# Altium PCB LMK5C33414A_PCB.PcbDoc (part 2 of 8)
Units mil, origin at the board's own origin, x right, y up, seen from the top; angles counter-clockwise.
Board outline 7000 x 9161 mil, 8 copper layers (L1-Top Layer (GTL), L2-GND Plane (GP1), L3-Mid-Layer 2 (G1), L4-Mid-Layer 3 (G2), L5-Mid-Layer 4 (G3), L6-Mid-Layer 5 (G4), L7-Mid-Layer 6 (G5), L8-Bottom Layer (GBL)), stack 61.2 mil thick; 521 components, 286 nets, 1393 pads, 2202 vias.

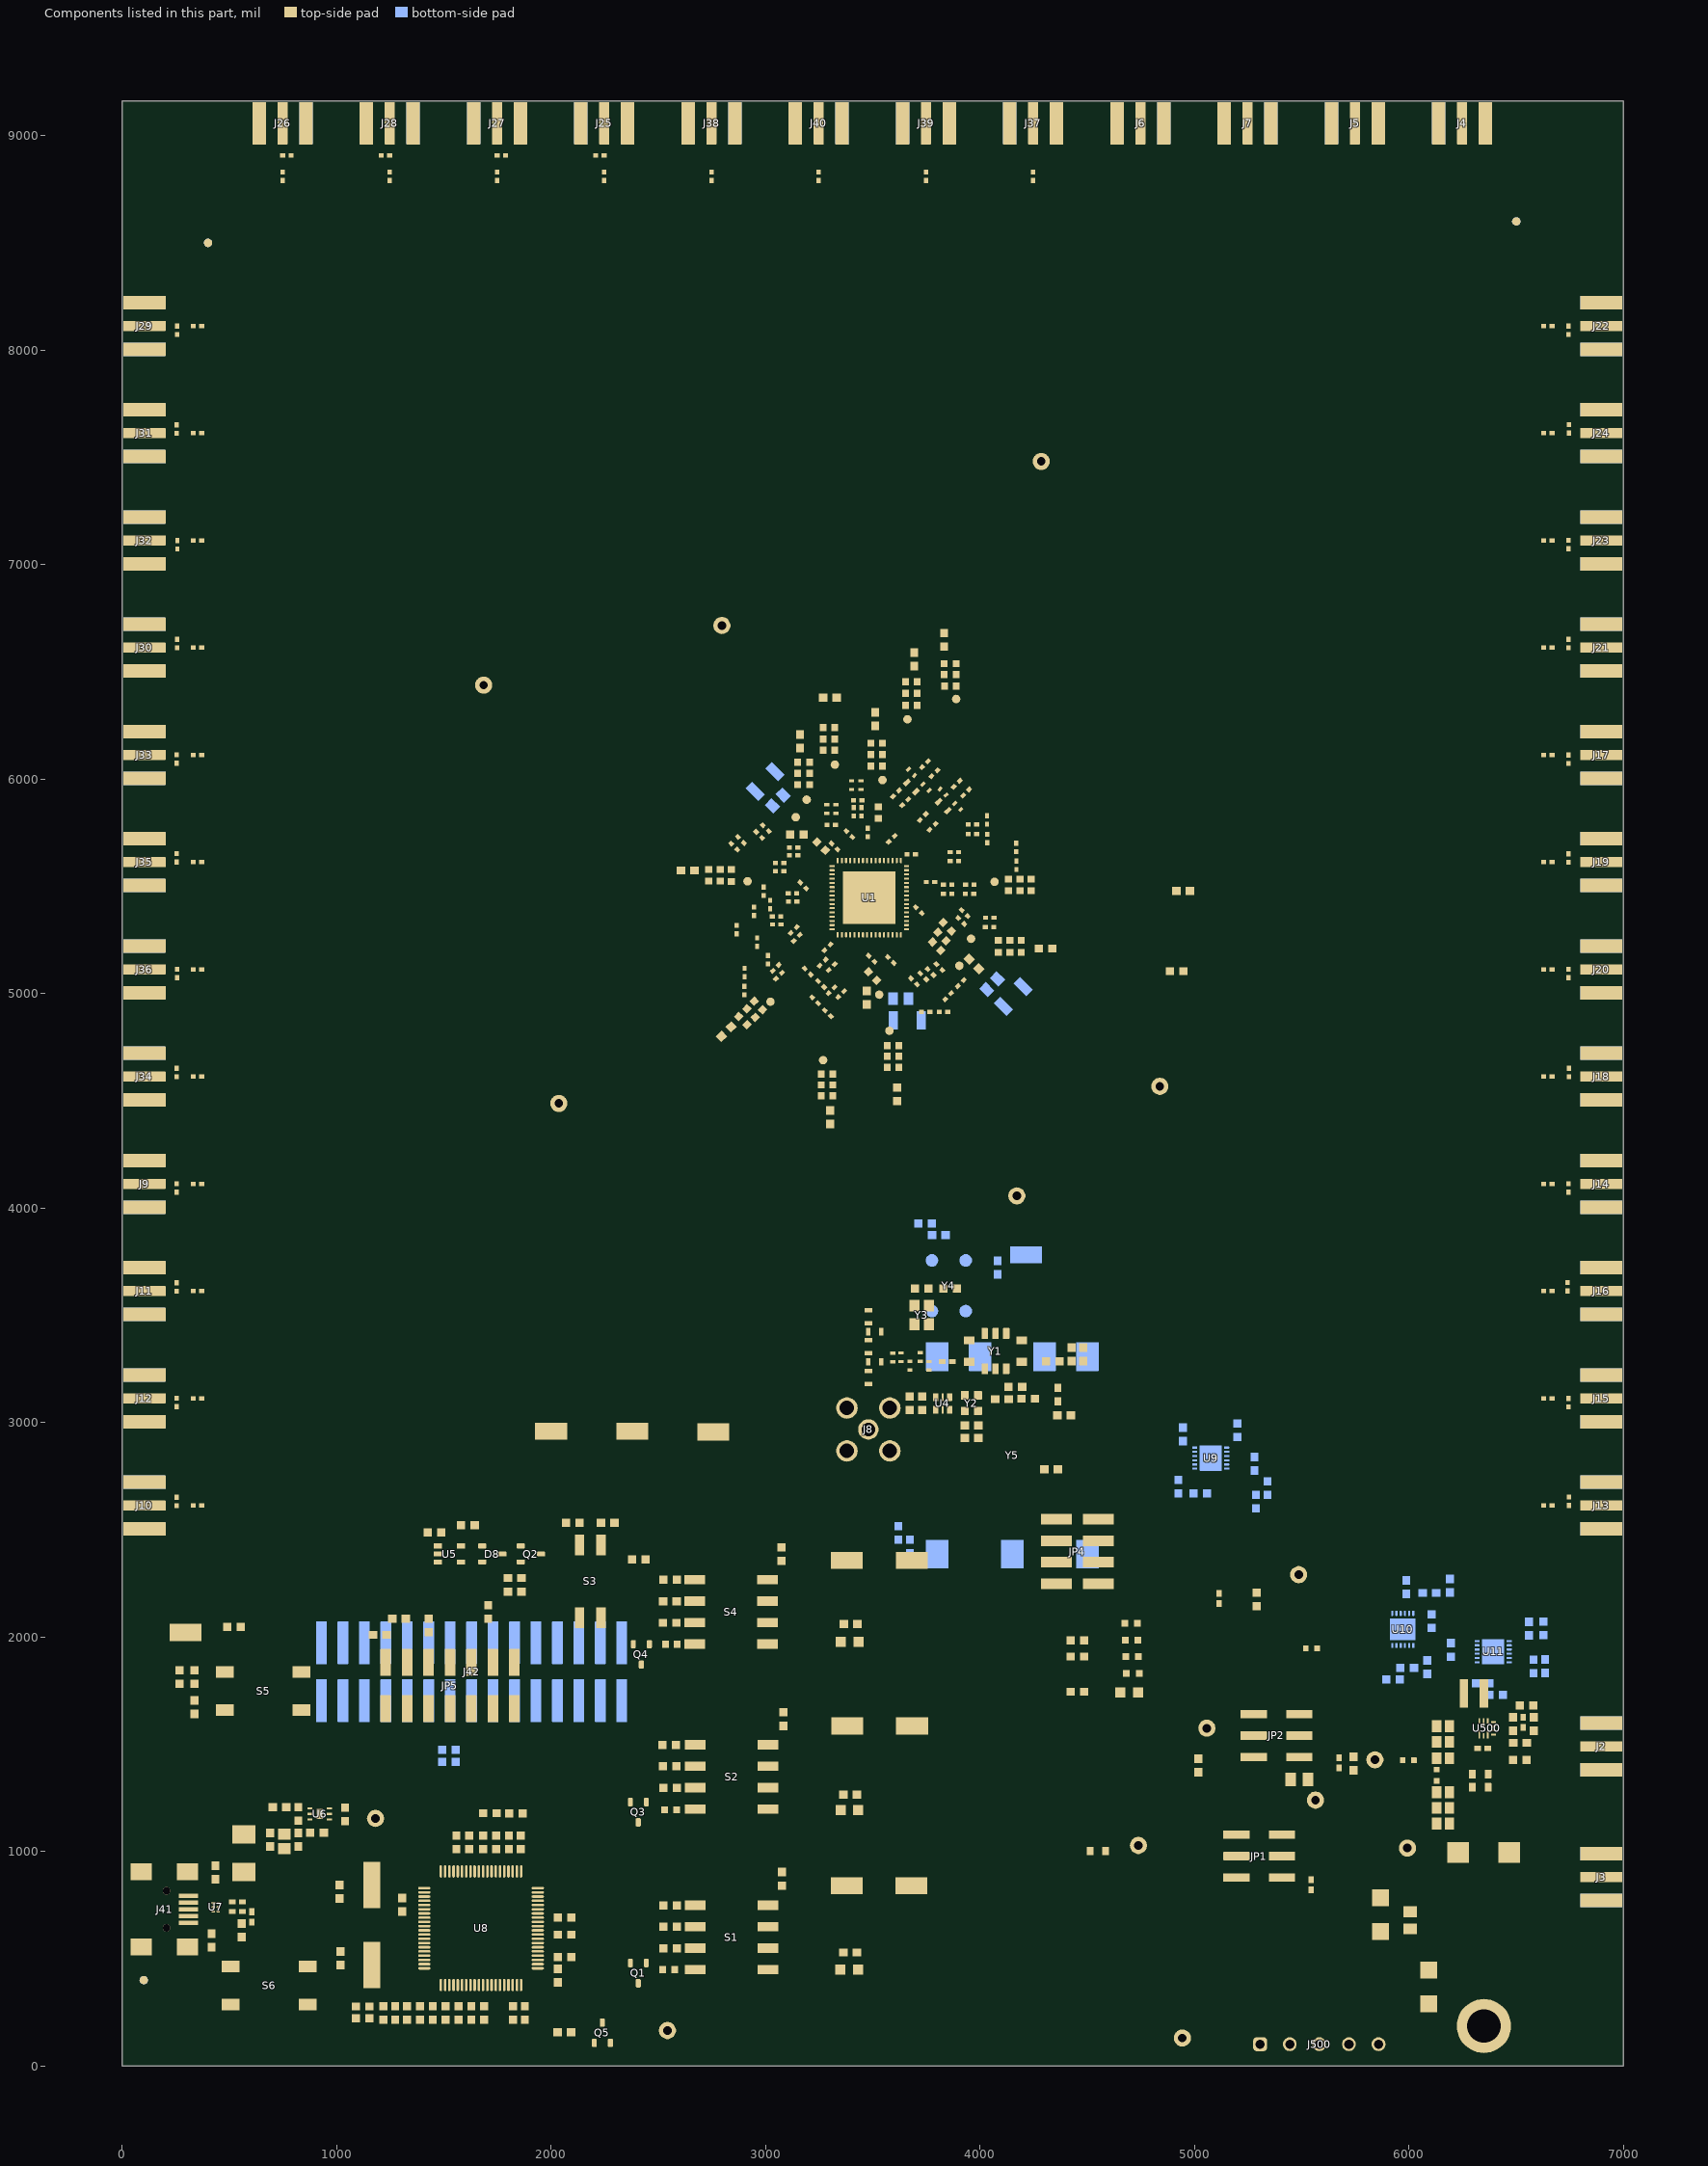
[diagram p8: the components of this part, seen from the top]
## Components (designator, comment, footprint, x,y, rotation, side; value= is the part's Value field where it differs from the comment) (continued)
Q4 "BSS138" SOT-23 2420.31,1918.8 r270 top value=50V
Q5 "BSS138" SOT-23 2238.4,154.32 r90 top value=50V
R1 "CRCW060323K2FKEA" 0603 5991.2,1856.4 r180 bottom value=23.2k
R2 "CRCW060313K3FKEA" 0603 6085.2,1859.4 r90 bottom value=13.3k
R3 "CRCW060323K2FKEA" 0603 6343.2,1784.4 r180 bottom value=23.2k
R5 "CRCW060313K3FKEA" 0603 6406.2,1730.4 r180 bottom value=13.3k
R6 "RK73Z1ETTP" 0402L 3266,5144 r225 top value=0
R7 "RK73Z1ETTP" 0402L 3352,4997 r225 top value=0
R8 "CRCW060323K2FKEA" 0603 4924,2701 r90 bottom value=23.2k
R9 "CRCW060313K3FKEA" 0603 5027,2669 r180 bottom value=13.3k
R10 "RK73Z1ETTP" 0402L 3308,5123 r225 top value=0
R11 "CRCW06030000Z0EA" 0603 3832.36,6649.5 r90 top value=0
R12 "CRCW06030000Z0EA" 0603 2816.76,4822.22 r225 top value=0
R13 "Resistor" 0603 4453.36,1983.18 r0 top value=470
R14 "Resistor" 0603 4453.36,1908.44 r0 top value=470
R15 "Resistor" 0603 4331.09,2780.89 r0 top value=470
R16 "CRCW06030000Z0EA" 0603 3693.18,6558.4 r90 top value=0
R17 "CRCW06030000Z0EA" 0603 3301.03,4423.17 r270 top value=0
R18 "CRCW06030000Z0EA" 0603 3511.08,6279.33 r90 top value=0
R19 "CRCW06030000Z0EA" 0603 4947.24,5478.79 r0 top value=0
R20 "CRCW06030000Z0EA" 0603 3612.65,4530.27 r270 top value=0
R21 "CRCW06030000Z0EA" 0603 2636.5,5573.42 r180 top value=0
R22 "CRCW06030000Z0EA" 0603 4304.83,5210.12 r0 top value=0
R24 "CRCW06030000Z0EA" 0603 3300,6380 r180 top value=0
R25 "CRCW06030000Z0EA" 0603 3160.02,6175.71 r90 top value=0
R26 "CRCW04020000Z0EDHP" 0402L 3934.69,5937.26 r225 top value=0
R27 "CRCW04020000Z0EDHP" 0402L 3778.3,5777.55 r225 top value=0
R28 "RC0402JR-0751RL" 0402S 3895.63,5872.08 r135 top value=51
R29 "CRCW0603100RFKEA" 0603S 3828.19,5873.76 r315 top value=100
R30 "CRCW04020000Z0EDHP" 0402L 3891.24,5977.73 r225 top value=0
R31 "CRCW04020000Z0EDHP" 0402L 3732.94,5822.69 r225 top value=0
R32 "RC0402JR-0751RL" 0402S 3827.19,5939.76 r315 top value=51
R33 "CRCW04020000Z0EDHP" 0402L 3743.11,6068.89 r225 top value=0
R34 "CRCW04020000Z0EDHP" 0402L 3607.91,5932.81 r225 top value=0
R35 "RC0402JR-0751RL" 0402S 3679.67,6030.76 r315 top value=51
R36 "CRCW0603100RFKEA" 0603S 3679.61,5962.39 r135 top value=100
R37 "CRCW04020000Z0EDHP" 0402L 3787.11,6026.89 r225 top value=0
R38 "CRCW04020000Z0EDHP" 0402L 3650.61,5891.39 r225 top value=0
R39 "RC0402JR-0751RL" 0402S 3747.61,5961.39 r135 top value=51
R40 "Capacitor" 0603S 3479,3493 r90 top value=0.1uF
R41 "Resistor" 0603S 3479,3353.4 r90 top value=0
R42 "Resistor" 0603S 3509,3423 r180 top value=49.9
R43 "CRCW040233R0JNED" 0402 3846.56,3283.85 r0 top value=33
R44 "ERJ-3GEY0R00V" 0603 4224.36,3110.68 r180 top value=0
R45 "Resistor" 0603 4101.93,3108.93 r180 top value=10k
R46 "CRCW04020000Z0EDHP" 0402S 3760.85,3263.89 r270 top value=0
R47 "CRCW040233R0JNED" 0402S 3720.85,3304.78 r90 top value=33
R48 "CRCW040233R0JNED" 0402S 3631.08,3304.13 r90 top value=33
R49 "CRCW040233R0JNED" 0402S 3592.08,3302.71 r90 top value=33
R50 "CRCW040233R0JNED" 0402S 3672.76,3264.22 r270 top value=33
R51 "Resistor" 0603 2555.01,748.55 r0 top value=10k
R52 "Resistor" 0603 2555.01,648.55 r0 top value=0
R53 "CRCW06033K90JNEA" 0603 2555.01,548.55 r0 top value=3.9k
R54 "Resistor" 0603 4453.36,1744.56 r180 top value=470
R55 "Resistor" 0603L 2548,449 r180 top value=0
R56 "Resistor" 0603 3393.51,529.08 r180 top value=470
R57 "Resistor" 0603 1835.01,1177.36 r0 top value=1.5k
R58 "Resistor" 0603 1714.47,1178.52 r180 top value=1.5k
R59 "Resistor" 0603 1201,2010 r180 top value=1.5k
R60 "Resistor" 0603 1291,2085 r180 top value=1.5k
R61 "Resistor" 0603 1455.41,2486.9 r0 top value=0
R62 "Resistor" 0603 1830.04,2210.2 r180 top value=100k
R63 "Resistor" 0603 2549.78,1495.82 r0 top value=10k
R64 "Resistor" 0603 2552.58,1397.12 r0 top value=0
R65 "CRCW06033K90JNEA" 0603 2554.26,1295.82 r0 top value=3.9k
R66 "Resistor" 0603L 2557,1194 r180 top value=0
R67 "Resistor" 0603 3393.51,1265.08 r180 top value=470
R68 "Resistor" 0603 2100.26,2531.71 r0 top value=10k
R69 "Resistor" 0603 2263.26,2531.71 r180 top value=3.9k
R70 "Resistor" 0603 2554.44,2266.55 r0 top value=10k
R71 "Resistor" 0603 2553.2,2166.55 r180 top value=0
R72 "CRCW06033K90JNEA" 0603 2552.7,2066.05 r0 top value=3.9k
R73 "Resistor" 0603L 2560.14,1966.55 r180 top value=0
R74 "Resistor" 0603 3396.02,2059.81 r180 top value=470
R75 "Resistor" 0603 267.14,1812.72 r270 top value=10k
R76 "Resistor" 0603 337.14,1672.72 r90 top value=1.0k
R77 "ESR03EZPJ101" 0603 337.14,1812.72 r90 top value=100
R78 "RC0402JR-0751RL" 0402L 254,4093 r270 top value=51
R79 "RC0402JR-0751RL" 0402L 253,2632 r90 top value=51
R80 "RK73Z1ETTP" 0402L 3307,5015 r225 top value=0
R81 "RK73Z1ETTP" 0402L 3691.74,5056.26 r315 top value=0
R82 "RC0402JR-0751RL" 0402L 254,3632 r90 top value=51
R83 "RK73Z1ETTP" 0402L 3810,5123 r315 top value=0
R84 "RK73Z1ETTP" 0402L 3735,5080 r315 top value=0
R85 "RC0402JR-0751RL" 0402L 254,3093 r270 top value=51
R86 "RC0402JR-0751RL" 0402L 6745,2633 r90 top value=51
R87 "RK73Z1ETTP" 0402L 3769,5100 r315 top value=0
R88 "RC0402JR-0751RL" 0402L 6744,4093 r270 top value=51
R89 "RK73Z1ETTP" 0402L 3848,5508 r0 top value=0
R90 "RC0402JR-0751RL" 0402L 6744,3092 r270 top value=51
R91 "RK73Z1ETTP" 0402L 3911.97,5338.03 r315 top value=0
R92 "RC0402JR-0751RL" 0402L 6739.7,3632.9 r90 top value=51
R93 "RK73Z1ETTP" 0402L 3848,5465 r0 top value=0
R94 "RC0402JR-0751RL" 0402L 6744,6092 r270 top value=51
R95 "RK73Z1ETTP" 0402L 3928,5375 r315 top value=0
R96 "RC0402JR-0751RL" 0402L 6745,4632 r90 top value=51
R97 "RK73Z1ETTP" 0402L 3880,5617 r0 top value=0
R98 "RK73Z1ETTP" 0402L 3964,5787.73 r0 top value=0
R99 "RC0402JR-0751RL" 0402L 6743,5632 r90 top value=51
R100 "RK73Z1ETTP" 0402L 3880,5659 r0 top value=0
R101 "RC0402JR-0751RL" 0402L 6744,5093 r270 top value=51
R102 "RK73Z1ETTP" 0402L 3964,5743.73 r0 top value=0
R103 "RC0402JR-0751RL" 0402L 6743,6632 r90 top value=51
R104 "RK73Z1ETTP" 0402L 3131,5680 r180 top value=0
R105 "RC0402JR-0751RL" 0402L 6743,8092 r270 top value=51
R106 "RK73Z1ETTP" 0402L 3065,5570 r180 top value=0
R107 "RK73Z1ETTP" 0402L 3130,5644 r180 top value=0
R108 "RK73Z1ETTP" 0402L 3065,5609 r180 top value=0
R109 "RC0402JR-0751RL" 0402L 6744,7093 r270 top value=51
R110 "RK73Z1ETTP" 0402L 3125,5467 r180 top value=0
R111 "RC0402JR-0751RL" 0402L 6745,7633 r90 top value=51
R112 "RK73Z1ETTP" 0402L 3052,5322 r180 top value=0
R113 "RC0402JR-0751RL" 0402L 2227,8907 r180 top value=51
R114 "RK73Z1ETTP" 0402L 3126,5428 r180 top value=0
R115 "RC0402JR-0751RL" 0402L 768,8907 r0 top value=51
R116 "RK73Z1ETTP" 0402L 3051,5359 r180 top value=0
R117 "RC0402JR-0751RL" 0402L 1768,8907 r0 top value=51
R118 "RK73Z1ETTP" 0402L 3131,5296 r225 top value=0
R119 "RC0402JR-0751RL" 0402L 1227,8907 r180 top value=51
R120 "RK73Z1ETTP" 0402L 3062,5082.63 r225 top value=0
R121 "RC0402JR-0751RL" 0402L 255,8092 r270 top value=51
R122 "RC0402JR-0751RL" 0402L 255,6632 r90 top value=51
R123 "RK73Z1ETTP" 0402L 3145,5259 r225 top value=0
R124 "RK73Z1ETTP" 0402L 3047,5119.63 r225 top value=0
R125 "RC0402JR-0751RL" 0402L 254,7632 r90 top value=51
R126 "RK73Z1ETTP" 0402L 3447,5847 r90 top value=0
R127 "RC0402JR-0751RL" 0402L 257,7092 r270 top value=51
R128 "RK73Z1ETTP" 0402L 351,3612.5 r180 top value=0
R129 "RC0402JR-0751RL" 0402L 254,6093 r270 top value=51
R130 "RK73Z1ETTP" 0402L 3411,5847 r90 top value=0
R131 "RC0402JR-0751RL" 0402L 254,4632 r90 top value=51
R132 "RK73Z1ETTP" 0402L 351,4112.5 r180 top value=0
R133 "RC0402JR-0751RL" 0402L 254,5633 r90 top value=51
R134 "RC0402JR-0751RL" 0402L 2901.71,5097.43 r90 top value=51
R135 "RC0402JR-0751RL" 0402L 255,5093 r270 top value=51
R136 "RC0402JR-0751RL" 0402S 3444.59,5971.63 r90 top value=51
R137 "CRCW04020000Z0EDHP" 0402L 4247.5,8810 r270 top value=0
R138 "RC0402JR-0751RL" 0402S 3284.39,5860.05 r90 top value=51
R139 "CRCW04020000Z0EDHP" 0402L 2747.5,8810 r270 top value=0
R140 "CRCW04020000Z0EDHP" 0402L 3747.5,8810 r270 top value=0
R141 "RC0402JR-0751RL" 0402S 3400.59,5971.63 r90 top value=51
R142 "CRCW04020000Z0EDHP" 0402L 3247.5,8810 r270 top value=0
R143 "RC0402JR-0751RL" 0402S 3328.39,5860.05 r90 top value=51
R144 "Resistor" 0402 536,765 r180 top value=33
R145 "Resistor" 0603 820.5,1174.59 r90 top value=33k
R146 "Resistor" 0402 536,720 r180 top value=33
R147 "Resistor" 0402 604,695 r90 top value=1.5k
R148 "Resistor" 0603 416,585 r90 top value=33k
R149 "Resistor" 0603 557,632 r90 top value=1.2Meg
R150 "Resistor" 0603 2031.21,420.35 r270 top value=0
R151 "Resistor" 0603 2062.71,611.85 r0 top value=0
R152 "Resistor" 0603 2062.71,506.85 r0 top value=0
R153 "Resistor" 0603 2062.71,691.85 r0 top value=0
R154 "Resistor" 0603 1857.71,1041.85 r90 top value=0
R155 "Resistor" 0603 1802.71,1041.85 r270 top value=0
R156 "Resistor" 0603 1742.71,1041.85 r270 top value=0
R157 "Resistor" 0603 1617.71,1041.85 r90 top value=0
R158 "CRCW06030000Z0EA" 0603 1557.71,1041.85 r90 top value=0
R159 "CRCW06031K00JNEA" 0603 1567.71,246.85 r270 top value=1.0k
R160 "CRCW06031K00JNEA" 0603 1627.71,246.85 r270 top value=1.0k
R161 "Resistor" 0603 1272.71,246.85 r270 top value=510
R162 "Resistor" 0603 1387.71,246.85 r270 top value=510
R163 "Resistor" 0603 1447.71,246.85 r270 top value=0
R164 "Resistor" 0603 1507.71,246.85 r270 top value=0
R165 "Resistor" 0603 1121.21,276.85 r0 top value=33k
R166 "Resistor" 0603 2061,157 r180 top value=510
R167 "RC0402JR-0751RL" 0402L 3196.3,5102.4 r135 top value=51
R168 "RC0402JR-0751RL" 0402L 3290.1,4907.7 r315 top value=51
R169 "RC0402JR-0751RL" 0402L 3258.6,5044.1 r315 top value=51
R170 "RC0402JR-0751RL" 0402L 3230.7,4968.5 r135 top value=51
R171 "RC0402JR-0751RL" 0402L 3746.02,4914.81 r180 top value=51
R172 "RC0402JR-0751RL" 0402L 3909.91,5048.39 r45 top value=51
R173 "RC0402JR-0751RL" 0402L 3829.55,4914.64 r0 top value=51
R174 "RC0402JR-0751RL" 0402L 3850.94,4987.2 r225 top value=51
R175 "RC0402JR-0751RL" 0402L 4044.49,5309.45 r0 top value=51
R176 "RC0402JR-0751RL" 0402L 3952,5508 r0 top value=51
R177 "RC0402JR-0751RL" 0402L 4044.82,5353.81 r0 top value=51
R178 "RC0402JR-0751RL" 0402L 4032,5809 r90 top value=51
R179 "RC0402JR-0751RL" 0402L 4169,5598 r270 top value=51
R180 "RC0402JR-0751RL" 0402L 4034,5723 r270 top value=51
R181 "RC0402JR-0751RL" 0402L 3000.7,5770.85 r135 top value=51
R182 "RC0402JR-0751RL" 0402L 2853.44,5684.89 r135 top value=51
R183 "RC0402JR-0751RL" 0402L 2969.59,5739.74 r135 top value=51
R184 "RC0402JR-0751RL" 0402L 2884.55,5716 r135 top value=51
R185 "RC0402JR-0751RL" 0402L 2991.21,5477 r90 top value=51
R186 "RC0402JR-0751RL" 0402L 2864,5298 r270 top value=51
R187 "RC0402JR-0751RL" 0402L 3021,5415 r270 top value=51
R188 "RC0402JR-0751RL" 0402L 2946,5383 r90 top value=51
R189 "RC0402JR-0751RL" 0402L 2960,5239 r90 top value=51
R190 "RC0402JR-0751RL" 0402L 2901.07,5013.86 r270 top value=51
R191 "RC0402JR-0751RL" 0402L 3010.72,5158 r270 top value=51
R192 "CRCW0402100RFKED" 0402L 3429.5,5901.3 r0 top value=100
R193 "CRCW0402100RFKED" 0402L 3306.3,5786.7 r180 top value=100
R201 "Resistor" 0603 6095.2,2205.4 r180 bottom value=47k
R202 "Resistor" 0603 6559.2,2039.4 r270 bottom value=47k
R203 "Resistor" 0603 5340,2694 r270 bottom value=47k
R204 "RC0402JR-0751RL" 0402L 3951,5465 r0 top value=51
R205 "RC0402JR-0751RL" 0402L 4168,5681 r90 top value=51
R206 "RC0603JR-070RL" 0603 4339,3285 r180 top value=0
R207 "RC0603JR-070RL" 0603 3960,2927 r180 top value=0
R208 "RC0603JR-070RL" 0603 3860.06,3624.84 r180 top value=0
R209 "RC0603JR-070RL" 0603 3743,3928 r0 bottom value=0
R210 "RC0603JR-070RL" 0603 3619.07,2485 r270 bottom value=0
R211 "RC0603JR-070RL" 0603 3671,3089 r90 top value=0
R212 "Resistor" 0603 1523,1473 r180 bottom value=0
R500 "ERJ-3GEY0R00V" 0603 6516.1,1427.1 r180 top value=0
R501 "RG1608P-562-B-T5" 0603 6485.1,1593.4 r270 top value=5.60k
R502 "CRCW060318K2FKEA" 0603 6548,1680.8 r180 top value=18.2k
R504 "RT0603BRD071K8L" 0603 6581.9,1593.4 r90 top value=1.80k
S1 "SW_4SPST" SW_219-4LPST 2840.7,598.55 r0 top
S2 "SW_4SPST" SW_219-4LPST 2841.3,1347.55 r0 top
S3 "SW_219-2LPST" SW_219-2LPST 2181.76,2259.71 r90 top
S4 "SW_4SPST" SW_219-4LPST 2838.89,2116.55 r0 top
S5 "PDN" SW_FSM4JSMA 656.89,1748.14 r90 top
S6 "BSL" SW_FSM4JSMA 685,375 r90 top
SH1 "SNT-100-BK-G" SNT-100-BK-G 5316.8,878.7 r180 top value=1x2
SH2 "SNT-100-BK-G" SNT-100-BK-G 5381.7,1441.6 r180 top value=1x2
SH4 "SNT-100-BK-G" SNT-100-BK-G 4455.8,2247.5 r180 top value=1x2
SH5 "SNT-100-BK-G" SNT-100-BK-G 1226,1775 r90 top value=1x2
SH6 "SNT-100-BK-G" SNT-100-BK-G 1329,1775 r90 top value=1x2
TP1 "VDD_DCDC" Keystone5000 5992.6,1015.5 r0 top
TP2 "VDD" Keystone5000 4738.19,1027.87 r0 top
TP4 "VDDO_DCDC" Keystone5000 5841.1,1427.2 r180 top
TP5 "VDDO" Keystone5000 5057.36,1574.59 r0 top
TP7 "VIN2" Keystone5000 5563.8,1239.2 r90 top
TP8 "VDD_IN0" TP_SM_1MM 3888.33,6373.35 r135 top
TP9 "VDDO_01" TP_SM_1MM 3022.58,4961.73 r315 top
TP10 "VDD_IN1" TP_SM_1MM 3661.18,6278.63 r270 top
TP11 "VDDO_23" TP_SM_1MM 3268.02,4689.1 r0 top
TP12 "VDD_DIG" TP_SM_1MM 3544.7,5995.31 r180 top
TP13 "VDDO_4TO7" TP_SM_1MM 4067.45,5520.77 r90 top
TP14 "VDD_APLL1_XO" TP_SM_1MM 3577,4825.94 r180 top
TP15 "VDDO_8TO13" TP_SM_1MM 2915.38,5523.18 r135 top
TP16 "VDD_APLL2" TP_SM_1MM 3957.71,5255.11 r90 top
TP17 "VDD_IN23" TP_SM_1MM 3322.5,6067.14 r270 top
TP18 "VDD_APLL3" TP_SM_1MM 3191.41,5903.83 r0 top
TP19 "GND" Keystone5001 4171.45,4056.53 r0 top
TP20 "GND" Keystone5001 4837.9,4567.14 r180 top
TP21 "GND" Keystone5001 2035.56,4487.64 r180 top
TP22 "GND" Keystone5001 2796,6716 r180 top
TP23 "GND" Keystone5001 1685,6438 r0 top
TP24 "GND" Keystone5001 4285,7481 r90 top
TP25 "GND" Keystone5001 4943,130 r180 top
TP26 "GND" Keystone5001 2542,165 r90 top
TP27 "LF1" TP_SM_1MM 3529.53,4994.42 r180 top
TP28 "LF2" TP_SM_1MM 3903.24,5129.23 r90 top
TP29 "LF3" TP_SM_1MM 3140.18,5822.1 r90 top
TP30 "Vc" Keystone_5019 4213.84,3781.64 r180 bottom
TP31 "GPIO0" Keystone_5019 3378,840 r0 top
TP32 "GND" Keystone_5019 3679,840 r0 top
TP33 "GPIO1" Keystone_5019 3380,1585 r0 top
TP34 "SCL/SCK" Keystone_5019 2000,2959 r180 top
TP35 "GND" Keystone_5019 3683,1585 r0 top
TP36 "SDA/SDIO" Keystone_5019 2378,2959 r180 top
TP37 "ADD/SCS" Keystone_5019 2756,2956 r0 top
TP38 "GPIO2" Keystone_5019 3378,2357 r0 top
TP39 "GND" Keystone_5019 3682,2357 r0 top
TP40 "PDN" Keystone_5019 294.81,2020.61 r180 top
TP41 "MCU_3V3" Keystone5000 1180.98,1153.97 r0 top
TP501 "VDD_XO_DCDC" Keystone5000 5485.4,2290.5 r90 top
U1 "LMK5C33414ARGCR" RGC0064E-MFG 3483.15,5446.85 r90 top locked
U4 "CDC64XX-2520" DLF0006A 3825.05,3088.7 r90 top
U5 "TI-XOR-1-2IN-5" DBV0005A_N 1525.41,2386.9 r0 top
U6 "LP5900SD-3.3/NOPB" NGF0006A 920.5,1174.59 r180 top
U7 "TPD4E004DRYR" DRY0006A 436,740 r0 top
U8 "MSP430F5529IPN" PN0080A_N 1672.71,641.85 r90 top
U9 "LP38798SD-ADJ/NOPB" DNT0012B 5075.06,2833.49 r180 bottom
U10 "LP38798SD-ADJ/NOPB" DNT0012B 5970.95,2035.4 r270 bottom
U11 "LP38798SD-ADJ/NOPB" DNT0012B 6392.2,1931.4 r180 bottom
U500 "TPS62913RPUT" RPU0010A 6357.5,1574 r270 top
Y1 "7N48071001" FP-7N48071001_SMT10_7MM0_5MM0-MFG 4071.72,3332.66 r180 top
Y2 "LMK6CE04800ADLE" TXC_8W 3959.39,3090.31 r180 top
Y3 "7X-50.000MBB-T" OSC_TXC-7X 3727.32,3501.04 r270 top
Y4 "ROM9070PA" FP-ROM9070PA_SMD4-MFG 3854.21,3637.36 r270 bottom
Y5 "ROX2522S4" "FP-ROX2522S4_SMD_ OCXO7_25MM4_22MM0-MFG" 4150.17,2846.25 r180 bottom locked
Y6 "Xtal" XTAL_CSM-7X 1162.71,656.85 r270 top
ZZ1 "This Assembly Note is for PCB labels only" AssemblyNoteLabel 200,10300 r0 top
ZZ2 "These assemblies are ESD sensitive, ESD precautions shall be observed." AssemblyNote 200,10200 r0 top
ZZ3 "These assemblies must be clean and free from flux and all contaminants. Use of no clean flux is not acceptable." AssemblyNote 200,10100 r0 top
ZZ4 "These assemblies must comply with workmanship standards IPC-A-610 Class 2, unless otherwise specified." AssemblyNote 200,10000 r0 top
ZZ5 "Default Shunt (SH) settings for JP* headers: Connect Shunts (SH) on JP1(1-2=DC/DC to VDD), JP2(1-2=DC/DC to VDDO), JP4(1-2=DC/DC to XO), JP5(1-2=SDA, 3-4=SCL)." AssemblyNote 200,9900 r0 top
ZZ6 "Place serial number sticker on top side of PCB." AssemblyNote 204.71,9793.79 r0 top
ZZ7 "This Assembly SMA connectors must be installed per manufacturers procedure." AssemblyNote 200,9700 r0 top

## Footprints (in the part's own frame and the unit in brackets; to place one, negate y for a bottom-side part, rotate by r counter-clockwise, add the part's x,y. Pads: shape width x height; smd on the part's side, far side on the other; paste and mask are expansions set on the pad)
3M_SJ61A6 [mil] "BUMPER CYLIN 0.312\" DIA"
  body extent -156,-156 156,156, height 195
0402 [mm] "0402 from SM-752 data"
  rect 0.8x0.6 smd: 1(-0.6,0) 2(0.6,0)
  silkscreen extent -1.22,-0.52 1.22,0.52, body extent -0.55,-0.3 0.55,0.3, height 0.6
0402L [mm] "0402 from SM-752 data"
  rect 0.6x0.5 smd: 1(-0.5,0) 2(0.5,0)
  body extent -0.55,-0.3 0.55,0.3, height 0.6
0402S [mil] "Based on C0402S footprint from PADS legacy"
  rect 15x24 smd: 1(-20,0) 2(20,0)
  body extent -22,-12 22,12, height 24
0603 [mm] "0603 from SM-752 data"
  rect 1x0.95 smd: 1(-0.8,0) 2(0.8,0)
  silkscreen extent -1.52,-0.69 1.52,0.69, body extent -0.87,-0.47 0.87,0.47, height 1
0603L [mm] "0603 from SM-752 data"
  rect 0.8x0.85 smd: 1(-0.7,0) 2(0.7,0)
  silkscreen extent -0.07,-0.32 0.07,0.32, body extent -0.87,-0.47 0.87,0.47, height 1
0603S [mil]
  rect 20x35 smd: 1(-30,0) 2(30,0)
  body extent -34,-19 34,19, height 39
0805 [mm] "0805 from SM-752 data"
  rect 1.3x1.5 smd: 1(-0.85,0) 2(0.85,0)
  silkscreen extent -1.72,-0.97 1.72,0.97, body extent -1.1,-0.72 1.1,0.72, height 1.45
0805_150 [mm] "0805 / 1.5 mm height"
  rect 1.15x1.45 smd: 1(-0.9,0) 2(0.9,0)
  silkscreen extent -0.1,-0.8 0.1,0.8, body extent -1.1,-0.72 1.1,0.72, height 1.5
0805_HV [mil] "0805 with 30mil clearance between pads"
  rect 50x63 smd: 1(-40,0) 2(40,0)
  silkscreen extent -74,-40 74,40, body extent -43,-29 43,29, height 57
0805L [mm] "0805 from SM-752 data"
  rect 1.1x1.4 smd: 1(-0.75,0) 2(0.75,0)
  body extent -1.1,-0.72 1.1,0.72, height 1.45
1210_280 [mm] "SMD, 2-Leads, Body 3.6x2.8mm, Height 2.8mm"
  rect 1.1x2.2 smd: 1(-1.65,0) 2(1.65,0)
  silkscreen extent -0.84,-1.4 0.84,1.4, body extent -1.8,-1.4 1.8,1.4, height 2.8
7343-43 [mm] "Medium density IPC based on Kemet T495 series"
  rect 2.55x2.45 smd: 1(-3.025,0) 2(3.025,0)
  silkscreen extent -4.56,-2.3 3.8,2.3, body extent -3.8,-2.3 3.8,2.3, height 4.3
AssemblyNote [mil] "Assembly Note"
AssemblyNoteLabel [mil] "Assembly Note for PCB Labels"
CONN_USB-Mini-B-1734035-2 [mm] "Tyco Connectivity recommended land pattern"
  rect 0.5x2.3 smd: 1(-1.6,2.6) 2(-0.8,2.6) 3(0,2.6) 4(0.8,2.6) 5(1.6,2.6)
  rect 2x2.5 smd: 6(4.45,2.5) 7(4.45,-3) 8(-4.45,-3) 9(-4.45,2.5)
  round 0.9 hole 0.9 unplated: 10(2.2,0) 11(-2.2,0)
  silkscreen extent -5,-5 4.9,4.19, body extent -4.95,-5.9 4.95,3.3, height 4.1
DBV0005A_N [mm] "SOT23, 5-Leads, Body 2.9x1.6mm, Pitch 0.95mm, Lead Span 2.8mm, IPC Medium Density"
  rrect17% 1x0.6 smd: 1(-1.375,0.95) 2(-1.375,0) 3(-1.375,-0.95) 4(1.375,-0.95) 5(1.375,0.95)
  silkscreen extent -1.63,-1.55 0.38,1.55, body extent -1.42,-1.46 1.42,1.46, height 1.09
DLF0006A [mm] "VSON-6"
  rrect15% 0.9x0.65 smd paste-0.65: 1(-0.75,0.825) 3(-0.75,-0.825) 4(0.75,-0.825) 6(0.75,0.825)
  rrect40% 0.9x0.25 smd: 2(-0.75,0) 5(0.75,0)
  silkscreen extent -1.5,-1.45 1.5,1.45, body extent -1,-1.25 1,1.25, height 0.9
DNT0012B [mm] "SON, 12-Leads, Body 4x4mm, Pitch 0.5mm"
  rrect40% 0.6x0.25 smd: 1(-1.9,1.25) 2(-1.9,0.75) 3(-1.9,0.25) 4(-1.9,-0.25) 5(-1.9,-0.75) 6(-1.9,-1.25) 7(1.9,-1.25) 8(1.9,-0.75) 9(1.9,-0.25) 10(1.9,0.25) 11(1.9,0.75) 12(1.9,1.25)
  rrect4% 2.6x3 smd paste-1.3: 13(0,0)
  silkscreen extent -2.2,-2.2 2.2,2.2, body extent -2,-2 2,2, height 0.81
DRY0006A [mm] "USON-6"
  rrect67% 0.45x0.3 smd paste-0.05 mask-0.05: 1(-0.275,0.5)
  rrect67% 0.4x0.3 smd paste-0.05 mask-0.05: 2(-0.3,0) 3(-0.3,-0.5) 4(0.3,-0.5) 5(0.3,0) 6(0.3,0.5)
  body extent -0.5,-0.72 0.5,0.73, height 0.58
FCC_disclaimer [mil]
Fiducial10-20 [mm]
  round 1 smd mask+0.5: 1(0,0)
  L1-Top Layer (GTL) keep-out circle w1.178: c0,0 r0.5
FP-7N48071001_SMT10_7MM0_5MM0-MFG [mm]
  rrect13% 0.76x1.28 smd paste+0 mask+0: 1(-1.27,-2.09) 2(0,-2.09) 3(1.27,-2.09) 6(1.27,2.09) 7(0,2.09) 8(-1.27,2.09)
  rrect11% 1.28x0.94 smd paste+0 mask+0: 4(3.1,-1.27) 5(3.1,1.27) 9(-3.1,1.27) 10(-3.1,-1.27)
  silkscreen extent -3.57,-3.4 3.57,2.58, body extent -3.84,-2.83 3.84,2.83, height 0.25
FP-54202-G0807LF_HDR14-MFG [mm]
  rrect8% 1.27x3.18 smd paste+0 mask+0: A01(-7.62,-2.73) A02(-5.08,-2.73) A03(-2.54,-2.73) A04(0,-2.73) A05(2.54,-2.73) A06(5.08,-2.73) A07(7.62,-2.73) B01(-7.62,2.73) B02(-5.08,2.73) B03(-2.54,2.73) B04(0,2.73) B05(2.54,2.73) B06(5.08,2.73) B07(7.62,2.73)
  silkscreen extent -10.23,-3.75 10.23,2.48, body extent -10.33,-4.42 10.33,4.42, height 0.25
FP-BLE18PS080SN1_0603-MFG [mm]
  rrect15% 0.65x0.7 smd paste+0 mask+0: 1(-0.675,0) 2(0.675,0)
  body extent -1.1,-0.58 1.1,0.58, height 0.25
FP-C2012X7S1E106K125AC_0805-MFG [mm]
  rrect13% 0.8x1.05 smd paste+0 mask+0: 1(-0.925,0) 2(0.925,0)
  silkscreen extent -0.15,-0.72 0.15,0.72, body extent -1.43,-0.82 1.43,0.82, height 0.25
FP-CON-SMA-EDGE-S_CONN_JACK-MFG [mm]
  rrect8% 1.2x5 smd paste+0 mask+0: 1(0,-7.26)
  rrect6% 1.6x5 smd paste+0 mask+0: 2(-2.77,-7.26) 3(2.77,-7.26)
  rrect6% 1.6x5 smd far side paste+0 mask+0: 4(-2.77,-7.26) 5(2.77,-7.26)
  body extent -3.27,-9.86 3.27,4.86, height 0.25
FP-ROM9070PA_SMD4-MFG [mm]
  round 1.5 smd paste+0 mask+0: 1(-3,-2) 2(3,-2) 3(3,2) 4(-3,2)
  silkscreen extent -4.95,-4.5 4.95,3.85, body extent -4.85,-3.75 4.85,3.75, height 4.1
"FP-ROX2522S4_SMD_ OCXO7_25MM4_22MM0-MFG" [mm]
  rrect4% 2.7x3.4 smd paste+0 mask+0: 1(-8.9,-11.7) 2(0,-11.7) 3(8.9,-11.7) 4(8.9,11.7) 5(3.81,11.7) 6(-3.81,11.7) 7(-8.9,11.7)
  silkscreen extent -11.1,-14.1 11.1,12.8, body extent -11,-12.7 11,12.7, height 15.4
FP-XGL4030-222MEC_SMT_IND_4MM0_4MM0-MFG [mm]
  rrect10% 0.98x3.4 smd paste+0 mask+0: 1(-1.185,0) 2(1.185,0)
  silkscreen extent -2.15,-2.15 2.15,2.15, body extent -2.25,-2.25 2.25,2.25, height 0.25
Johnson_142-0701-20x [mil] "Johnson Components recommended land pattern"
  round 95 hole 62: 1(0,0)
  round 100 hole 67: 2(100,100) 3(100,-100) 4(-100,-100) 5(-100,100)
  body extent -156,-156 156,156, height 375
Keystone5000 [mil] "For Keystone 500x miniature loop terminals"
  round 80 hole 40: 1(0,0)
  silkscreen extent -52,-52 52,52, body extent -49,-49 49,49, height 182
Keystone5001 [mil] "For Keystone 500x miniature loop terminals"
  round 80 hole 40: 1(0,0)
  silkscreen extent -52,-52 52,52, body extent -49,-49 49,49, height 182
Keystone_5019 [mm] "Test Point, Miniature, SMT"
  rect 3.8x2.03 smd: 1(0,0)
  silkscreen extent -2.31,-1.42 2.31,1.42, body extent -1.91,-1.02 1.9,1.02, height 2.29
Label_650x200 [mil] "Thermal Transfer Label"
  round 1 on Mech13: 0(0,0)
  silkscreen extent -325,-100 325,100, body extent -325,-100 325,100, height 1
LED_LTST-C170 [mm] "LITE-ON"
  rect 1.2x1.2 smd: 1(-1.05,0) 2(1.05,0)
  silkscreen extent -1.6,-1 2.2,1, body extent -1.05,-0.67 1.05,0.67, height 1.1
LED_LTST-C170_Red [mm] "LITE-ON"
  rect 1.2x1.2 smd: 1(-1.05,0) 2(1.05,0)
  silkscreen extent -1.6,-1 2.2,1, body extent -1.05,-0.67 1.05,0.67, height 1.1
LED_LTST-C190 [mm] "Lite-On"
  rect 0.8x0.8 smd: 1(-0.75,0) 2(0.75,0)
  silkscreen extent -1.1,-0.8 1.8,0.8, body extent -0.85,-0.45 0.85,0.45, height 0.9
LI0603D [mm] "LAIRD"
  rect 1x0.8 smd: 1(-0.8,0) 2(0.8,0)
  silkscreen extent -1.53,-0.63 1.53,0.63, body extent -0.87,-0.47 0.87,0.47, height 0.95
Molex_0393570005 [mil] "Terminal Block, 3.5mm, 5x1, TH"
  rrect50% 64.5x64.5 hole 43: 1(0,276)
  round 64.5 hole 43: 2(0,138) 3(0,0) 4(0,-138) 5(0,-276)
  body extent -136,-345 151,345, height 335
MTGP_252mil_157mil_6Via [mil] "4-40 Mounting Hole, Plated, for Pan Head"
  round 252 hole 157: 1(0,0)
NetTie_0603 [mm] "Net Tie 0603 size"
  rect 0.8x0.95 smd paste-1: 1(-0.9,0) 2(0.9,0)
  L1-Top Layer (GTL) region: -0.6,0.406 0.6,0.406 0.6,-0.406 -0.6,-0.406
  silkscreen extent -0.1,-0.38 0.1,0.38
NGF0006A [mm] "TI"
  rect 0.6x0.25 smd: 1(-1.15,0.65) 2(-1.15,0) 3(-1.15,-0.65) 4(1.15,-0.65) 5(1.15,0) 6(1.15,0.65)
  rect 0.75x1.2 smd paste-0.38: 7(0,0)
  silkscreen extent -1.4,-1.25 1.4,1.25, body extent -1.3,-1.15 1.3,1.15, height 0.81
OSC_TXC-7X [mm] "TXC recommended land pattern"
  rect 1.4x1.2 smd: 1(-1.1,-0.85) 2(1.1,-0.85) 3(1.1,0.85) 4(-1.1,0.85)
  silkscreen extent -1.31,-1.96 -1.2,-1.84, body extent -2.03,-1.65 2.03,1.65, height 1.11
PN0080A_N [mm] "QFP, 80-Leads, Body 12x12mm, Pitch 0.5mm, IPC Medium Density"
  oval 1.45x0.3 smd: 1(-6.725,4.75) 2(-6.725,4.25) 3(-6.725,3.75) 4(-6.725,3.25) 5(-6.725,2.75) 6(-6.725,2.25) 7(-6.725,1.75) 8(-6.725,1.25) 9(-6.725,0.75) 10(-6.725,0.25) 11(-6.725,-0.25) 12(-6.725,-0.75) 13(-6.725,-1.25) 14(-6.725,-1.75) 15(-6.725,-2.25) 16(-6.725,-2.75) 17(-6.725,-3.25) 18(-6.725,-3.75) 19(-6.725,-4.25) 20(-6.725,-4.75) 41(6.725,-4.75) 42(6.725,-4.25) 43(6.725,-3.75) 44(6.725,-3.25) 45(6.725,-2.75) 46(6.725,-2.25) 47(6.725,-1.75) 48(6.725,-1.25) 49(6.725,-0.75) 50(6.725,-0.25) 51(6.725,0.25) 52(6.725,0.75) 53(6.725,1.25) 54(6.725,1.75) 55(6.725,2.25) 56(6.725,2.75) 57(6.725,3.25) 58(6.725,3.75) 59(6.725,4.25) 60(6.725,4.75)
  oval 0.3x1.45 smd: 21(-4.75,-6.725) 22(-4.25,-6.725) 23(-3.75,-6.725) 24(-3.25,-6.725) 25(-2.75,-6.725) 26(-2.25,-6.725) 27(-1.75,-6.725) 28(-1.25,-6.725) 29(-0.75,-6.725) 30(-0.25,-6.725) 31(0.25,-6.725) 32(0.75,-6.725) 33(1.25,-6.725) 34(1.75,-6.725) 35(2.25,-6.725) 36(2.75,-6.725) 37(3.25,-6.725) 38(3.75,-6.725) 39(4.25,-6.725) 40(4.75,-6.725) 61(4.75,6.725) 62(4.25,6.725) 63(3.75,6.725) 64(3.25,6.725) 65(2.75,6.725) 66(2.25,6.725) 67(1.75,6.725) 68(1.25,6.725) 69(0.75,6.725) 70(0.25,6.725) 71(-0.25,6.725) 72(-0.75,6.725) 73(-1.25,6.725) 74(-1.75,6.725) 75(-2.25,6.725) 76(-2.75,6.725) 77(-3.25,6.725) 78(-3.75,6.725) 79(-4.25,6.725) 80(-4.75,6.725)
  silkscreen extent -6.85,-5.6 5.6,5.6, body extent -7,-7 7,7, height 1.56
RGC0064E-MFG [mm]
  rrect42% 0.6x0.24 smd paste+0 mask+0: 1(-4.4,3.75) 2(-4.4,3.25) 3(-4.4,2.75) 4(-4.4,2.25) 5(-4.4,1.75) 6(-4.4,1.25) 7(-4.4,0.75) 8(-4.4,0.25) 9(-4.4,-0.25) 10(-4.4,-0.75) 11(-4.4,-1.25) 12(-4.4,-1.75) 13(-4.4,-2.25) 14(-4.4,-2.75) 15(-4.4,-3.25) 16(-4.4,-3.75) 33(4.4,-3.75) 34(4.4,-3.25) 35(4.4,-2.75) 36(4.4,-2.25) 37(4.4,-1.75) 38(4.4,-1.25) 39(4.4,-0.75) 40(4.4,-0.25) 41(4.4,0.25) 42(4.4,0.75) 43(4.4,1.25) 44(4.4,1.75) 45(4.4,2.25) 46(4.4,2.75) 47(4.4,3.25) 48(4.4,3.75)
  rrect42% 0.24x0.6 smd paste+0 mask+0: 17(-3.75,-4.4) 18(-3.25,-4.4) 19(-2.75,-4.4) 20(-2.25,-4.4) 21(-1.75,-4.4) 22(-1.25,-4.4) 23(-0.75,-4.4) 24(-0.25,-4.4) 25(0.25,-4.4) 26(0.75,-4.4) 27(1.25,-4.4) 28(1.75,-4.4) 29(2.25,-4.4) 30(2.75,-4.4) 31(3.25,-4.4) 32(3.75,-4.4) 49(3.75,4.4) 50(3.25,4.4) 51(2.75,4.4) 52(2.25,4.4) 53(1.75,4.4) 54(1.25,4.4) 55(0.75,4.4) 56(0.25,4.4) 57(-0.25,4.4) 58(-0.75,4.4) 59(-1.25,4.4) 60(-1.75,4.4) 61(-2.25,4.4) 62(-2.75,4.4) 63(-3.25,4.4) 64(-3.75,4.4)
  rrect2% 6.25x6.25 smd paste-1000 mask+0: 65(0,0)
  silkscreen extent -5.4,-4.57 4.57,4.57, body extent -4.8,-4.8 4.8,4.8, height 0.25
RPU0010A [mm] "VQFN-10"
  rrect50% 0.65x0.2 smd: 1(-0.875,0.25) 3(-0.875,-0.75) 5(0.875,-0.25)
  rrect50% 1x0.2 smd: 2(-0.7,-0.25) 4(0.7,-0.75) 6(0.7,0.25)
  rrect50% 0.25x0.55 smd: 7(0.75,0.925) 8(0.25,0.925) 9(-0.25,0.925) 10(-0.75,0.925)
  silkscreen extent -1.2,0.6 -1.1,0.8, body extent -1.05,-1.05 1.05,1.05, height 1
Samtec_HTST-115-01-x-DV [mm] "Header, 2.54mm, 15x2, SMT"
  rrect8% 5.08x1.27 smd: 1(-3.43,17.78) 2(3.43,17.78) 3(-3.43,15.24) 4(3.43,15.24) 5(-3.43,12.7) 6(3.43,12.7) 7(-3.43,10.16) 8(3.43,10.16) 9(-3.43,7.62) 10(3.43,7.62) 11(-3.43,5.08) 12(3.43,5.08) 13(-3.43,2.54) 14(3.43,2.54) 15(-3.43,0) 16(3.43,0) 17(-3.43,-2.54) 18(3.43,-2.54) 19(-3.43,-5.08) 20(3.43,-5.08) 21(-3.43,-7.62) 22(3.43,-7.62) 23(-3.43,-10.16) 24(3.43,-10.16) 25(-3.43,-12.7) 26(3.43,-12.7) 27(-3.43,-15.24) 28(3.43,-15.24) 29(-3.43,-17.78) 30(3.43,-17.78)
  silkscreen extent -4.8,-22.86 4.83,22.86, body extent -5.59,-22.86 5.59,22.86, height 10.17
Samtec_TSM-104-01-x-DV [mm] "Header, 2.54mm, 4x2, SMT"
  rect 3.68x1.27 smd: 1(-2.475,3.81) 2(2.475,3.81) 3(-2.475,1.27) 4(2.475,1.27) 5(-2.475,-1.27) 6(2.475,-1.27) 7(-2.475,-3.81) 8(2.475,-3.81)
  silkscreen extent -1.65,-5.08 1.65,5.22, body extent -3.85,-5.08 3.85,5.08, height 9.65
SMA [mm] "Molded Diode, 2-Leads, Body 4.3x2.6mm, IPC Medium Density, based on OnSemi component dimensions and land pattern"
  rect 2x2 smd: 1(-2,0) 2(2,0)
  silkscreen extent -3.66,-1.57 2.79,1.57, body extent -2.6,-1.3 2.6,1.3, height 2.42
SMB [mil] "Molded Diode, 2-Leads, Body 5.4x3.6mm, IPC Medium Density, based on OnSemi component dimensions"
  rect 85x107.99 smd: 1(-87.01,0) 2(87.01,0)
  silkscreen extent -155,-82 125,82, body extent -106,-71 106,71, height 91
SNT-100-BK-G [mil] "Samtec STEP model"
  round 1 on Mech3: 0(0,0)
  body extent -100,-50 100,50, height 344
SOT-23 [mm] "SOT23, 3-Leads, Body 2.9x1.3mm, Pitch 0.95mm, Lead Span 2.5mm, IPC Medium Density"
  rrect50% 1x0.6 smd: 1(-1.2,0.95) 2(-1.2,-0.95) 3(1.2,0)
  silkscreen extent -1.62,-1.5 0.7,1.5, body extent -1.16,-1.45 1.21,1.45, height 1
SW_219-2LPST [mm] "SW, Tape Seal, 2 POS, SMD"
  rect 2.44x1.12 smd: 1(-4.305,1.27) 2(-4.305,-1.27) 3(4.305,-1.27) 4(4.305,1.27)
  silkscreen extent -3.32,-3.28 3.38,3.28, body extent -4.95,-3.28 4.96,3.27, height 4.25
SW_219-4LPST [mil] "SMD, 8-Leads, Body 11.93x6.95mm, Pitch 2.54mm"
  rect 96x44 smd: 1(-169.5,150) 2(-169.5,50) 3(-169.5,-50) 4(-169.5,-150) 5(169.5,-150) 6(169.5,-50) 7(169.5,50) 8(169.5,150)
  silkscreen extent -171,-229 132,229, body extent -195,-229 195,229, height 169
SW_FSM4JSMA [mm] "Alcoswitch"
  rrect7% 1.4x2.1 smd: 1(2.25,4.55) 2(2.25,-4.55) 3(-2.25,4.55) 4(-2.25,-4.55)
  body extent -3,-5 3,5, height 5.09
TP_SM_1MM [mm] "1mm Test Point, SMT"
  round 1 smd paste-0.5: 1(0,0)
TXC_8W [mm] "SMD, 4-Leads, Body 2x2.5 mm"
  rrect13% 0.95x1 smd: 1(-0.775,0.925) 2(-0.775,-0.925) 3(0.775,-0.925) 4(0.775,0.925)
  silkscreen extent -1.5,0.5 -1.5,1.4, body extent -1,-1.25 1,1.25, height 0.9
Wurth_61000621121 [mm] "Header, 2.54mm, 3x2, SMT"
  rrect10% 3.1x1 smd: 1(-2.7,2.54) 2(2.7,2.54) 3(-2.7,0) 4(2.7,0) 5(-2.7,-2.54) 6(2.7,-2.54)
  body extent -3.75,-3.81 3.75,3.81, height 9.6
XTAL_CSM-7X [mm] "ECS"
  rect 5.5x2 smd: 1(-4.75,0) 2(4.75,0)
  silkscreen extent -6.2,-2.5 6.2,2.5, body extent -5.95,-2.4 5.95,2.4, height 4.3

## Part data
C1 C2 C8 C9 C22 C23 C29 C32 C35 C38 C44 C47 C50 C53 C56 C59 C62 C63 C64 C65 C66 C79 C97 C129 C130: library part CMP-0007003-5, "CAP, CERM, 10 uF, 10 V, +/- 20%, X5R, 0603", Cap_Case=0603, Manufacturer=TDK, PartNumber=C1608X5R1A106M080AC, Supplier Part Number 1=445-6853-1-ND, TempCo=X5R, Tolerance_%=20%, Value1="0.0078 ohm", Value2=10V, ValueDisplayed=10uF
C6 C21: library part CMP-0006869-5, "CAP, CERM, 1 uF, 10 V, +/- 10%, X5R, 0603", Cap_Case=0603, Manufacturer=Kemet, PartNumber=C0603C105K8PACTU, Supplier Part Number 1=399-3118-1-ND, TempCo=X5R, Tolerance_%=10%, Value1=Unknown, Value2=10V, ValueDisplayed=1uF
C7 C13 C24: library part CMP-0007003-5, "CAP, CERM, 10 uF, 10 V, +/- 20%, X5R, 0603", Cap_Case=0603, Manufacturer=TDK, PartNumber=C1608X5R1A106M080AC, Supplier Part Number 1=445-6853-1-ND, TempCo=X5R, Tolerance_%=20%, Value1="0.0078 ohm", Value2=10V, ValueDisplayed=10nF
C10 C27: library part CMP-0078699-1, "CAP, CERM, 47 µF, 10 V,+/- 20%, X5R, 0805", Cap_Case=0805, Manufacturer=MuRata, Supplier Part Number 1=490-9961-1-ND, TempCo=X5R, Tolerance_%=20%, Value2=10V, ValueDisplayed=47µF
C28 C31 C34 C37 C40 C43 C46 C49 C52 C55 C58 C78 C80 C81 C82 C83 C84 C85 C87 R40: library part CMP-0006856-6, "CAP, CERM, 0.1 uF, 25 V, +/- 5%, X7R, 0603", Cap_Case=0603, Manufacturer=Kemet, PartNumber=C0603C104J3RACTU, Supplier Part Number 1=399-1282-1-ND, TempCo=X7R, Tolerance_%=5%, Value1=Unknown, Value2=25V, ValueDisplayed=0.1uF
C30 C33 C36 C39 C42 C45 C48 C51 C54 C57 C60: library part CMP-0006259-2, "CAP, CERM, 0.1 uF, 10 V, +/- 10%, X5R, 0402", Cap_Case=0402, Manufacturer=TDK, PartNumber=C1005X5R1A104K050BA, Supplier Part Number 1=445-1265-1-ND, TempCo=X5R, Tolerance_%=10%, Value1=Unknown, Value2=10V, ValueDisplayed=0.1uF
C41: library part CMP-0006869-5, "CAP, CERM, 1 uF, 10 V, +/- 10%, X5R, 0603", Cap_Case=0603, Manufacturer=Kemet, Supplier Part Number 1=399-3118-1-ND, TempCo=X5R, Tolerance_%=10%, Value1=Unknown, Value2=10V, ValueDisplayed=1uF
C61: library part CMP-0007044-5, "CAP, CERM, 0.1 uF, 50 V, +/- 10%, X7R, 0603", Cap_Case=0603, Manufacturer=TDK, Supplier Part Number 1=445-1314-1-ND, TempCo=X7R, Tolerance_%=10%, Value1="0.0296 ohm", Value2=50V, ValueDisplayed=0.1uF
C67 C70 C71 C72 C96: library part CMP-0006856-6, "CAP, CERM, 0.1 uF, 25 V, +/- 5%, X7R, 0603", Cap_Case=0603, Manufacturer=Kemet, Supplier Part Number 1=399-1282-1-ND, TempCo=X7R, Tolerance_%=5%, Value1=Unknown, Value2=25V, ValueDisplayed=0.1uF
C68: library part CMP-0078743-1, "CAP, CERM, 0.047 µF, 25 V,+/- 5%, C0G/NP0, AEC-Q200 Grade 1, 0805", Cap_Case=0805_150, Manufacturer=Kemet, Supplier Part Number 1=399-8092-1-ND, TempCo=C0G/NP0, Tolerance_%=5%, Value2=25V, ValueDisplayed=0.047µF
C69 C74 C77: library part CMP-0081101-1, "CAP, CERM, 0.1 µF, 50 V,+/- 5%, C0G/NP0, 1210", Cap_Case=1210, Manufacturer=TDK, Supplier Part Number 1=445-2702-1-ND, TempCo=C0G/NP0, Tolerance_%=5%, Value2=50V, ValueDisplayed=0.1µF
C73 C76: library part CMP-0078743-1, "CAP, CERM, 0.047 µF, 25 V,+/- 5%, C0G/NP0, AEC-Q200 Grade 1, 0805", Cap_Case=0805_150, Manufacturer=Kemet, PartNumber=C0805C473J3GACTU, Supplier Part Number 1=399-8092-1-ND, TempCo=C0G/NP0, Tolerance_%=5%, Value2=25V, ValueDisplayed=0.047µF
C75: library part CMP-0007373-4, "CAP, CERM, 0.47 uF, 10 V, +/- 10%, X7R, 0603", Cap_Case=0603, Manufacturer=MuRata, Supplier Part Number 1=GRM188R71A474KA61D-ND, TempCo=X7R, Tolerance_%=10%, Value1=Unknown, Value2=10V, ValueDisplayed=0.47uF
C86 C88 C91 C95: library part CMP-0006763-4, "CAP, CERM, 100 pF, 50 V, +/- 5%, C0G/NP0, 0603", Cap_Case=0603, Manufacturer=AVX, PartNumber=06035A101JAT2A, Supplier Part Number 1=478-1175-1-ND, TempCo=C0G/NP0, Tolerance_%=5%, Value1="0.119 ohm", Value2=50V, ValueDisplayed=100pF
C89 C132 C133 C137 C138 C142 C143 C144: library part CMP-0006857-4, "CAP, CERM, 0.1 uF, 16 V, +/- 5%, X7R, 0603", Cap_Case=0603, Manufacturer=Kemet, PartNumber=C0603C104J4RACTU, Supplier Part Number 1=399-1097-1-ND, TempCo=X7R, Tolerance_%=5%, Value1=Unknown, Value2=16V, ValueDisplayed=0.1uF
C90 C154 C155 C156: library part CMP-0006850-4, "CAP, CERM, 0.01 uF, 50 V, +/- 5%, X7R, 0603", Cap_Case=0603, Manufacturer=Kemet, PartNumber=C0603C103J5RACTU, Supplier Part Number 1=399-1092-1-ND, TempCo=X7R, Tolerance_%=5%, Value1=Unknown, Value2=50V, ValueDisplayed=0.01uF
C92 C93: library part CMP-0006722-4, "CAP, CERM, 33 pF, 100 V, +/- 5%, C0G/NP0, 0603", Cap_Case=0603, Manufacturer=AVX, PartNumber=06031A330JAT2A, Supplier Part Number 1=478-1143-1-ND, TempCo=C0G/NP0, Tolerance_%=5%, Value1="0.209 ohm", Value2=100V, ValueDisplayed=33pF
C94: library part CMP-0006722-4, "CAP, CERM, 33 pF, 100 V, +/- 5%, C0G/NP0, 0603", Cap_Case=0603, Manufacturer=AVX, Supplier Part Number 1=478-1143-1-ND, TempCo=C0G/NP0, Tolerance_%=5%, Value1="0.209 ohm", Value2=100V, ValueDisplayed=33pF
C98 C100 C101 C102 C103 C104 C105 C106 C107 C108 C109 C110 C111 C112 C113 C114 C115 C116 C117 C118 C119 C120 C121 C122 C123 C124: library part CMP-0006659-2, "CAP, CERM, 0.1 uF, 25 V, +/- 10%, X7R, 0402", Cap_Case=0402, Manufacturer=MuRata, Supplier Part Number 1=490-10698-1-ND, TempCo=X7R, Tolerance_%=10%, Value1=Unknown, Value2=25V, ValueDisplayed=0.1uF
C131: library part CMP-0008403-2, "CAP, CERM, 22 uF, 10 V, +/- 20%, X5R, 0805", Cap_Case=0805, Manufacturer="Taiyo Yuden", PartNumber=LMK212BJ226MG-T, Supplier Part Number 1=587-1958-1-ND, TempCo=X5R, Tolerance_%=20%, Value1=Unknown, Value2=10V, ValueDisplayed=22uF
C134 C140: library part CMP-0006776-4, "CAP, CERM, 220 pF, 50 V, +/- 1%, C0G/NP0, 0603", Cap_Case=0603, Manufacturer=AVX, PartNumber=06035A221FAT2A, Supplier Part Number 1=478-3719-1-ND, TempCo=C0G/NP0, Tolerance_%=1%, Value1="0.083 ohm", Value2=50V, ValueDisplayed=220pF
C135 C136: library part CMP-0007261-4, "CAP, CERM, 30 pF, 100 V, +/- 5%, C0G/NP0, 0603", Cap_Case=0603, Manufacturer=MuRata, PartNumber=GRM1885C2A300JA01D, Supplier Part Number 1=490-1338-1-ND, TempCo=C0G/NP0, Tolerance_%=5%, Value1=Unknown, Value2=100V, ValueDisplayed=30pF
C139: library part CMP-0006898-4, "CAP, CERM, 2200 pF, 50 V, +/- 10%, X7R, 0603", Cap_Case=0603, Manufacturer=Kemet, PartNumber=C0603C222K5RACTU, Supplier Part Number 1=399-1085-1-ND, TempCo=X7R, Tolerance_%=10%, Value1=Unknown, Value2=50V, ValueDisplayed=2200pF
C141: library part CMP-0007373-4, "CAP, CERM, 0.47 uF, 10 V, +/- 10%, X7R, 0603", Cap_Case=0603, Manufacturer=MuRata, PartNumber=GRM188R71A474KA61D, Supplier Part Number 1=GRM188R71A474KA61D-ND, TempCo=X7R, Tolerance_%=10%, Value1=Unknown, Value2=10V, ValueDisplayed=0.47uF
C500: library part CMP-0011835-2, "CAP, TA, 47 uF, 35 V, +/- 10%, 0.3 ohm, SMD", Cap_Case=X, Manufacturer=Kemet, Supplier Part Number 1=399-3905-1-ND, Tolerance_%=10%, Value1="0.3 ohm", Value2=35V, ValueDisplayed=47uF
C501 C502 C503 C508 C509 C510: library part CMP-0007890-1, "CAP, CERM, 22 uF, 10 V, +/- 20%, X7S, 0805", Cap_Case=0805, Manufacturer=TDK, Supplier Part Number 1=445-14560-1-ND, TempCo=X7S, Tolerance_%=20%, Value1="0.00205 ohm", Value2=10V, ValueDisplayed=22uF
C504 C507 C514 C516: library part CMP-0006663-2, "CAP, CERM, 2200 pF, 25 V, +/- 10%, X7R, 0402", Cap_Case=0402, Manufacturer=MuRata, Supplier Part Number 1=490-5419-1-ND, TempCo=X7R, Tolerance_%=10%, Value1=Unknown, Value2=25V, ValueDisplayed=2200pF
C505 C506: library part CMP-0089528-1, "10µF ±10% 25V Ceramic Capacitor X7S 0805 (2012 Metric)", Digikey Part Number=445-181600-1-ND, Manufacturer=TDK, Mouser Part Number=810-C2012X7S1EK125AC, Operating Temperature Range="-55°C to +125°C", TempCo=22%, Temperature Characteristic=X7S, Tolerance_%=10%, ValueDisplayed=10uF
C511: library part CMP-0087076-3, "CAP CER 270PF 50V NP0 0402", Manufacturer="Taiyo Yuden", TempCo=30ppm/°C, Tolerance_%=5%
C512: library part CMP-0750175-1, "CAP, CERM, 0.47 µF, 25 V,+/- 10%, X7R, 0603", Cap_Case=0603, Manufacturer=TDK, TempCo=X7R, Tolerance_%=10%, Value2=25V, ValueDisplayed=0.47µF
C513 C515: library part CMP-0007497-5, "CAP, CERM, 10 uF, 10 V, +/- 20%, X7R, 0603", Cap_Case=0603, Manufacturer=MuRata, Supplier Part Number 1=81-GRM188Z71A106MA3D, TempCo=X7R, Tolerance_%=20%, Value1=Unknown, Value2=10V, ValueDisplayed=10uF
D1 D2: library part CMP-0028399-2, "Diode, Schottky, 20 V, 2 A, SMA", Manufacturer="Diodes Inc.", PartNumber=B220A-13-F, Value1=2A, Value2=0.5V
D3 D4 D5: library part CMP-0002827-3, "LED, Green, SMD", Color=green, Manufacturer=Lite-On, PartNumber=LTST-C190GKT, Power_TotalModule=100mW, Value1=0.1W, Value2=2.1V
D6: library part CMP-0002829-2, "LED, Red, SMD", Color=red, Manufacturer=Lite-On, PartNumber=LTST-C170KRKT, Supplier Part Number 1=160-1415-1-ND, Value1=W, Value2=2V
D7 D9 D10: library part CMP-0002862-2, "LED, Yellow , SMD", Color=yellow, Manufacturer=Lite-On, PartNumber=LTST-C170KSKT, Value1=W, Value2=2V
D8: library part CMP-0028451-2, "Diode, Schottky, 30 V, 0.2 A, SOT-23", Manufacturer="Diodes Inc.", PartNumber=BAT54-7-F, Value1=0.2A, Value2=0.65V
D11: library part CMP-0005670-2, "Diode, Zener, 7.5 V, 550 mW, SMB", Manufacturer="ON Semiconductor", PartNumber=1SMB5922BT3G, Power_W=550mW, Value1=0.55W
D12: library part CMP-0002827-2, "LED, Green, SMD", Color=green, Manufacturer=Lite-On, PartNumber=LTST-C190GKT, Power_TotalModule=100mW, Supplier Part Number 1=160-1183-1-ND, Value1=0.1W, Value2=2.1V
FB1 FB2 FB3 FB4 FB5 FB6 FB7 FB8 FB9 FB10 FB11: library part CMP-0003353-2, "Ferrite Bead, 220 ohm @ 100 MHz, 2.5 A, 0603", Manufacturer=MuRata, Supplier Part Number 1=490-5225-1-ND, Value1="0.04 ohm", Value2=2.5A, ValueDisplayed="220 ohm"
FB12: library part CMP-0003403-1, "Ferrite Bead, 300 ohm @ 100 MHz, 0.4 A, 1.6x0.8x0.95mm", Manufacturer="Laird-Signal Integrity Products", PartNumber=LI0603D301R-10, Supplier Part Number 1=240-2365-1-ND, Value1="0.35 ohm", Value2=0.4A, ValueDisplayed="300 ohm"
FB13: library part CMP-0003426-2, "Ferrite Bead, 60 ohm @ 100 MHz, 3.5 A, 0603", Manufacturer=TDK, PartNumber=MPZ1608S600ATAH0, Supplier Part Number 1=445-1563-1-ND, Value1="0.02 ohm", Value2=3.5A, ValueDisplayed="60 ohm"
FID1 FID2 FID3 FID4 FID5 FID6: library part CMP-0077181-1, "Fiducial mark.  There is nothing to buy or mount.", Manufacturer=N/A
H1 H3 H4 H5 H6: library part CMP-0079645-1, "BUMPER CYLIN 0.312\" DIA", Manufacturer=3M, Supplier Part Number 1=SJ61A6-ND
J2 J3 J4 J5 J6 J7 J9 J10 J11 J12 J13 J14 J15 J16 J17 J18 J19 J20 J21 J22 J23 J24 J25 J26 J27 J28 J29 J30 J31 J32 J33 J34 J35 J36 J37 J38 J39 J40: library part CMP-0088000-4, "CONN SMA JACK STR EDGE MNT", Manufacturer="RF Solutions Ltd.", PartNumber=CON-SMA-EDGE-S
J8: library part CMP-0055819-1, "Connector, SMA, TH", Manufacturer="Cinch Connectivity", Supplier Part Number 1=J500-ND
J41: library part CMP-0054920-1, "Connector, Receptacle, Mini-USB Type B, R/A, Top Mount SMT", Manufacturer="TE Connectivity", PartNumber=1734035-2, Supplier Part Number 1=A31727CT-ND
J42: library part CMP-0077170-1, "Header, 2.54mm, 15x2, Gold, SMD", Color=Natural, Manufacturer=Samtec, Supplier Part Number 1=84T4837
J500: library part CMP-0080926-1, "Terminal Block, 3.5mm, 5x1, Tin, TH", Color=Black, Current_A=17.5A, Manufacturer=Molex, Voltage_V=300V
JP1 JP2: library part CMP-0079534-2, "Header, 2.54mm, 3x2, Gold, SMT", Color=Black, Current_A=3A, Manufacturer="Wurth Elektronik", Supplier Part Number 1=732-5461-5-ND, Voltage_V=250V
JP4: library part CMP-0075593-2, "Header, 2.54mm, 4x2, Gold, SMT", Color=Black, Current_A=4.9A, Manufacturer=Samtec, Supplier Part Number 1=TSM-104-01-L-DV-ND, Voltage_V=475V
JP5: library part CMP-0088459-1, "Connector Header Surface Mount 14 position 0.100\" (2.54mm)", Current_A=3A, Digikey Part Number=609-6365-ND, Manufacturer="Amphenol ICC", Mouser Part Number=649-54202-G0807LF, Operating Temperature Range="-65°C to +125°C", Voltage_V=1.5kV
L500 L502 L503: library part CMP-0087072-1, "Bead inductor BLE series, 8A", Manufacturer=Murata
L501: library part CMP-0089541-1, "Inductor Power Shielded Wirewound 2.2uH 20% 1MHz Composite 8.7A 15mOhm DCR Automotive T/R", Manufacturer=Coilcraft, Operating Temperature Range="to +165°C", Self Resonant Frequency=40MHz, Test Frequency=1MHz, Tolerance_%=20%
LBL1: library part CMP-0003625-1, "Thermal Transfer Printable Labels, 0.650\" W x 0.200\" H - 10,000 per roll", Manufacturer=Brady, Supplier Part Number 1=97C5133
Logo2: library part CMP-0074847-1, "FCC_disclaimer"
MH1: library part CMP-0078422-2, "PCB Mounting Hole", Manufacturer=Any, PartNumber=N/A
NT1: library part CMP-0078142-3, "Single point connection between nets.", Manufacturer=N/A
Q1 Q3 Q4 Q5: library part CMP-0000755-1, "MOSFET, N-CH, 50 V, 0.22 A, SOT-23", Alternate Manufacturer=None, Manufacturer="Fairchild Semiconductor", Supplier Part Number 1=BSS138CT-ND, Value2="1.7 nC"
Q2: library part CMP-0000281-1, "MOSFET, N-CH, 25 V, 0.22 A, SOT-23", Alternate Manufacturer=None, Manufacturer="Fairchild Semiconductor", Supplier Part Number 1=FDV301NCT-ND, Value2="0.49 nC"
R1 R3 R8: library part CMP-0022228-4, "RES, 23.2 k, 1%, 0.1 W, AEC-Q200 Grade 0, 0603", Manufacturer=Vishay-Dale, Power_W=100mW, Supplier Part Number 1=541-23.2KHCT-ND, TempCo="100 ppm/C", Tolerance_%=1%, Value2=0.1W, Value_Code=23k2, ValueDisplayed=23.2k
R2 R5 R9: library part CMP-0022043-4, "RES, 13.3 k, 1%, 0.1 W, AEC-Q200 Grade 0, 0603", Manufacturer=Vishay-Dale, Power_W=100mW, Supplier Part Number 1=541-13.3KHCT-ND, TempCo="100 ppm/C", Tolerance_%=1%, Value2=0.1W, Value_Code=13k3, ValueDisplayed=13.3k
R6 R7 R10 R80 R81 R83 R84 R87 R89 R91 R93 R95 R97 R98 R100 R102 R104 R106 R107 R108 R110 R112 R114 R116 R118 R120 R123 R124 R126 R128 R130 R132: library part CMP-0027007-2, "RES, 0, 5%, 0.063 W, AEC-Q200 Grade 0, 0402", Manufacturer="KOA Speer", Power_W=63mW, Supplier Part Number 1=660-RK73Z1ETTP, TempCo=ppm/C, Tolerance_%=5%, Value2=0.063W, Value_Code=0000, ValueDisplayed=0
R11 R12 R16 R17 R18 R19 R20 R21 R22 R24 R25 R158: library part CMP-0025697-4, "RES, 0, 5%, 0.1 W, AEC-Q200 Grade 0, 0603", Manufacturer=Vishay-Dale, Power_W=100mW, Supplier Part Number 1=541-0.0GCT-ND, TempCo="200 ppm/C", Tolerance_%=5%, Value2=0.1W, Value_Code=0000, ValueDisplayed=0
R13 R14 R15 R54 R56 R67 R74: library part CMP-0025813-4, "RES, 470, 5%, 0.1 W, AEC-Q200 Grade 0, 0603", Manufacturer=Vishay-Dale, PartNumber=CRCW0603470RJNEA, Power_W=100mW, Supplier Part Number 1=541-470GCT-ND, TempCo="200 ppm/C", Tolerance_%=5%, Value2=0.1W, Value_Code=470R, ValueDisplayed=470
R26 R27 R30 R31 R33 R34 R37 R38 R46 R137 R139 R140 R142: library part CMP-0081856-1, "RES, 0, 0%, 0.2 W, AEC-Q200 Grade 0, 0402", Manufacturer=Vishay-Dale, Power_W=200mW, Supplier Part Number 1=541-0.0YBTR-ND, Tolerance_%=0%, Value2=0.2W, Value_Code=0
R28 R32 R35 R39 R78 R79 R82 R85 R86 R88 R90 R92 R94 R96 R99 R101 R103 R105 R109 R111 R113 R115 R117 R119 R121 R122 R125 R127 R129 R131 R133 R134 R135 R136 R138 R141 R143 R167 R168 R169 R170 R171 R172 R173 R174 R175 R176 R177 R178 R179 R180 R181 R182 R183 R184 R185 R186 R187 R188 R189 R190 R191 R204 R205: library part CMP-0027006-2, "RES, 51, 5%, 0.0625 W, 0402", Manufacturer="Yageo America", Power_W=62.5mW, Supplier Part Number 1=311-51JRCT-ND, TempCo="100 ppm/C", Tolerance_%=5%, Value2=0.0625W, Value_Code=51R0, ValueDisplayed=51
R29 R36: library part CMP-0021991-4, "RES, 100, 1%, 0.1 W, AEC-Q200 Grade 0, 0603", Manufacturer=Vishay-Dale, Power_W=100mW, Supplier Part Number 1=541-100HCT-ND, TempCo="100 ppm/C", Tolerance_%=1%, Value2=0.1W, Value_Code=100R, ValueDisplayed=100
R41 R52 R55 R61 R64 R66 R71 R73 R150 R151 R152 R153 R154 R155 R156 R157 R163 R164 R212: library part CMP-0025697-4, "RES, 0, 5%, 0.1 W, AEC-Q200 Grade 0, 0603", Manufacturer=Vishay-Dale, PartNumber=CRCW06030000Z0EA, Power_W=100mW, Supplier Part Number 1=541-0.0GCT-ND, TempCo="200 ppm/C", Tolerance_%=5%, Value2=0.1W, Value_Code=0000, ValueDisplayed=0
R42: library part CMP-0022448-4, "RES, 49.9, 1%, 0.1 W, AEC-Q200 Grade 0, 0603", Manufacturer=Vishay-Dale, PartNumber=CRCW060349R9FKEA, Power_W=100mW, Supplier Part Number 1=541-49.9HCT-ND, TempCo="100 ppm/C", Tolerance_%=1%, Value2=0.1W, Value_Code=49R9, ValueDisplayed=49.9
R43 R47 R48 R49 R50: library part CMP-0026908-3, "RES, 33, 5%, 0.063 W, AEC-Q200 Grade 0, 0402", Manufacturer=Vishay-Dale, Power_W=63mW, Supplier Part Number 1=541-33JCT-ND, TempCo="200 ppm/C", Tolerance_%=5%, Value2=0.063W, Value_Code=33R0, ValueDisplayed=33
R44 R500: library part CMP-0025874-4, "RES, 0, 5%, 0.1 W, AEC-Q200 Grade 0, 0603", Manufacturer=Panasonic, Power_W=100mW, Supplier Part Number 1=P0.0GCT-ND, TempCo="600 ppm/C", Tolerance_%=5%, Value2=0.1W, Value_Code=0000, ValueDisplayed=0
R45 R51 R63 R68 R70 R75: library part CMP-0025701-4, "RES, 10 k, 5%, 0.1 W, AEC-Q200 Grade 0, 0603", Manufacturer=Vishay-Dale, PartNumber=CRCW060310K0JNEA, Power_W=100mW, Supplier Part Number 1=541-10KGCT-ND, TempCo="200 ppm/C", Tolerance_%=5%, Value2=0.1W, Value_Code=10k0, ValueDisplayed=10k
R53 R65 R72: library part CMP-0025799-4, "RES, 3.9 k, 5%, 0.1 W, AEC-Q200 Grade 0, 0603", Manufacturer=Vishay-Dale, Power_W=100mW, Supplier Part Number 1=541-3.9KGCT-ND, TempCo="200 ppm/C", Tolerance_%=5%, Value2=0.1W, Value_Code=3k90, ValueDisplayed=3.9k
R57 R58 R59 R60: library part CMP-0025733-4, "RES, 1.5 k, 5%, 0.1 W, AEC-Q200 Grade 0, 0603", Manufacturer=Vishay-Dale, PartNumber=CRCW06031K50JNEA, Power_W=100mW, Supplier Part Number 1=541-1.5KGCT-ND, TempCo="200 ppm/C", Tolerance_%=5%, Value2=0.1W, Value_Code=1k50, ValueDisplayed=1.5k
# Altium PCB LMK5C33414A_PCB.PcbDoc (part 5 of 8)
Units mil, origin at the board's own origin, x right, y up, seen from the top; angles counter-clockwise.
Board outline 7000 x 9161 mil, 8 copper layers (L1-Top Layer (GTL), L2-GND Plane (GP1), L3-Mid-Layer 2 (G1), L4-Mid-Layer 3 (G2), L5-Mid-Layer 4 (G3), L6-Mid-Layer 5 (G4), L7-Mid-Layer 6 (G5), L8-Bottom Layer (GBL)), stack 61.2 mil thick; 521 components, 286 nets, 1393 pads, 2202 vias.

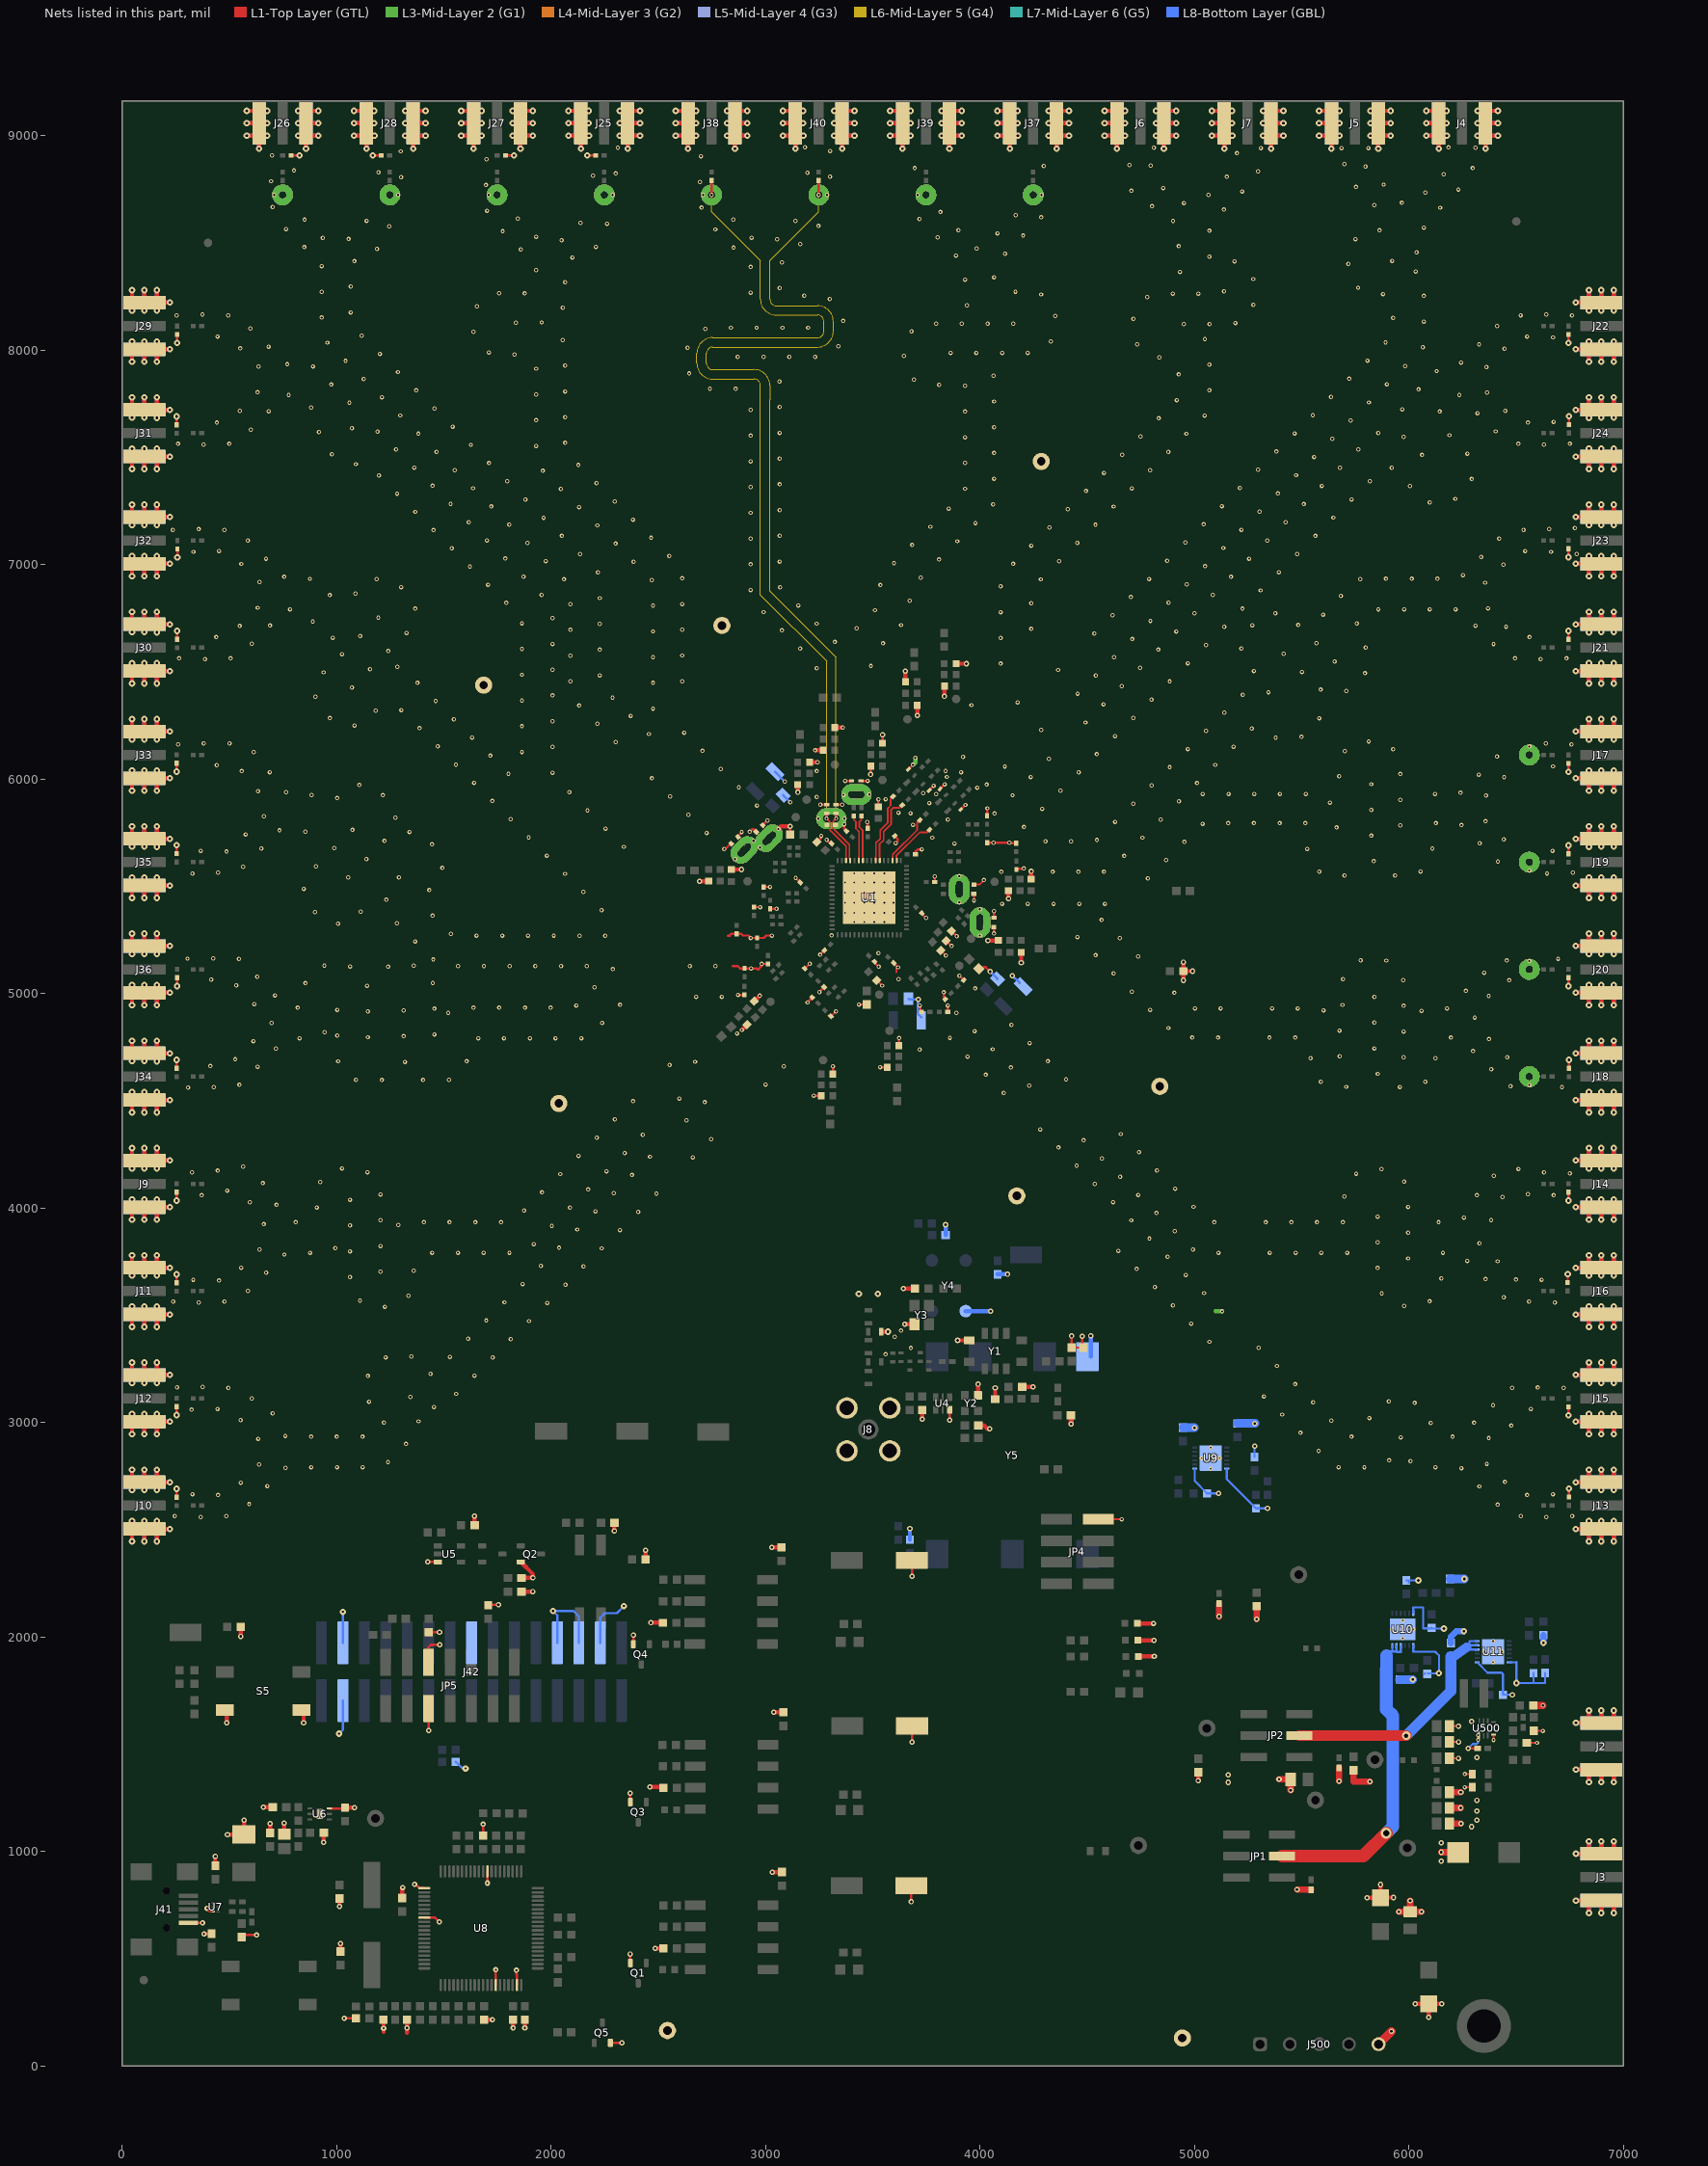
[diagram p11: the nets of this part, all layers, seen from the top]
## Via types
v1: diameter 20, hole 10, L1-Top Layer (GTL) to L8-Bottom Layer (GBL), tented top, 1246 vias
v2: diameter 30, hole 12, L1-Top Layer (GTL) to L8-Bottom Layer (GBL), 519 vias
v3: diameter 25, hole 12, L1-Top Layer (GTL) to L8-Bottom Layer (GBL), tented top, 172 vias
v4: diameter 30, hole 12, L1-Top Layer (GTL) to L8-Bottom Layer (GBL), tented top, 57 vias
v5: diameter 20, hole 10, L1-Top Layer (GTL) to L8-Bottom Layer (GBL), 48 vias
v6: diameter 19.68, hole 7.87, L1-Top Layer (GTL) to L8-Bottom Layer (GBL), 47 vias
v7: diameter 25, hole 10, L1-Top Layer (GTL) to L8-Bottom Layer (GBL), tented top, 35 vias
v8: diameter 25, hole 12, L1-Top Layer (GTL) to L8-Bottom Layer (GBL), 24 vias
v9: diameter 18, hole 10, L1-Top Layer (GTL) to L8-Bottom Layer (GBL), tented top, 12 vias
v10: diameter 30, hole 10, L1-Top Layer (GTL) to L8-Bottom Layer (GBL), 10 vias
v11: diameter 40, hole 20, L1-Top Layer (GTL) to L8-Bottom Layer (GBL), 10 vias
v12: diameter 39.37, hole 19.68, L1-Top Layer (GTL) to L8-Bottom Layer (GBL), tented top, 6 vias
v13: diameter 25, hole 10, L1-Top Layer (GTL) to L8-Bottom Layer (GBL), 5 vias
v14: diameter 23, hole 10, L1-Top Layer (GTL) to L8-Bottom Layer (GBL), tented top, 4 vias
v15: diameter 50, hole 28, L1-Top Layer (GTL) to L8-Bottom Layer (GBL), 4 vias
v16: diameter 20/0/0/0/0/0/20 (per signal layer), hole 10, L1-Top Layer (GTL) to L8-Bottom Layer (GBL), tented top, 2 vias
v17: diameter 25, hole 12, L1-Top Layer (GTL) to L8-Bottom Layer (GBL), tented both sides, 1 vias

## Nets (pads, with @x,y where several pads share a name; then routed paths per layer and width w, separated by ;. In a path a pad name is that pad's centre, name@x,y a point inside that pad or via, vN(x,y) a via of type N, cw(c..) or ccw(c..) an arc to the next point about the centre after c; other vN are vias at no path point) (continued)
GND: (continued)
  L8-Bottom Layer (GBL) w10: v10(1011,1549) 1029,1567 J42.27@1029,1702.96 ; J42.28@1029,1973.04 v10(1029,2117) ; C97.2@1554.5,1418 1555.48,1418 1583.05,1390.43 1596.57,1390.43 v10(1600.4,1386.6) ; J42.8@2029,1973.04 2029,2101 v10(2009,2121) 2104,2121 2129,2096 J42.6@2129,1973.04 ; J42.4@2229,1973.04 2229,2089.63 2250.37,2111 2306,2111 v10(2339,2144) ; v1(3747.89,5352.18) v1@3748.01,5352.06 ; U9.7@5000.26,2784.28 5000.26,2727.24 R9.1@5058.5,2669 v3@5111.99,2669 ; U9.6@5149.87,2784.28 5149.87,2735.64 C156.2@5286,2599.5 v3@5339.5,2599.5 ; C24.2@5280,2839.5 v3(5280,2889) ; C7.2@5987.2,2263.9 v4@6043.36,2263.9 ; C7.2@5999.36,2253.9 C7.2@5999.54,2253.72 ; U10.7@6020.16,1960.6 6020.16,1931.44 6122.16,1931.44 6139.54,1914.06 v4(6139.54,1830.72) R2.1@6087.7,1830.4 ; U10.6@6020.16,2110.2 6020.16,2137.36 6066.16,2137.36 6066.16,2040.44 6103.74,2040.44 C154.2@6105.2,2041.9 ; R2.1@6071.2,1827.9 R2.1@6073.7,1830.4 ; C154.2@6105.46,2038.72 v4(6162.54,2038.72) ; v8(6276.4,1480.4) 6296.8,1500.8 6313.9,1500.8 6322.1,1509 v5(6322.1,1520.3) ; U11.7@6317.4,1882.19 6366.18,1833.4 6432.2,1833.4 6437.7,1827.9 R5.1@6437.7,1730.4 v3(6481.7,1730.4) ; v5(6322.1,1542.3) v5(6322.1,1565.3) ; U11.6@6467,1882.19 6501.2,1882.4 v4(6500.54,1784.72) 6570.2,1784.4 6634.2,1784.4 C13.2@6634.2,1831.9 ; 6580.2,1784.4 C155.2@6580.2,1830.9
  L8-Bottom Layer (GBL) w11: C77.2@3043.3,6034.29 v1(3089.17,5988.43) ; C76.1@3081.55,5925.14 v1(3114.99,5891.7) ; C68.1@3665.78,4976.1 3669.74,4972.14 v3(3711.52,4972.14) 3710.24,4970.86 C69.2@3710.24,4912.19 ; C69.2@3711.52,4903.75 C69.2@3725.65,4889.62 ; v3(4047.22,5102.07) C73.1@4081.26,5068.02 ; v3@4152.02,5082.02 C74.2@4184.62,5049.42
  L8-Bottom Layer (GBL) w15: v1@3687.09,6066.17 v1(3687.09,6066.46) ; v1@3783.31,5968.52 v1(3783.31,5968.81)
  L8-Bottom Layer (GBL) w20: v2(45.56,2445.57) 45.56,2503.44 J10.4@103.43,2503.44 ; v2(45.56,2779.43) 45.56,2721.56 J10.5@103.43,2721.56 ; v2(45.56,2945.57) 45.56,3003.44 J12.4@103.43,3003.44 ; v2(45.56,3279.43) 45.56,3221.56 J12.5@103.43,3221.56 ; v2(45.56,3445.57) 45.56,3503.44 J11.4@103.43,3503.44 ; v2(45.56,3779.43) 45.56,3721.56 J11.5@103.43,3721.56 ; v2(45.56,3945.57) 45.56,4003.44 J9.4@103.43,4003.44 ; v2(45.56,4279.43) 45.56,4221.56 J9.5@103.43,4221.56 ; v2(45.56,4445.57) 45.56,4503.44 J34.4@103.43,4503.44 ; v2(45.56,4779.43) 45.56,4721.56 J34.5@103.43,4721.56 ; v2(45.56,4945.57) 45.56,5003.44 J36.4@103.43,5003.44 ; v2(45.56,5279.43) 45.56,5221.56 J36.5@103.43,5221.56 ; v2(45.56,5445.57) 45.56,5503.44 J35.4@103.43,5503.44 ; v2(45.56,5779.43) 45.56,5721.56 J35.5@103.43,5721.56 ; v2(45.56,5945.57) 45.56,6003.44 J33.4@103.43,6003.44 ; v2(45.56,6279.43) 45.56,6221.56 J33.5@103.43,6221.56 ; v2(45.56,6445.57) 45.56,6503.44 J30.4@103.43,6503.44 ; v2(45.56,6779.43) 45.56,6721.56 J30.5@103.43,6721.56 ; v2(45.56,6945.57) 45.56,7003.44 J32.4@103.43,7003.44 ; v2(45.56,7279.43) 45.56,7221.56 J32.5@103.43,7221.56 ; v2(45.56,7445.57) 45.56,7503.44 J31.4@103.43,7503.44 ; v2(45.56,7779.43) 45.56,7721.56 J31.5@103.43,7721.56 ; v2(45.56,7945.57) 45.56,8003.44 J29.4@103.43,8003.44 ; v2(45.56,8279.43) 45.56,8221.56 J29.5@103.43,8221.56 ; v2(103.43,2445.57) J10.4@103.43,2503.44 ; v2(103.43,2779.43) J10.5@103.43,2721.56 ; v2(103.43,2945.57) J12.4@103.43,3003.44 ; v2(103.43,3279.43) J12.5@103.43,3221.56 ; v2(103.43,3445.57) J11.4@103.43,3503.44 ; v2(103.43,3779.43) J11.5@103.43,3721.56 ; v2(103.43,3945.57) J9.4@103.43,4003.44 ; v2(103.43,4279.43) J9.5@103.43,4221.56 ; v2(103.43,4445.57) J34.4@103.43,4503.44 ; v2(103.43,4779.43) J34.5@103.43,4721.56 ; v2(103.43,4945.57) J36.4@103.43,5003.44 ; v2(103.43,5279.43) J36.5@103.43,5221.56 ; v2(103.43,5445.57) J35.4@103.43,5503.44 ; v2(103.43,5779.43) J35.5@103.43,5721.56 ; v2(103.43,5945.57) J33.4@103.43,6003.44 ; v2(103.43,6279.43) J33.5@103.43,6221.56 ; v2(103.43,6445.57) J30.4@103.43,6503.44 ; v2(103.43,6779.43) J30.5@103.43,6721.56 ; v2(103.43,6945.57) J32.4@103.43,7003.44 ; v2(103.43,7279.43) J32.5@103.43,7221.56 ; v2(103.43,7445.57) J31.4@103.43,7503.44 ; v2(103.43,7779.43) J31.5@103.43,7721.56 ; v2(103.43,7945.57) J29.4@103.43,8003.44 ; v2(103.43,8279.43) J29.5@103.43,8221.56 ; v2(161.3,2445.57) 161.3,2503.44 J10.4@103.43,2503.44 ; v2(161.3,2779.43) 161.3,2721.56 J10.5@103.43,2721.56 ; v2(161.3,2945.57) 161.3,3003.44 J12.4@103.43,3003.44 ; v2(161.3,3279.43) 161.3,3221.56 J12.5@103.43,3221.56 ; v2(161.3,3445.57) 161.3,3503.44 J11.4@103.43,3503.44 ; v2(161.3,3779.43) 161.3,3721.56 J11.5@103.43,3721.56 ; v2(161.3,3945.57) 161.3,4003.44 J9.4@103.43,4003.44 ; v2(161.3,4279.43) 161.3,4221.56 J9.5@103.43,4221.56 ; v2(161.3,4445.57) 161.3,4503.44 J34.4@103.43,4503.44 ; v2(161.3,4779.43) 161.3,4721.56 J34.5@103.43,4721.56 ; v2(161.3,4945.57) 161.3,5003.44 J36.4@103.43,5003.44 ; v2(161.3,5279.43) 161.3,5221.56 J36.5@103.43,5221.56 ; v2(161.3,5445.57) 161.3,5503.44 J35.4@103.43,5503.44 ; v2(161.3,5779.43) 161.3,5721.56 J35.5@103.43,5721.56 ; v2(161.3,5945.57) 161.3,6003.44 J33.4@103.43,6003.44 ; v2(161.3,6279.43) 161.3,6221.56 J33.5@103.43,6221.56 ; v2(161.3,6445.57) 161.3,6503.44 J30.4@103.43,6503.44 ; v2(161.3,6779.43) 161.3,6721.56 J30.5@103.43,6721.56 ; v2(161.3,6945.57) 161.3,7003.44 J32.4@103.43,7003.44 ; v2(161.3,7279.43) 161.3,7221.56 J32.5@103.43,7221.56 ; v2(161.3,7445.57) 161.3,7503.44 J31.4@103.43,7503.44 ; v2(161.3,7779.43) 161.3,7721.56 J31.5@103.43,7721.56 ; v2(161.3,7945.57) 161.3,8003.44 J29.4@103.43,8003.44 ; v2(161.3,8279.43) 161.3,8221.56 J29.5@103.43,8221.56 ; J10.4@161.5,2503.44 v2(221.37,2503.44) v2@222.37,2503.44 ; J10.5@161.5,2721.56 v2(221.37,2721.56) v2@222.37,2721.56 ; J12.4@161.5,3003.44 v2(221.37,3003.44) v2@222.37,3003.44 ; J12.5@161.5,3221.56 v2(221.37,3221.56) v2@222.37,3221.56 ; J11.4@161.5,3503.44 v2(221.37,3503.44) v2@222.37,3503.44 ; J11.5@161.5,3721.56 v2(221.37,3721.56) v2@222.37,3721.56 ; J9.4@161.5,4003.44 v2(221.37,4003.44) v2@222.37,4003.44 ; J9.5@161.5,4221.56 v2(221.37,4221.56) v2@222.37,4221.56 ; J34.4@161.5,4503.44 v2(221.37,4503.44) v2@222.37,4503.44 ; J34.5@161.5,4721.56 v2(221.37,4721.56) v2@222.37,4721.56 ; J36.4@161.5,5003.44 v2(221.37,5003.44) v2@222.37,5003.44 ; J36.5@161.5,5221.56 v2(221.37,5221.56) v2@222.37,5221.56 ; J35.4@161.5,5503.44 v2(221.37,5503.44) v2@222.37,5503.44 ; J35.5@161.5,5721.56 v2(221.37,5721.56) v2@222.37,5721.56 ; J33.4@161.5,6003.44 v2(221.37,6003.44) v2@222.37,6003.44 ; J33.5@161.5,6221.56 v2(221.37,6221.56) v2@222.37,6221.56 ; J30.4@161.5,6503.44 v2(221.37,6503.44) v2@222.37,6503.44 ; J30.5@161.5,6721.56 v2(221.37,6721.56) v2@222.37,6721.56 ; J32.4@161.5,7003.44 v2(221.37,7003.44) v2@222.37,7003.44 ; J32.5@161.5,7221.56 v2(221.37,7221.56) v2@222.37,7221.56 ; J31.4@161.5,7503.44 v2(221.37,7503.44) v2@222.37,7503.44 ; J31.5@161.5,7721.56 v2(221.37,7721.56) v2@222.37,7721.56 ; J29.4@161.5,8003.44 v4(221.37,8003.44) v4@222.37,8003.44 ; J29.5@161.5,8221.56 v2(221.37,8221.56) v2@222.37,8221.56 ; v2(580.57,8999.7) 638.44,8999.7 J26.4@638.44,9057.57 ; v2(580.57,9057.57) J26.4@638.44,9057.57 ; v2(580.57,9115.44) 638.44,9115.44 J26.4@638.44,9057.57 ; v2@638.44,8938.63 v2(638.44,8939.63) J26.4@638.44,8999.5 ; v2@856.56,8938.63 v2(856.56,8939.63) J26.5@856.56,8999.5 ; v2(914.43,8999.7) 856.56,8999.7 J26.5@856.56,9057.57 ; v2(914.43,9057.57) J26.5@856.56,9057.57 ; v2(914.43,9115.44) 856.56,9115.44 J26.5@856.56,9057.57 ; v2(1080.57,8999.7) 1138.44,8999.7 J28.4@1138.44,9057.57 ; v2(1080.57,9057.57) J28.4@1138.44,9057.57 ; v2(1080.57,9115.44) 1138.44,9115.44 J28.4@1138.44,9057.57 ; v2@1138.44,8938.63 v2(1138.44,8939.63) J28.4@1138.44,8999.5 ; v2@1356.56,8938.63 v2(1356.56,8939.63) J28.5@1356.56,8999.5 ; v2(1414.43,8999.7) 1356.56,8999.7 J28.5@1356.56,9057.57 ; v2(1414.43,9057.57) J28.5@1356.56,9057.57 ; v2(1414.43,9115.44) 1356.56,9115.44 J28.5@1356.56,9057.57 ; v2(1580.57,8999.7) 1638.44,8999.7 J27.4@1638.44,9057.57 ; v2(1580.57,9057.57) J27.4@1638.44,9057.57 ; v2(1580.57,9115.44) 1638.44,9115.44 J27.4@1638.44,9057.57 ; v2@1638.44,8938.63 v2(1638.44,8939.63) J27.4@1638.44,8999.5 ; v2@1856.56,8938.63 v2(1856.56,8939.63) J27.5@1856.56,8999.5 ; v2(1914.43,8999.7) 1856.56,8999.7 J27.5@1856.56,9057.57 ; v2(1914.43,9057.57) J27.5@1856.56,9057.57 ; v2(1914.43,9115.44) 1856.56,9115.44 J27.5@1856.56,9057.57 ; v2(2080.57,8999.7) 2138.44,8999.7 J25.4@2138.44,9057.57 ; v2(2080.57,9057.57) J25.4@2138.44,9057.57 ; v2(2080.57,9115.44) 2138.44,9115.44 J25.4@2138.44,9057.57 ; v2@2138.44,8938.63 v2(2138.44,8939.63) J25.4@2138.44,8999.5 ; v2@2356.56,8938.63 v2(2356.56,8939.63) J25.5@2356.56,8999.5 ; v2(2414.43,8999.7) 2356.56,8999.7 J25.5@2356.56,9057.57 ; v2(2414.43,9057.57) J25.5@2356.56,9057.57 ; v2(2414.43,9115.44) 2356.56,9115.44 J25.5@2356.56,9057.57 ; v2(2580.57,8999.7) 2638.44,8999.7 J38.4@2638.44,9057.57 ; v2(2580.57,9057.57) J38.4@2638.44,9057.57 ; v2(2580.57,9115.44) 2638.44,9115.44 J38.4@2638.44,9057.57 ; v2@2638.44,8938.63 v2(2638.44,8939.63) J38.4@2638.44,8999.5 ; v2@2856.56,8938.63 v2(2856.56,8939.63) J38.5@2856.56,8999.5 ; v2(2914.43,8999.7) 2856.56,8999.7 J38.5@2856.56,9057.57 ; v2(2914.43,9057.57) J38.5@2856.56,9057.57 ; v2(2914.43,9115.44) 2856.56,9115.44 J38.5@2856.56,9057.57 ; v2(3080.57,8999.7) 3138.44,8999.7 J40.4@3138.44,9057.57 ; v2(3080.57,9057.57) J40.4@3138.44,9057.57 ; v2(3080.57,9115.44) 3138.44,9115.44 J40.4@3138.44,9057.57 ; v2@3138.44,8938.63 v2(3138.44,8939.63) J40.4@3138.44,8999.5 ; v2@3356.56,8938.63 v2(3356.56,8939.63) J40.5@3356.56,8999.5 ; v2(3414.43,8999.7) 3356.56,8999.7 J40.5@3356.56,9057.57 ; v2(3414.43,9057.57) J40.5@3356.56,9057.57 ; v2(3414.43,9115.44) 3356.56,9115.44 J40.5@3356.56,9057.57 ; v2(3580.57,8999.7) 3638.44,8999.7 J39.4@3638.44,9057.57 ; v2(3580.57,9057.57) J39.4@3638.44,9057.57 ; v2(3580.57,9115.44) 3638.44,9115.44 J39.4@3638.44,9057.57 ; v2@3638.44,8938.63 v2(3638.44,8939.63) J39.4@3638.44,8999.5 ; C85.2@3672.72,2454 v3(3672.72,2505) ; C84.2@3839.05,3873.81 v3(3839.05,3921.95) ; v2@3856.56,8938.63 v2(3856.56,8939.63) J39.5@3856.56,8999.5 ; v2(3914.43,8999.7) 3856.56,8999.7 J39.5@3856.56,9057.57 ; v2(3914.43,9057.57) J39.5@3856.56,9057.57 ; v2(3914.43,9115.44) 3856.56,9115.44 J39.5@3856.56,9057.57 ; Y4.2@3932.95,3519.25 v3(4048.75,3519.25) ; v2(4080.57,8999.7) 4138.44,8999.7 J37.4@4138.44,9057.57 ; v2(4080.57,9057.57) J37.4@4138.44,9057.57 ; v2(4080.57,9115.44) 4138.44,9115.44 J37.4@4138.44,9057.57 ; C86.2@4081.38,3690.79 v3(4127.79,3690.79) ; v2@4138.44,8938.63 v2(4138.44,8939.63) J37.4@4138.44,8999.5 ; v2@4356.56,8938.63 v2(4356.56,8939.63) J37.5@4356.56,8999.5 ; v2(4414.43,8999.7) 4356.56,8999.7 J37.5@4356.56,9057.57 ; v2(4414.43,9057.57) J37.5@4356.56,9057.57 ; v2(4414.43,9115.44) 4356.56,9115.44 J37.5@4356.56,9057.57 ; Y5.7@4515.56,3306.88 v3(4515.56,3404.44) ; v2(4580.57,8999.7) 4638.44,8999.7 J6.4@4638.44,9057.57 ; v2(4580.57,9057.57) J6.4@4638.44,9057.57 ; v2(4580.57,9115.44) 4638.44,9115.44 J6.4@4638.44,9057.57 ; v2@4638.44,8938.63 v2(4638.44,8939.63) J6.4@4638.44,8999.5 ; v2@4856.56,8938.63 v2(4856.56,8939.63) J6.5@4856.56,8999.5 ; v2(4914.43,8999.7) 4856.56,8999.7 J6.5@4856.56,9057.57 ; v2(4914.43,9057.57) J6.5@4856.56,9057.57 ; v2(4914.43,9115.44) 4856.56,9115.44 J6.5@4856.56,9057.57 ; v2(5080.57,8999.7) 5138.44,8999.7 J7.4@5138.44,9057.57 ; v2(5080.57,9057.57) J7.4@5138.44,9057.57 ; v2(5080.57,9115.44) 5138.44,9115.44 J7.4@5138.44,9057.57 ; v2@5138.44,8938.63 v2(5138.44,8939.63) J7.4@5138.44,8999.5 ; v2@5356.56,8938.63 v2(5356.56,8939.63) J7.5@5356.56,8999.5 ; v2(5414.43,8999.7) 5356.56,8999.7 J7.5@5356.56,9057.57 ; v2(5414.43,9057.57) J7.5@5356.56,9057.57 ; v2(5414.43,9115.44) 5356.56,9115.44 J7.5@5356.56,9057.57 ; v2(5580.57,8999.7) 5638.44,8999.7 J5.4@5638.44,9057.57 ; v2(5580.57,9057.57) J5.4@5638.44,9057.57 ; v2(5580.57,9115.44) 5638.44,9115.44 J5.4@5638.44,9057.57 ; v2@5638.44,8938.63 v2(5638.44,8939.63) J5.4@5638.44,8999.5 ; v2@5856.56,8938.63 v2(5856.56,8939.63) J5.5@5856.56,8999.5 ; v2(5914.43,8999.7) 5856.56,8999.7 J5.5@5856.56,9057.57 ; v2(5914.43,9057.57) J5.5@5856.56,9057.57 ; v2(5914.43,9115.44) 5856.56,9115.44 J5.5@5856.56,9057.57 ; v2(6080.57,8999.7) 6138.44,8999.7 J4.4@6138.44,9057.57 ; v2(6080.57,9057.57) J4.4@6138.44,9057.57 ; v2(6080.57,9115.44) 6138.44,9115.44 J4.4@6138.44,9057.57 ; v2@6138.44,8938.63 v2(6138.44,8939.63) J4.4@6138.44,8999.5 ; v2@6356.56,8938.63 v2(6356.56,8939.63) J4.5@6356.56,8999.5 ; v2(6414.43,8999.7) 6356.56,8999.7 J4.5@6356.56,9057.57 ; v2(6414.43,9057.57) J4.5@6356.56,9057.57 ; v2(6414.43,9115.44) 6356.56,9115.44 J4.5@6356.56,9057.57 ; v2@6775.63,1380.94 v2(6778.63,1380.94) J2.5@6836.5,1380.94 ; v2@6776.23,770.94 v2(6778.63,770.94) J3.5@6837.1,770.94 ; v2@6776.23,989.06 v2(6778.63,989.06) J3.4@6837.1,989.06 ; v2(6777.83,2503.44) J13.5@6838.7,2503.44 ; v2(6777.83,2721.56) J13.4@6838.7,2721.56 ; v2(6777.83,3003.44) J15.5@6838.7,3003.44 ; v2(6777.83,3221.56) J15.4@6838.7,3221.56 ; v2(6777.83,3503.44) J16.5@6838.7,3503.44 ; v2(6777.83,3721.56) J16.4@6838.7,3721.56 ; v2(6777.83,4003.44) J14.5@6838.7,4003.44 ; v2(6777.83,4221.56) J14.4@6838.7,4221.56 ; v2(6777.83,4503.44) J18.5@6838.7,4503.44 ; v2(6777.83,4721.56) J18.4@6838.7,4721.56 ; v2(6777.83,5003.44) J20.5@6838.7,5003.44 ; v2(6777.83,5221.56) J20.4@6838.7,5221.56 ; v2(6777.83,5503.44) J19.5@6838.7,5503.44 ; v2(6777.83,5721.56) J19.4@6838.7,5721.56 ; v2(6777.83,6003.44) J17.5@6838.7,6003.44 ; v2(6777.83,6221.56) J17.4@6838.7,6221.56 ; v2(6777.83,6503.44) J21.5@6838.7,6503.44 ; v2(6777.83,6721.56) J21.4@6838.7,6721.56 ; v2(6777.83,7003.44) J23.5@6838.7,7003.44 ; v2(6777.83,7221.56) J23.4@6838.7,7221.56 ; v2(6777.83,7503.44) J24.5@6838.7,7503.44 ; v2(6777.83,7721.56) J24.4@6838.7,7721.56 ; v2(6777.83,8003.44) J22.5@6838.7,8003.44 ; v2(6777.83,8221.56) J22.4@6838.7,8221.56 ; v2(6778.63,1599.06) J2.4@6836.5,1599.06 ; v2(6838.7,1323.07) 6838.7,1380.94 J2.5@6896.57,1380.94 ; v2(6838.7,1656.93) 6838.7,1599.06 J2.4@6896.57,1599.06 ; v2(6838.7,2445.57) J13.5@6838.7,2503.44 ; v2(6838.7,2779.43) J13.4@6838.7,2721.56 ; v2(6838.7,2945.57) J15.5@6838.7,3003.44 ; v2(6838.7,3279.43) J15.4@6838.7,3221.56 ; v2(6838.7,3445.57) J16.5@6838.7,3503.44 ; v2(6838.7,3779.43) J16.4@6838.7,3721.56 ; v2(6838.7,3945.57) J14.5@6838.7,4003.44 ; v2(6838.7,4279.43) J14.4@6838.7,4221.56 ; v2(6838.7,4445.57) J18.5@6838.7,4503.44 ; v2(6838.7,4779.43) J18.4@6838.7,4721.56 ; v2(6838.7,4945.57) J20.5@6838.7,5003.44 ; v2(6838.7,5279.43) J20.4@6838.7,5221.56 ; v2(6838.7,5445.57) J19.5@6838.7,5503.44 ; v2(6838.7,5779.43) J19.4@6838.7,5721.56 ; v2(6838.7,5945.57) J17.5@6838.7,6003.44 ; v2(6838.7,6279.43) J17.4@6838.7,6221.56 ; v2(6838.7,6445.57) J21.5@6838.7,6503.44 ; v2(6838.7,6779.43) J21.4@6838.7,6721.56 ; v2(6838.7,6945.57) J23.5@6838.7,7003.44 ; v2(6838.7,7279.43) J23.4@6838.7,7221.56 ; v2(6838.7,7445.57) J24.5@6838.7,7503.44 ; v2(6838.7,7779.43) J24.4@6838.7,7721.56 ; v2(6838.7,7945.57) J22.5@6838.7,8003.44 ; v2(6838.7,8279.43) J22.4@6838.7,8221.56 ; v2@6839.3,713.07 6839.3,770.94 J3.5@6896.57,770.94 J3.5@6897.17,770.94 ; v2@6839.3,1046.93 6839.3,989.06 J3.4@6896.57,989.06 J3.4@6897.17,989.06 ; v2(6896.57,1323.07) J2.5@6896.57,1380.94 ; v2(6896.57,1656.93) J2.4@6896.57,1599.06 ; v2(6896.57,2445.57) J13.5@6896.57,2503.44 ; v2(6896.57,2779.43) J13.4@6896.57,2721.56 ; v2(6896.57,2945.57) J15.5@6896.57,3003.44 ; v2(6896.57,3279.43) J15.4@6896.57,3221.56 ; v2(6896.57,3445.57) J16.5@6896.57,3503.44 ; v2(6896.57,3779.43) J16.4@6896.57,3721.56 ; v2(6896.57,3945.57) J14.5@6896.57,4003.44 ; v2(6896.57,4279.43) J14.4@6896.57,4221.56 ; v2(6896.57,4445.57) J18.5@6896.57,4503.44 ; v2(6896.57,4779.43) J18.4@6896.57,4721.56 ; v2(6896.57,4945.57) J20.5@6896.57,5003.44 ; v2(6896.57,5279.43) J20.4@6896.57,5221.56 ; v2(6896.57,5445.57) J19.5@6896.57,5503.44 ; v2(6896.57,5779.43) J19.4@6896.57,5721.56 ; v2(6896.57,5945.57) J17.5@6896.57,6003.44 ; v2(6896.57,6279.43) J17.4@6896.57,6221.56 ; v2(6896.57,6445.57) J21.5@6896.57,6503.44 ; v2(6896.57,6779.43) J21.4@6896.57,6721.56 ; v2(6896.57,6945.57) J23.5@6896.57,7003.44 ; v2(6896.57,7279.43) J23.4@6896.57,7221.56 ; v2(6896.57,7445.57) J24.5@6896.57,7503.44 ; v2(6896.57,7779.43) J24.4@6896.57,7721.56 ; v2(6896.57,7945.57) J22.5@6896.57,8003.44 ; v2(6896.57,8279.43) J22.4@6896.57,8221.56 ; v2@6897.17,713.07 J3.5@6897.17,770.94 ; v2@6897.17,1046.93 J3.4@6897.17,989.06 ; v2(6954.44,1323.07) 6954.44,1380.94 J2.5@6896.57,1380.94 ; v2(6954.44,1656.93) 6954.44,1599.06 J2.4@6896.57,1599.06 ; v2(6954.44,2445.57) 6954.44,2503.44 J13.5@6896.57,2503.44 ; v2(6954.44,2779.43) 6954.44,2721.56 J13.4@6896.57,2721.56 ; v2(6954.44,2945.57) 6954.44,3003.44 J15.5@6896.57,3003.44 ; v2(6954.44,3279.43) 6954.44,3221.56 J15.4@6896.57,3221.56 ; v2(6954.44,3445.57) 6954.44,3503.44 J16.5@6896.57,3503.44 ; v2(6954.44,3779.43) 6954.44,3721.56 J16.4@6896.57,3721.56 ; v2(6954.44,3945.57) 6954.44,4003.44 J14.5@6896.57,4003.44 ; v2(6954.44,4279.43) 6954.44,4221.56 J14.4@6896.57,4221.56 ; v2(6954.44,4445.57) 6954.44,4503.44 J18.5@6896.57,4503.44 ; v2(6954.44,4779.43) 6954.44,4721.56 J18.4@6896.57,4721.56 ; v2(6954.44,4945.57) 6954.44,5003.44 J20.5@6896.57,5003.44 ; v2(6954.44,5279.43) 6954.44,5221.56 J20.4@6896.57,5221.56 ; v2(6954.44,5445.57) 6954.44,5503.44 J19.5@6896.57,5503.44 ; v2(6954.44,5779.43) 6954.44,5721.56 J19.4@6896.57,5721.56 ; v2(6954.44,5945.57) 6954.44,6003.44 J17.5@6896.57,6003.44 ; v2(6954.44,6279.43) 6954.44,6221.56 J17.4@6896.57,6221.56 ; v2(6954.44,6445.57) 6954.44,6503.44 J21.5@6896.57,6503.44 ; v2(6954.44,6779.43) 6954.44,6721.56 J21.4@6896.57,6721.56 ; v2(6954.44,6945.57) 6954.44,7003.44 J23.5@6896.57,7003.44 ; v2(6954.44,7279.43) 6954.44,7221.56 J23.4@6896.57,7221.56 ; v2(6954.44,7445.57) 6954.44,7503.44 J24.5@6896.57,7503.44 ; v2(6954.44,7779.43) 6954.44,7721.56 J24.4@6896.57,7721.56 ; v2(6954.44,7945.57) 6954.44,8003.44 J22.5@6896.57,8003.44 ; v2(6954.44,8279.43) 6954.44,8221.56 J22.4@6896.57,8221.56 ; v2@6955.04,713.07 6955.04,770.94 J3.5@6897.17,770.94 ; v2@6955.04,1046.93 6955.04,989.06 J3.4@6897.17,989.06 ; J13.5@6838.7,2503.44 J13.5@6896.57,2503.44 ; J13.4@6838.7,2721.56 J13.4@6896.57,2721.56 ; J15.5@6838.7,3003.44 J15.5@6896.57,3003.44 ; J15.4@6838.7,3221.56 J15.4@6896.57,3221.56 ; J16.5@6838.7,3503.44 J16.5@6896.57,3503.44 ; J16.4@6838.7,3721.56 J16.4@6896.57,3721.56 ; J14.5@6838.7,4003.44 J14.5@6896.57,4003.44 ; J14.4@6838.7,4221.56 J14.4@6896.57,4221.56 ; J18.5@6838.7,4503.44 J18.5@6896.57,4503.44 ; J18.4@6838.7,4721.56 J18.4@6896.57,4721.56 ; J20.5@6838.7,5003.44 J20.5@6896.57,5003.44 ; J20.4@6838.7,5221.56 J20.4@6896.57,5221.56 ; J19.5@6838.7,5503.44 J19.5@6896.57,5503.44 ; J19.4@6838.7,5721.56 J19.4@6896.57,5721.56 ; J17.5@6838.7,6003.44 J17.5@6896.57,6003.44 ; J17.4@6838.7,6221.56 J17.4@6896.57,6221.56 ; J21.5@6838.7,6503.44 J21.5@6896.57,6503.44 ; J21.4@6838.7,6721.56 J21.4@6896.57,6721.56 ; J23.5@6838.7,7003.44 J23.5@6896.57,7003.44 ; J23.4@6838.7,7221.56 J23.4@6896.57,7221.56 ; J24.5@6838.7,7503.44 J24.5@6896.57,7503.44 ; J24.4@6838.7,7721.56 J24.4@6896.57,7721.56 ; J22.5@6838.7,8003.44 J22.5@6896.57,8003.44 ; J22.4@6838.7,8221.56 J22.4@6896.57,8221.56
  L8-Bottom Layer (GBL) w30: C9.2@6195.2,1970.9 6195.2,2000.4 6221.2,2026.4 v4(6256.2,2026.4) ; v4(6627.2,1972.4) C8.2@6627.2,2008.9 ; 780.5,8723.67 ccw(c747.5,8723.67) 780.5,8723.67 ; v5@1280.5,8723.67 ccw(c1247.5,8723.67) v5@1280.5,8723.67 ; 1780.5,8723.67 ccw(c1747.5,8723.67) 1780.5,8723.67 ; v5@2280.5,8723.67 ccw(c2247.5,8723.67) v5@2280.5,8723.67 ; 2780.5,8723.67 ccw(c2747.5,8723.67) 2780.5,8723.67 ; 2861.3,5677.02 ccw(c2884.64,5653.69) 2907.97,5630.35 2939.08,5661.47 ccw(c2915.75,5684.8) 2892.42,5708.13 2861.3,5677.02 ; 2977.46,5731.87 ccw(c3000.79,5708.54) 3024.12,5685.21 3055.24,5716.32 ccw(c3031.9,5739.65) 3008.57,5762.99 2977.46,5731.87 ; v5@3280.5,8723.67 ccw(c3247.5,8723.67) v5@3280.5,8723.67 ; 3284.39,5782.49 cw(c3284.39,5815.49) 3284.39,5848.49 3328.39,5848.49 cw(c3328.39,5815.49) 3328.39,5782.49 3284.39,5782.49 ; 3400.59,5894.67 cw(c3400.59,5927.67) 3400.59,5960.67 3444.59,5960.67 cw(c3444.59,5927.67) 3444.59,5894.67 3400.59,5894.67 ; 3780.5,8723.67 ccw(c3747.5,8723.67) 3780.5,8723.67 ; 3869.84,5464.22 ccw(c3902.84,5464.22) 3935.84,5464.22 3935.84,5508.22 ccw(c3902.84,5508.22) 3869.84,5508.22 3869.84,5464.22 ; 3965.89,5309.45 ccw(c3998.89,5309.45) 4031.89,5309.45 4031.89,5353.45 ccw(c3998.89,5353.45) 3965.89,5353.45 3965.89,5309.45 ; v5@4280.5,8723.67 ccw(c4247.5,8723.67) v5@4280.5,8723.67 ; 6593.67,4612.5 ccw(c6560.67,4612.5) 6593.67,4612.5 ; 6593.67,5112.5 ccw(c6560.67,5112.5) 6593.67,5112.5 ; 6593.67,5612.5 ccw(c6560.67,5612.5) 6593.67,5612.5 ; 6593.67,6112.5 ccw(c6560.67,6112.5) 6593.67,6112.5
  L8-Bottom Layer (GBL) w40: C23.2@4946,2975.5 v3(4999.5,2975.5) ; C22.2@5200,2995.5 v3@5281,2995.48 ; C2.2@5956.7,1801.4 v4(6017.2,1801.4) ; C1.2@6191.2,2269.9 v4(6257.54,2270.72)
  other v1: 365.34,2559.29 6640.59,2559.48 245.4,2563.18 485.27,2563.17 6520.65,2563.17 6760.53,2563.18 6413.35,2616.9 591.59,2618.83 447.04,2661.82 6550.98,2661.82 327.1,2665.71 6670.92,2665.71 6328.49,2701.75 676.44,2703.68 552.44,2719.19 6447.38,2722.38 6243.64,2786.6 761.29,2788.53 881.26,2791.17 1001.26,2791.17 1121.26,2791.17 5791.67,2791.17 6123.73,2791.17 5671.67,2791.55 637.29,2804.04 6362.53,2807.23 1238.83,2815.24 6007.27,2820.11 5907.16,2823.75 5578.31,2866.94 1323.61,2900.17 634.24,2924 6371.64,2926.88 5961.18,2930.91 880.18,2933.82 1000.18,2933.82 1120.18,2933.82 5731.59,2933.82 6203,2933.82 760.24,2937.52 5493.46,2951.79 6476.58,2985.09 6101.49,2997.82 1220.77,2999.26 6303.95,2998.7 1381.57,3005.24 5638.02,3008.96 551.52,3010.94 5814.75,3020.33 5408.61,3036.64 701.23,3042 323.55,3059.29 443.49,3063.17 6567.7,3063.17 1453.67,3072.23 6391.88,3080.36 6026.02,3091.12 5553.17,3093.81 1151.01,3096.9 5906.22,3098 603.85,3112.13 1343.12,3118.91 5323.75,3121.5 1556.93,3133.37 6480.63,3161.13 494.62,3161.82 6720.61,3161.82 6600.62,3162.72 254.7,3163.87 374.69,3165.71 5468.32,3178.67 1145.01,3216.75 1641.8,3218.2 1437.11,3226.86 5383.46,3263.52 1726.68,3303.03 1227.81,3303.62 1527.48,3305.82 1347.76,3306.96 3559,3318 3677,3347 5298.61,3348.37 5069.19,3376.06 1811.55,3387.86 1612.35,3390.65 3602,3400 3631,3428 4984.34,3460.91 1896.42,3472.69 1697.23,3475.48 1225.16,3539.62 5977.46,3543.17 4899.49,3545.76 1981.3,3557.52 6679.88,3559.47 356.85,3559.55 1782.1,3560.31 236.9,3563.18 476.79,3563.17 6559.94,3563.17 6095.47,3564.93 1108.53,3567.87 6441.68,3583.56 1333.98,3590.2 5872.73,3601.75 5044.05,3602.93 585.89,3613.14 4814.64,3630.61 2066.17,3642.35 1866.98,3645.14 450.93,3661.82 331,3665.71 6498.42,3666.34 6618.41,3665.71 6356.83,3668.41 6150.82,3671.4 1061.6,3678.32 4959.2,3687.78 670.75,3697.99 1204.24,3703.04 1359.24,3707.51 4729.78,3715.47 5853.18,3720.15 554.93,3721.69 2151.05,3727.18 1951.85,3729.97 6413.56,3751.19 6271.98,3753.27 5995.82,3764.83 4874.35,3772.64 755.6,3782.84 875.31,3791.17 1445.27,3791.17 1565.27,3791.17 1685.27,3791.17 1805.27,3791.17 5111.11,3791.17 5351.11,3791.17 5471.11,3791.17 5591.11,3791.17 5711.11,3791.17 6158.12,3791.17 1061.6,3798.32 4644.93,3800.32 4992.07,3806.35 639.79,3806.54 2235.92,3812.02 993.35,3812.76 2036.73,3814.8 1204.24,3823.04 1918.15,3831.89 6328.71,3836.05 5853.18,3840.15 4789.5,3857.49 5995.82,3884.83 4907.25,3891.23 2320.8,3896.85 2121.6,3899.63 2003,3916.74 1061.6,3918.32 1286.75,3920.5 659.44,3924.92 808.26,3933.82 1406.01,3933.82 1526.01,3933.82 1646.01,3933.82 1766.01,3933.82 5091.25,3933.82 5331.25,3933.82 5451.25,3933.82 5571.25,3933.82 5691.25,3933.82 6137.87,3933.82 4704.64,3942.34 1204.24,3943.04 6382.88,3943.12 6255.87,3955.62 5853.18,3960.15 4822.43,3976.11 2405.67,3981.68 2206.48,3984.46 1872.89,3988.37 2087.86,4001.59 906.6,4002.6 4994.85,4005.28 5995.82,4004.83 719.43,4014.5 595.15,4026.24 4619.79,4027.2 1061.6,4038.32 6435.65,4050.9 5698.18,4053.62 370.62,4059.29 6316.05,4059.44 6674.78,4059.29 4737.6,4060.99 1203.94,4063.04 6554.89,4064.37 2490.55,4066.51 2291.35,4069.29 1957.75,4073.22 488.57,4081.39 2172.71,4086.45 4909.98,4090.12 4534.94,4112.05 655.14,4115.82 923.25,4121.44 5976.28,4123.23 4652.78,4145.87 6395.03,4149.79 2376.23,4154.13 2042.6,4158.07 5753.55,4160.08 6749.32,4161.82 325.29,4165.71 6629.38,4165.71 1143.78,4166.87 2257.56,4171.3 444.98,4174.33 4825.12,4174.96 5871.56,4181.82 6510.54,4182.32 1025.14,4184.83 563.47,4193.27 4450.08,4196.9 4567.95,4230.75 2660.3,4236.17 2461.1,4238.96 2127.45,4242.93 2342.41,4256.15 4740.25,4259.8 4365.23,4281.75 4483.13,4315.64 2745.17,4321 2212.3,4327.78 2427.27,4341.01 4655.38,4344.64 4280.38,4366.61 2630.85,4408.62 2297.16,4412.63 2715.72,4493.45 2382.01,4497.48 2596.97,4510.71 4110.67,4536.31 306.82,4561.37 426.8,4563.17 6713.18,4563.18 5706.79,4564.7 5957.88,4564.61 6473.26,4567.64 4228.65,4570.28 546.31,4574.07 2999.8,4575.49 5589.14,4588.32 6075.42,4588.78 1090.19,4597.31 1210.19,4596.74 1402.7,4596.55 1522.7,4597.5 4400.78,4599.15 4025.82,4621.16 5854.39,4625.35 6383.06,4646.78 4143.83,4655.16 631.42,4658.66 3084.67,4660.32 410.61,4661.82 2551.72,4667.18 1317.82,4681.38 2670.86,4681.57 1007.07,4683.87 1605.38,4684.48 4315.91,4683.99 526.44,4693.19 5540.42,4697.99 6123.58,4698.69 5974.58,4702.63 6457.31,4702.86 3940.97,4706.02 5676.58,4707.38 6298.2,4731.63 3717.68,4739.42 4059,4740.04 716.27,4743.52 5838.42,4744.28 4231.04,4768.83 611.29,4778.04 6372.45,4787.71 826.4,4791.17 1660.29,4791.17 1780.29,4791.17 1900.29,4791.17 2020.29,4791.17 2140.29,4791.17 3859.03,4793.69 4989.01,4794.42 5109.01,4794.42 5349.01,4794.42 5469.01,4794.42 6195.94,4794.42 1144.95,4796.18 1312.31,4801.25 1002.31,4803.77 1454.95,4809.14 2865.99,4813.79 943.03,4819.43 5974.58,4822.63 3974.18,4824.92 5675.28,4827.37 4877.6,4839.01 4146.18,4853.67 2236.96,4862.28 696.15,4862.9 5838.42,4864.28 6306.29,4887.82 1519.79,4910.12 3889.35,4909.8 1144.95,4916.18 6057.64,4919.71 1312.31,4921.25 5601.18,4921.76 1002.31,4923.77 4792.75,4923.87 1454.95,4929.14 5001.5,4930.58 5121.5,4930.58 5361.5,4930.58 5481.5,4930.58 6177.15,4930.58 818.17,4933.82 1637.43,4933.82 1757.43,4933.82 1877.43,4933.82 1997.43,4933.82 5974.58,4942.63 2116.99,4944.05 2321.81,4947.13 5689.42,4946.69 614.76,4951.08 5838.42,4984.28 2675.79,4984.66 2795.79,4984.66 6371.63,4988.47 712.87,4991.37 4905.97,5003.19 4707.89,5008.72 6265.07,5012.24 3976.44,5023.34 2201.84,5028.9 1141.59,5036.14 531.6,5037.59 854.24,5048.27 1447.83,5048.93 6466.56,5061.88 5972.3,5062.6 414.6,5064.28 3619.72,5067.13 5692.43,5066.65 629.71,5077.88 4623.04,5093.57 6349.93,5097.09 2286.82,5113.64 1062.21,5126.13 1239.44,5125.94 1566.04,5127.46 1686.04,5127.46 1806.04,5127.46 1926.04,5127.46 2046.04,5127.46 2166.04,5127.46 2646.03,5127.3 2766.03,5127.3 942.26,5129.83 1359.37,5130.02 5893.96,5153.5 6455.67,5153.82 5773.97,5154.69 1450.04,5158.2 303.99,5162.46 543.98,5161.85 6695.25,5161.95 423.99,5163.34 4736.26,5172.9 4538.19,5178.42 3526.24,5188.31 1365.19,5243.06 4651.41,5257.75 4453.33,5263.28 1651.81,5270.03 1771.81,5269.96 1891.81,5269.9 2011.81,5269.83 2131.81,5269.76 2251.81,5269.7 3998.89,5270.45 3306.94,5270.64 1532.07,5277.91 1005.5,5325.88 1280.34,5327.91 4566.56,5342.61 1447.21,5362.77 898.22,5379.65 1112.02,5381.14 2234.57,5388.45 3998.89,5392.45 4102.37,5418.14 4222.37,5418.14 4342.37,5418.14 4462.37,5418.14 4582.37,5418.14 3902.84,5425.22 1230.87,5437.24 2149.72,5473.3 1431.86,5481.78 846.2,5487.79 4782.32,5536.93 1053.12,5541.45 1290.01,5541.66 3902.84,5547.21 5699.44,5549.79 5935.3,5549.72 2064.86,5558.16 326.82,5559.29 6643.57,5559.87 446.75,5563.17 6763.52,5563.18 4098,5567.62 4338,5567.56 4458,5567.53 4578,5567.52 5580.88,5568.31 6053.78,5568.78 1492.39,5585.39 563.54,5590.78 903.28,5593.35 6414.27,5615.57 5835.76,5616.74 4867.18,5621.78 1137.97,5626.3 2857.06,5626.11 4672.38,5641.63 1980.01,5643.01 486.12,5661.82 366.18,5665.71 6668.78,5665.71 3728.34,5672.05 5525.42,5674.73 648.39,5675.63 6108.58,5675.54 988.14,5678.2 2973.21,5680.96 2338.83,5683.93 1444.8,5695.55 3880.64,5699.04 6329.42,5700.42 4952.03,5706.64 4304.69,5709.44 4424.69,5709.77 1222.82,5711.15 2943.33,5712.38 4544.55,5715.53 6441.62,5718.54 4757.23,5726.48 3777.57,5726.55 1895.16,5727.86 5823.42,5736.1 575.33,5742.08 2724.59,5748.57 1339.59,5753.27 853.12,5755.12 733.24,5760.48 1072.99,5763.05 2253.97,5768.78 5661.58,5773.96 4205.02,5776.26 5959.58,5783.48 6244.57,5785.27 3687.29,5787.05 5036.88,5791.49 5156.85,5794.42 5276.85,5794.42 5396.85,5794.42 5516.85,5794.42 6124.91,5794.42 4629.4,5800.39 6356.77,5803.39 3850,5811 4842.09,5811.33 1810.3,5812.72 3245.4,5815.49 3367.39,5815.49 1273.63,5819.87 660.18,5826.93 2639.74,5833.42 4066.53,5839.51 3675.09,5840.61 3619,5843 2169.12,5853.63 5823.42,5856.1 4289.87,5861.11 2959.81,5876.91 4714.26,5885.24 3763,5888 5631.2,5890.05 4926.94,5896.18 1725.45,5897.57 5959.58,5903.48 3560,5906 1001.73,5911 3238.32,5916.95 2554.89,5918.27 6358.55,5923.38 4151.38,5924.36 1215.5,5924.85 882.61,5925.51 3363.01,5926.26 3483.58,5927.67 3795,5930 5038.25,5930.58 5158.25,5930.58 5278.25,5930.58 5398.25,5930.58 5518.25,5930.58 6120.69,5930.58 3734,5934 6240.58,5935.74 2084.27,5938.49 763.32,5938.54 632.54,5943.71 4374.72,5945.97 3987,5960 2874.95,5961.76 4799.11,5970.09 1105.12,5971.92 4030.36,5974.02 5823.42,5976.1 5011.79,5981.04 1640.6,5982.42 2470.04,6003.13 6443.4,6008.23 4236.23,6009.21 3845.26,6009.79 5674.42,6013.27 6325.43,6020.59 5959.58,6023.48 1800.68,6024.08 2006.33,6029.73 4459.57,6030.82 688.09,6032.03 3911,6032 557.31,6037.19 3238.32,6036.95 3839,6038 2790.1,6046.62 4883.96,6054.94 4115.21,6058.87 6671.73,6059.29 440.63,6065.24 5096.65,6065.89 1555.75,6067.27 4321.09,6094.07 3920.43,6103.33 6410.29,6105.45 1715.82,6108.93 4544.43,6115.67 612.85,6125.51 1863.68,6126.21 5700.8,6130.33 2705.25,6131.47 5926.03,6138.7 4968.82,6139.8 2006.33,6149.73 5181.5,6150.74 1470.89,6152.13 260.01,6161.82 6757.61,6161.82 379.94,6165.71 499.94,6166.15 6637.67,6165.71 2300.33,6172.83 5811.89,6175.73 5378.32,6192.43 1630.97,6193.78 5498.25,6196.55 4629.28,6200.53 2455.86,6209.85 2620.4,6216.32 5053.67,6224.65 4284.92,6228.58 5266.35,6235.6 1386.04,6236.98 1863.68,6246.21 1082.92,6249.67 2215.48,6257.68 4490.79,6263.77 2006.33,6269.73 1546.12,6278.64 967.97,6284.13 5580.64,6283.79 4714.13,6285.38 2371.01,6294.71 5138.52,6309.5 1181.24,6318.47 1301.19,6321.83 2474.93,6328.33 2130.62,6342.54 3959.92,6344.65 4575.65,6348.63 4174.99,6357.89 1461.26,6363.49 1863.68,6366.21 4798.99,6370.23 2286.15,6379.56 901.08,6383.76 2006.33,6389.73 5225.1,6392.6 4454.62,6398.28 5344.48,6404.75 5707.62,6410.49 5587.78,6416.84 1070.51,6426.95 4660.5,6433.48 1376.41,6448.34 2474.93,6448.33 2089.93,6455.42 4883.84,6455.08 2611.08,6455.96 2226.08,6483.44 4539.47,6483.14 1863.68,6486.21 5794.59,6493.17 939.33,6497.5 5500.44,6499.12 5276.63,6503.73 4363.31,6508.71 2006.33,6509.73 1155.37,6511.8 3238.32,6516.95 4745.35,6518.33 1282.48,6523.02 3490.67,6526.91 4095.68,6538.17 4968.69,6539.94 5653.02,6548.27 385.04,6559.62 6613.81,6559.51 265.1,6563.18 504.99,6563.17 6493.86,6563.08 6733.75,6563.18 2474.93,6568.33 4624.33,6567.99 2089.93,6575.42 2611.08,6575.96 1024.18,6582.35 5415.58,6583.97 1240.22,6596.66 2226.08,6603.44 4830.2,6603.18 1863.68,6606.21 3160.74,6608.5 5218.6,6608.76 5798.07,6613.12 5053.54,6624.79 2006.33,6629.73 6393.94,6629.53 603.89,6631.13 3547.18,6632.77 5568.17,6633.12 3322.26,6639.53 4709.18,6652.84 4095.68,6658.17 981.26,6659.04 438.73,6661.82 6561.98,6661.78 1109.03,6667.2 4533.02,6678.42 1325.07,6681.51 2474.93,6688.33 4915.06,6688.04 3075.89,6693.36 2089.93,6695.42 2611.08,6695.96 4238.33,6699.77 3424.39,6702.53 5138.4,6709.64 6452.4,6710.7 546.94,6713.69 6309.52,6714.81 688.74,6715.99 5269.5,6717.43 3632.04,6717.62 5483.32,6717.97 2226.08,6723.44 3237.41,6724.39 1863.68,6726.21 5756.41,6725.66 888.21,6734.81 4794.03,6737.7 2006.33,6749.73 1193.88,6752.06 4617.87,6763.27 5598.88,6766.79 5376.27,6772.21 4999.91,6772.89 2991.03,6778.21 4095.68,6778.17 3509.25,6787.38 782.27,6791.17 5856.95,6791.17 5976.95,6791.17 6096.95,6791.17 6216.95,6791.17 1365.96,6794.33 5223.25,6794.5 6367.98,6795.98 631.79,6798.54 2474.93,6808.33 3152.55,6809.24 2089.93,6815.42 2611.08,6815.96 4238.33,6819.77 1790.62,6821.4 4878.89,6822.55 3671.08,6831.1 2226.08,6843.44 4702.72,6848.12 5682.18,6853.16 967.53,6857.23 1955.38,6858.38 5084.76,6857.74 1087.3,6864.67 5308.1,6879.35 2929.42,6881.19 3067.7,6894.09 1300.66,6895.01 4095.68,6898.17 3534.92,6904.6 1705.76,6906.26 4963.74,6907.4 6355.04,6915.28 639.98,6918.26 2469.63,6928.21 2059.37,6931.47 4283.29,6931.03 1186.55,6932.12 5772.32,6932.38 874.85,6933.45 4787.58,6932.98 5892.31,6933.82 6012.31,6933.82 6132.31,6933.82 2611.08,6935.96 3723.68,6938.95 755.19,6942.56 1870.53,6943.23 5169.61,6942.59 6251.1,6950.85 2218.42,6963.19 5392.96,6964.2 1620.91,6991.11 5048.59,6992.25 6439.89,7000.13 2929.42,7001.19 555.13,7003.11 4153.72,7003.2 3598.54,7006.36 2384.77,7013.06 3065.58,7014.07 1974.52,7016.32 4368.14,7015.88 4872.43,7017.83 3808.54,7023.8 670.34,7027.42 5254.47,7027.45 1785.67,7028.08 6335.95,7035.7 2550.72,7039.67 2134.46,7048.93 5477.81,7049.05 6781.54,7049.52 331.31,7059.29 6661.93,7059.29 451.24,7063.17 6542,7063.17 1536.06,7075.96 5133.44,7077.11 4238.58,7088.05 3683.39,7091.21 2299.92,7097.92 1889.66,7101.17 4452.99,7100.74 4957.28,7102.68 3893.39,7108.66 585.49,7112.27 5339.32,7112.3 1700.82,7112.93 2929.42,7121.19 6420.81,7120.56 2465.86,7124.52 2049.61,7133.78 3065.58,7134.07 5562.66,7133.91 1451.2,7160.82 236.3,7161.82 476.2,7161.82 5218.3,7161.96 6533.49,7161.82 356.25,7165.37 6653.43,7165.52 6773.32,7170.74 4323.43,7172.91 3768.24,7176.06 2215.07,7182.77 1804.81,7186.03 4537.85,7185.59 5042.14,7187.53 3978.24,7193.51 5424.17,7197.15 1615.97,7197.79 2381.01,7209.38 1964.76,7218.63 5647.51,7218.76 2929.42,7241.19 1366.35,7245.67 5303.15,7246.81 3065.58,7254.07 4408.28,7257.76 3853.1,7260.91 2130.22,7267.62 4622.7,7270.44 1719.96,7270.88 5126.99,7272.39 4060.93,7280.47 5509.03,7282.01 1531.12,7282.64 6097.09,7289.6 2296.16,7294.23 1879.9,7303.49 5732.37,7303.61 6215.91,7306.38 1281.5,7330.52 5388,7331.67 4493.13,7342.61 2045.36,7352.48 3929.42,7353.51 4707.55,7355.29 1635.1,7355.73 5211.84,7357.24 2929.42,7361.19 6004.57,7366.02 1446.26,7367.49 5593.88,7366.86 3065.58,7374.07 2211.3,7379.08 1795.05,7388.34 5817.22,7388.46 6292.42,7398.82 4065.58,7400.38 1196.65,7415.37 5472.86,7416.52 4577.99,7427.46 1960.51,7437.33 4792.41,7440.15 1550.25,7440.59 5296.69,7442.09 5919.71,7450.87 1361.41,7452.34 5678.73,7451.71 2126.45,7463.94 1088.89,7468.18 1710.2,7473.19 3929.42,7473.51 2929.42,7481.19 3065.58,7494.07 5557.71,7501.37 6061.01,7511.31 4662.84,7512.32 978.06,7514.19 6272.51,7517.16 4065.58,7520.38 1465.4,7525.44 4877.26,7525 5381.55,7526.94 1276.56,7537.2 5763.58,7536.56 1929.42,7553.23 1625.34,7558.04 379.35,7559.29 6629.33,7559.29 259.41,7563.18 499.28,7563.17 6509.39,7563.18 6749.26,7563.18 2065.58,7567.35 5642.56,7586.22 3929.42,7593.51 5975.06,7595.06 4747.69,7597.17 2929.42,7601.19 6188.59,7602.94 1380.55,7610.29 4962.11,7609.85 5466.4,7611.8 5856.36,7612.68 3065.58,7614.07 917.38,7617.72 1189.85,7620.15 6404.24,7621 599.76,7628.78 1070.81,7635.3 4065.58,7640.38 1540.49,7642.9 440.98,7661.82 6554.87,7661.83 6674.81,7665.71 5727.41,7671.08 1929.42,7673.23 4832.55,7682.02 2065.58,7687.35 1295.69,7695.14 5046.96,7694.71 5551.25,7696.65 6319.39,7705.86 3929.42,7713.51 6142.48,7713.73 683.08,7715.14 547.63,7716.83 6448.12,7716.64 2929.42,7721.19 5968.16,7723.97 1455.64,7727.75 880.21,7731.81 3065.58,7734.07 1059.04,7754.72 5812.27,7755.93 4065.58,7760.38 4917.4,7766.87 1210.84,7780 5636.11,7781.5 775.92,7791.17 6234.54,7790.71 1929.42,7793.23 6363.27,7801.49 630.96,7803.19 2065.58,7807.35 1370.79,7812.6 5068.63,7812.73 6044,7816.98 2859.94,7819.02 2739.94,7819.98 3929.42,7833.51 3809.51,7837.95 974.19,7839.57 5897.12,7840.78 3064.07,7854.06 3692.09,7862.7 1125.99,7864.85 5720.96,7866.36 4062.59,7880.34 4925.98,7886.57 2643.34,7891.17 1285.93,7897.45 6128.85,7901.83 1929.42,7913.23 6360.84,7921.46 635.13,7923.11 888.79,7923.88 5981.97,7925.63 2065.58,7927.35 5068.63,7932.73 769.21,7933.82 6241.98,7941.85 1041.13,7949.7 5805.81,7951.21 4835.87,7965.82 2870.2,7968.02 2990.2,7968.02 3110.2,7968.02 3230.2,7968.02 3644.71,7972.95 1829.16,7979.17 1201.08,7982.31 3862.56,7986.95 3982.56,7986.95 4102.56,7986.95 4222.56,7986.95 1709.57,7989.07 6445.47,8006.54 550.28,8007.97 2636.3,8010.96 6064.17,8013.06 681.76,8016 3339.24,8018.12 4732.51,8026.79 6326.61,8026.93 956.28,8034.56 5890.66,8036.06 4329.92,8040.55 2053.82,8046.77 5048,8050.95 6671.09,8059.29 443.73,8063.17 6551.16,8063.37 1116.23,8067.16 1637.84,8085.28 3679.94,8087.66 2718.19,8098.68 596.9,8100.85 2838.06,8104.18 2958.06,8104.18 3078.06,8104.18 3198.06,8104.18 6411.24,8112 4950.24,8120.55 5070.24,8120.55 3794.59,8123.11 3914.59,8123.11 4034.59,8123.11 4154.59,8123.11 5190.11,8126.14 1835.69,8128.17 1955.69,8128.82 6068.83,8132.97 3361.71,8136 4715.05,8145.51 5926.18,8150.69 929.42,8151.51 4349.98,8158.86 253.67,8161.82 493.55,8161.82 6520.28,8162.11 6760.17,8161.82 373.61,8165.71 6640.23,8165.57 1065.58,8175.95 2054.17,8197.38 1653.14,8204.3 3939.28,8208.83 5274.76,8211.19 3299.02,8238.33 4779.14,8246.96 3179.94,8253.18 6068.83,8252.97 4284.04,8259.12 5878.89,8260.98 4898.04,8263.19 5018.04,8263.19 1756.96,8264.48 1876.96,8264.33 2929.42,8267.71 929.42,8271.51 4164.75,8272.11 5137.54,8274.14 3065.58,8289.52 5762.63,8290.69 1065.58,8295.95 2065.58,8316.84 3929.42,8328.42 5273.66,8331.19 4065.58,8339.67 4931.9,8364.52 6031.37,8366.97 1929.42,8372.25 2929.42,8387.71 929.42,8391.51 5717.48,8401.88 3076.21,8409.05 5186.52,8413.69 1081.98,8414.82 5921.83,8415.98 2099.19,8432.03 5068.63,8436.08 3887.12,8440.72 4115.82,8448.65 6034.94,8456.05 1858.67,8469.17 1187.7,8471.6 3984.15,8474.01 2850.09,8477.75 848.09,8479.75 2208.71,8481.08 4925.98,8484.38 3161.06,8493.9 2048.38,8511.55 3053.79,8516.95 5750.33,8517.29 1054.86,8518.02 934.97,8523.2 2934.01,8524.16 3802.27,8525.57 1929.6,8528.57 4200.67,8533.51 4081.3,8544.46 1773.82,8554.03 5068.63,8556.08 3899.3,8558.87 5862.99,8558.62 2765.24,8562.6 763.24,8564.6 6068.83,8571.16 1244.47,8577.32 3245.91,8578.75 2260.28,8589.44 2136.97,8592.5 4899.68,8601.46 3138.64,8601.81 1139.71,8602.88 850.12,8608.05 2849.15,8609.01 3717.42,8610.42 1844.74,8613.42 4284.87,8619 4166.15,8629.31 3814.45,8643.72 1701.42,8649.73 5136.38,8655.12 2701.42,8664.23 6145.08,8663.82 701.42,8667.45 4801.89,8671.01 5837.79,8675.95 4950.97,8686.03 5966.58,8686.67 5065.04,8723.29 6076.52,8734.77 5221.23,8739.97 4705.6,8742.63 6229.93,8748.67 4853.18,8755.58 5752.72,8760.58 1695.46,8769.58 5881.72,8771.52 2694.29,8784.01 694.29,8787.24 1300.12,8806.63 5149.89,8808.14 3299.85,8808.72 2194.86,8813.54 6161.37,8819.62 2300.71,8823.64 3194.29,8826.73 1194.29,8828.59 5296.49,8833.44 800.71,8837.25 3695.17,8848.18 6296.82,8848.3 5796.82,8856.33 4296.97,8858.19 4795.1,8860.59 4696.46,8862.28 5698.18,8867.47 1698.18,8889.55 2698.18,8903.95 698.18,8907.18 5198.18,8918 1298.52,8926.62 3300.61,8928.71 2310.84,8943.21 3183.18,8946.21
  other v2: 45.56,2540.45 103.43,2540.45 6896.57,2540.45 6954.44,2540.45 161,2540.75 6839,2540.75 161,2684.25 6839,2684.25 45.56,2684.55 103.43,2684.55 6896.57,2684.55 6954.44,2684.55 45.56,3040.45 103.43,3040.45 6896.57,3040.45 6954.44,3040.45 161,3040.75 6839,3040.75 161,3184.25 6839,3184.25 45.56,3184.55 103.43,3184.55 6896.57,3184.55 6954.44,3184.55 45.56,3540.45 103.43,3540.45 6896.57,3540.45 6954.44,3540.45 161,3540.75 6839,3540.75 161,3684.25 6839,3684.25 45.56,3684.55 103.43,3684.55 6896.57,3684.55 6954.44,3684.55 45.56,4040.45 103.43,4040.45 6896.57,4040.45 6954.44,4040.45 161,4040.75 6839,4040.75 161,4184.25 6839,4184.25 45.56,4184.55 103.43,4184.55 6896.57,4184.55 6954.44,4184.55 45.56,4540.45 103.43,4540.45 6896.57,4540.45 6954.44,4540.45 161,4540.75 6839,4540.75 161,4684.25 6839,4684.25 45.56,4684.55 103.43,4684.55 6896.57,4684.55 6954.44,4684.55 45.56,5040.45 103.43,5040.45 6896.57,5040.45 6954.44,5040.45 161,5040.75 6839,5040.75 161,5184.25 6839,5184.25 45.56,5184.55 103.43,5184.55 6896.57,5184.55 6954.44,5184.55 45.56,5540.45 103.43,5540.45 6896.57,5540.45 6954.44,5540.45 161,5540.75 6839,5540.75 161,5684.25 6839,5684.25 45.56,5684.55 103.43,5684.55 6896.57,5684.55 6954.44,5684.55 45.56,6040.45 103.43,6040.45 6896.57,6040.45 6954.44,6040.45 161,6040.75 6839,6040.75 161,6184.25 6839,6184.25 45.56,6184.55 103.43,6184.55 6896.57,6184.55 6954.44,6184.55 45.56,6540.45 103.43,6540.45 6896.57,6540.45 6954.44,6540.45 161,6540.75 6839,6540.75 161,6684.25 6839,6684.25 45.56,6684.55 103.43,6684.55 6896.57,6684.55 6954.44,6684.55 45.56,7040.45 103.43,7040.45 6896.57,7040.45 6954.44,7040.45 161,7040.75 6839,7040.75 161,7184.25 6839,7184.25 45.56,7184.55 103.43,7184.55 6896.57,7184.55 6954.44,7184.55 45.56,7540.45 103.43,7540.45 6896.57,7540.45 6954.44,7540.45 161,7540.75 6839,7540.75 161,7684.25 6839,7684.25 45.56,7684.55 103.43,7684.55 6896.57,7684.55 6954.44,7684.55 45.56,8040.45 103.43,8040.45 6896.57,8040.45 6954.44,8040.45 161,8040.75 6839,8040.75 161,8184.25 6839,8184.25 45.56,8184.55 103.43,8184.55 6896.57,8184.55 6954.44,8184.55 675.75,9000 819.25,9000 1175.75,9000 1319.25,9000 1675.75,9000 1819.25,9000 2175.75,9000 2319.25,9000 2675.75,9000 2819.25,9000 3175.75,9000 3319.25,9000 3675.75,9000 3819.25,9000 4175.75,9000 4319.25,9000 4675.75,9000 4819.25,9000 5175.75,9000 5319.25,9000 5675.75,9000 5819.25,9000 6175.75,9000 6319.25,9000 675.45,9057.57 819.55,9057.57 1175.45,9057.57 1319.55,9057.57 1675.45,9057.57 1819.55,9057.57 2175.45,9057.57 2319.55,9057.57 2675.45,9057.57 2819.55,9057.57 3175.45,9057.57 3319.55,9057.57 3675.45,9057.57 3819.55,9057.57 4175.45,9057.57 4319.55,9057.57 4675.45,9057.57 4819.55,9057.57 5175.45,9057.57 5319.55,9057.57 5675.45,9057.57 5819.55,9057.57 6175.45,9057.57 6319.55,9057.57 675.45,9115.44 819.55,9115.44 1175.45,9115.44 1319.55,9115.44 1675.45,9115.44 1819.55,9115.44 2175.45,9115.44 2319.55,9115.44 2675.45,9115.44 2819.55,9115.44 3175.45,9115.44 3319.55,9115.44 3675.45,9115.44 3819.55,9115.44 4175.45,9115.44 4319.55,9115.44 4675.45,9115.44 4819.55,9115.44 5175.45,9115.44 5319.55,9115.44 5675.45,9115.44 5819.55,9115.44 6175.45,9115.44 6319.55,9115.44
  other v3: 5156.24,1322.03 5016.76,1329.61 5156.24,1357.03 845.56,1600.29 5340,2599 5112.5,2668.5 5281,2994.98 4150.49,5082.02
  other v4: 6043.54,2263.72 3523.37,3598.98 3434.65,3599.56
  other v5: 6560.67,4573.5 6560.67,5151.49 6560.67,5573.5 6560.67,6151.49 708.51,8723.67 1286.5,8723.67 1708.51,8723.67 2286.5,8723.67 2708.51,8723.67 3286.5,8723.67 3708.51,8723.67 4286.5,8723.67 5309,8942 5685,8942 5810,8942 4810,8943 6310,8943 6184,8945
  other v6: 6392.2,1882.19 6350.86,1931.4 6392.2,1931.4 6433.54,1931.4 6392.2,1980.61 5970.95,1994.06 5921.73,2035.4 5970.95,2035.4 6020.16,2035.4 5970.95,2076.74 5075.06,2784.28 5033.72,2833.49 5075.06,2833.49 5116.4,2833.49 5075.06,2882.7 3412.87,5333.66 3459.72,5333.66 3506.57,5333.66 3553.43,5333.66 3369.96,5376.57 3412.87,5376.57 3459.72,5376.57 3506.57,5376.57 3553.43,5376.57 3596.34,5376.57 3369.96,5423.43 3412.87,5423.43 3459.72,5423.43 3506.57,5423.43 3553.43,5423.43 3596.34,5423.43 3369.96,5470.28 3412.87,5470.28 3459.72,5470.28 3506.57,5470.28 3553.43,5470.28 3596.34,5470.28 3369.96,5517.13 3412.87,5517.13 3459.72,5517.13 3506.57,5517.13 3553.43,5517.13 3596.34,5517.13 3412.87,5560.04 3459.72,5560.04 3506.57,5560.04 3553.43,5560.04
  other v7: 1218.71,175.77 1327.71,176.77 1742,448 1362.71,846.85
  other v8: 5477.36,822.3 6150.8,954.4 6149.7,1039.5 6291.8,1115.2 6317.1,1145.6 6317.1,1188.9 6317.1,1238.7 6316.1,1437.9 6291.2,1606.9
IN0_N: R31.2 U1.35 | length 241.5
  L1-Top Layer (GTL) w8: U1.35@3591.42,5620.08 3591.42,5635.89 3593.26,5637.73 3593.26,5649.07 3706.78,5762.59 3706.78,5796.53
  L1-Top Layer (GTL) w11: 3706.78,5796.53 R31.2@3719.02,5808.77
IN0_P: R27.2 U1.34 | length 228.4
  L1-Top Layer (GTL) w8: U1.34@3611.1,5620.08 3611.1,5635.89 3609.26,5637.73 3609.26,5642.45 3718.2,5751.39 3752.14,5751.39
  L1-Top Layer (GTL) w11: 3752.14,5751.39 R27.2@3764.38,5763.63
IN1_N: R38.2 U1.38 | length 320.1
  L1-Top Layer (GTL) w8: U1.38@3532.36,5620.08 3532.36,5635.89 3530.52,5637.73 3530.52,5695.52 3550,5715 3550,5754 3584.69,5788.69 3584.69,5856.21 3594.76,5866.29 3625.51,5866.29 R38.2@3636.69,5877.47
IN1_P: R34.2 U1.39 | length 332.5
  L1-Top Layer (GTL) w8: U1.39@3512.68,5620.08 3512.68,5635.89 3514.52,5637.73 3514.52,5702.15 3534,5721.63 3534,5760.63 3568.69,5795.31 3568.69,5862.84 3582.81,5876.96 3582.81,5907.71 R34.2@3593.99,5918.89
IN2_N: R130.1 U1.43 | length 218.3
  L1-Top Layer (GTL) w8: R130.1@3411,5827.32 3411,5811.5 3421,5801.5 3421,5769.37 3435.78,5754.59 3435.78,5637.73 3433.94,5635.89 U1.43@3433.94,5620.08
IN2_P: R126.1 U1.42 | length 218.3
  L1-Top Layer (GTL) w8: R126.1@3447,5827.32 3447,5811.5 3437,5801.5 3437,5776 3451.78,5761.22 3451.78,5637.73 3453.62,5635.89 U1.42@3453.62,5620.08
IN3_N: R142.2 R143.1 R193.1 U1.45 | length 4494.9
  L1-Top Layer (GTL) w8: 3314.39,5800.98 3314.39,5770.61 3390.88,5694.12 3390.88,5630.85 3394.57,5627.17 U1.45@3394.57,5620.08 ; 3314.39,5801.49 v9(3328.39,5815.49)
  L1-Top Layer (GTL) w11: v5(3247.5,8723.67) R142.2@3247.5,8780 ; v9@3328.39,5816.49 R143.1@3328.39,5840.05
  L6-Mid-Layer 5 (G4) w5: v5(3247.5,8723.67) 3247.5,8645.5 3019.5,8417.5 3019.5,8284.1 3019.5,8237.25 ccw(c3049.65,8237.25) 3049.65,8207.1 3241.56,8207.1 cw(c3241.56,8132.95) 3315.71,8132.95 3315.71,8088.25 cw(c3241.56,8088.25) 3241.56,8014.1 2753.44,8014.1 ccw(c2753.44,7983.95) 2723.29,7983.95 2723.29,7939.25 ccw(c2753.44,7939.25) 2753.44,7909.1 2945.35,7909.1 cw(c2945.35,7834.95) 3019.5,7834.95 3019.5,7768.35 3019.5,6877.13 3328.39,6568.24 v9(3328.39,5815.49)
IN3_P: R138.1 R139.2 R193.2 U1.46 | length 4493.4
  L1-Top Layer (GTL) w8: v9(3284.39,5815.49) 3298.39,5801.49 ; 3298.39,5802 3298.39,5763.98 3374.88,5687.49 U1.46@3374.88,5620.08
  L1-Top Layer (GTL) w11: v5(2747.5,8723.67) R139.2@2747.5,8780 ; v9@3284.39,5816.49 R138.1@3284.39,5840.05
  L6-Mid-Layer 5 (G4) w5: v5(2747.5,8723.67) 2747.5,8645.5 2975.5,8417.5 2975.5,8284.1 2975.5,8237.25 ccw(c3049.65,8237.25) 3049.65,8163.1 3241.56,8163.1 cw(c3241.56,8132.95) 3271.71,8132.95 3271.71,8088.25 cw(c3241.56,8088.25) 3241.56,8058.1 2753.44,8058.1 ccw(c2753.44,7983.95) 2679.29,7983.95 2679.29,7939.25 ccw(c2753.44,7939.25) 2753.44,7865.1 2945.35,7865.1 cw(c2945.35,7834.95) 2975.5,7834.95 2975.5,7768.35 2975.5,6858.9 3284.39,6550.01 v9@3284.39,5816.49
LDO1: C2.1 JP1.3 U10.10 U10.11 U10.12 | length 1539.8
  L1-Top Layer (GTL) w60: JP1.3@5408,978 5787,978 v15(5893.7,1084.7)
  L8-Bottom Layer (GBL) w10: 5890.2,1932.4 5891.3,1933.5 5921.73,1933.5 U10.12@5921.73,1960.6 ; 5920.42,1932.18 5941.42,1932.18 U10.11@5941.42,1960.6 ; 5943.3,1930.3 5961.1,1930.3 U10.10@5961.1,1960.6
  L8-Bottom Layer (GBL) w60: v15(5893.7,1084.7) 5924.55,1115.55 5924.55,1632.05 5893.7,1662.9 C2.1@5893.7,1801.4 5895.2,1912.4
LDO2: C9.1 JP2.3 U11.10 U11.11 U11.12 | length 1191
  L1-Top Layer (GTL) w50: JP2.3@5489,1539.3 v11(5986.55,1539.3)
  L8-Bottom Layer (GBL) w10: C9.1@6195.2,1907.9 C9.1@6212.7,1907.9 ; 6283.04,1959.61 6283.04,1941.24 U11.10@6317.4,1941.24 ; U11.11@6317.4,1960.93 6281.73,1960.93 6282.2,1961.4 6282.2,1980.61 U11.12@6317.4,1980.61
  L8-Bottom Layer (GBL) w45: C9.1@6204.2,1906.4 6267.2,1951.4
  L8-Bottom Layer (GBL) w50: v11(5986.55,1539.3) 6195.2,1747.95 C9.1@6195.2,1907.9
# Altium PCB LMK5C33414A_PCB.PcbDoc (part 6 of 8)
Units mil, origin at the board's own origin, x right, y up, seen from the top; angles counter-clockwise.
Board outline 7000 x 9161 mil, 8 copper layers (L1-Top Layer (GTL), L2-GND Plane (GP1), L3-Mid-Layer 2 (G1), L4-Mid-Layer 3 (G2), L5-Mid-Layer 4 (G3), L6-Mid-Layer 5 (G4), L7-Mid-Layer 6 (G5), L8-Bottom Layer (GBL)), stack 61.2 mil thick; 521 components, 286 nets, 1393 pads, 2202 vias.

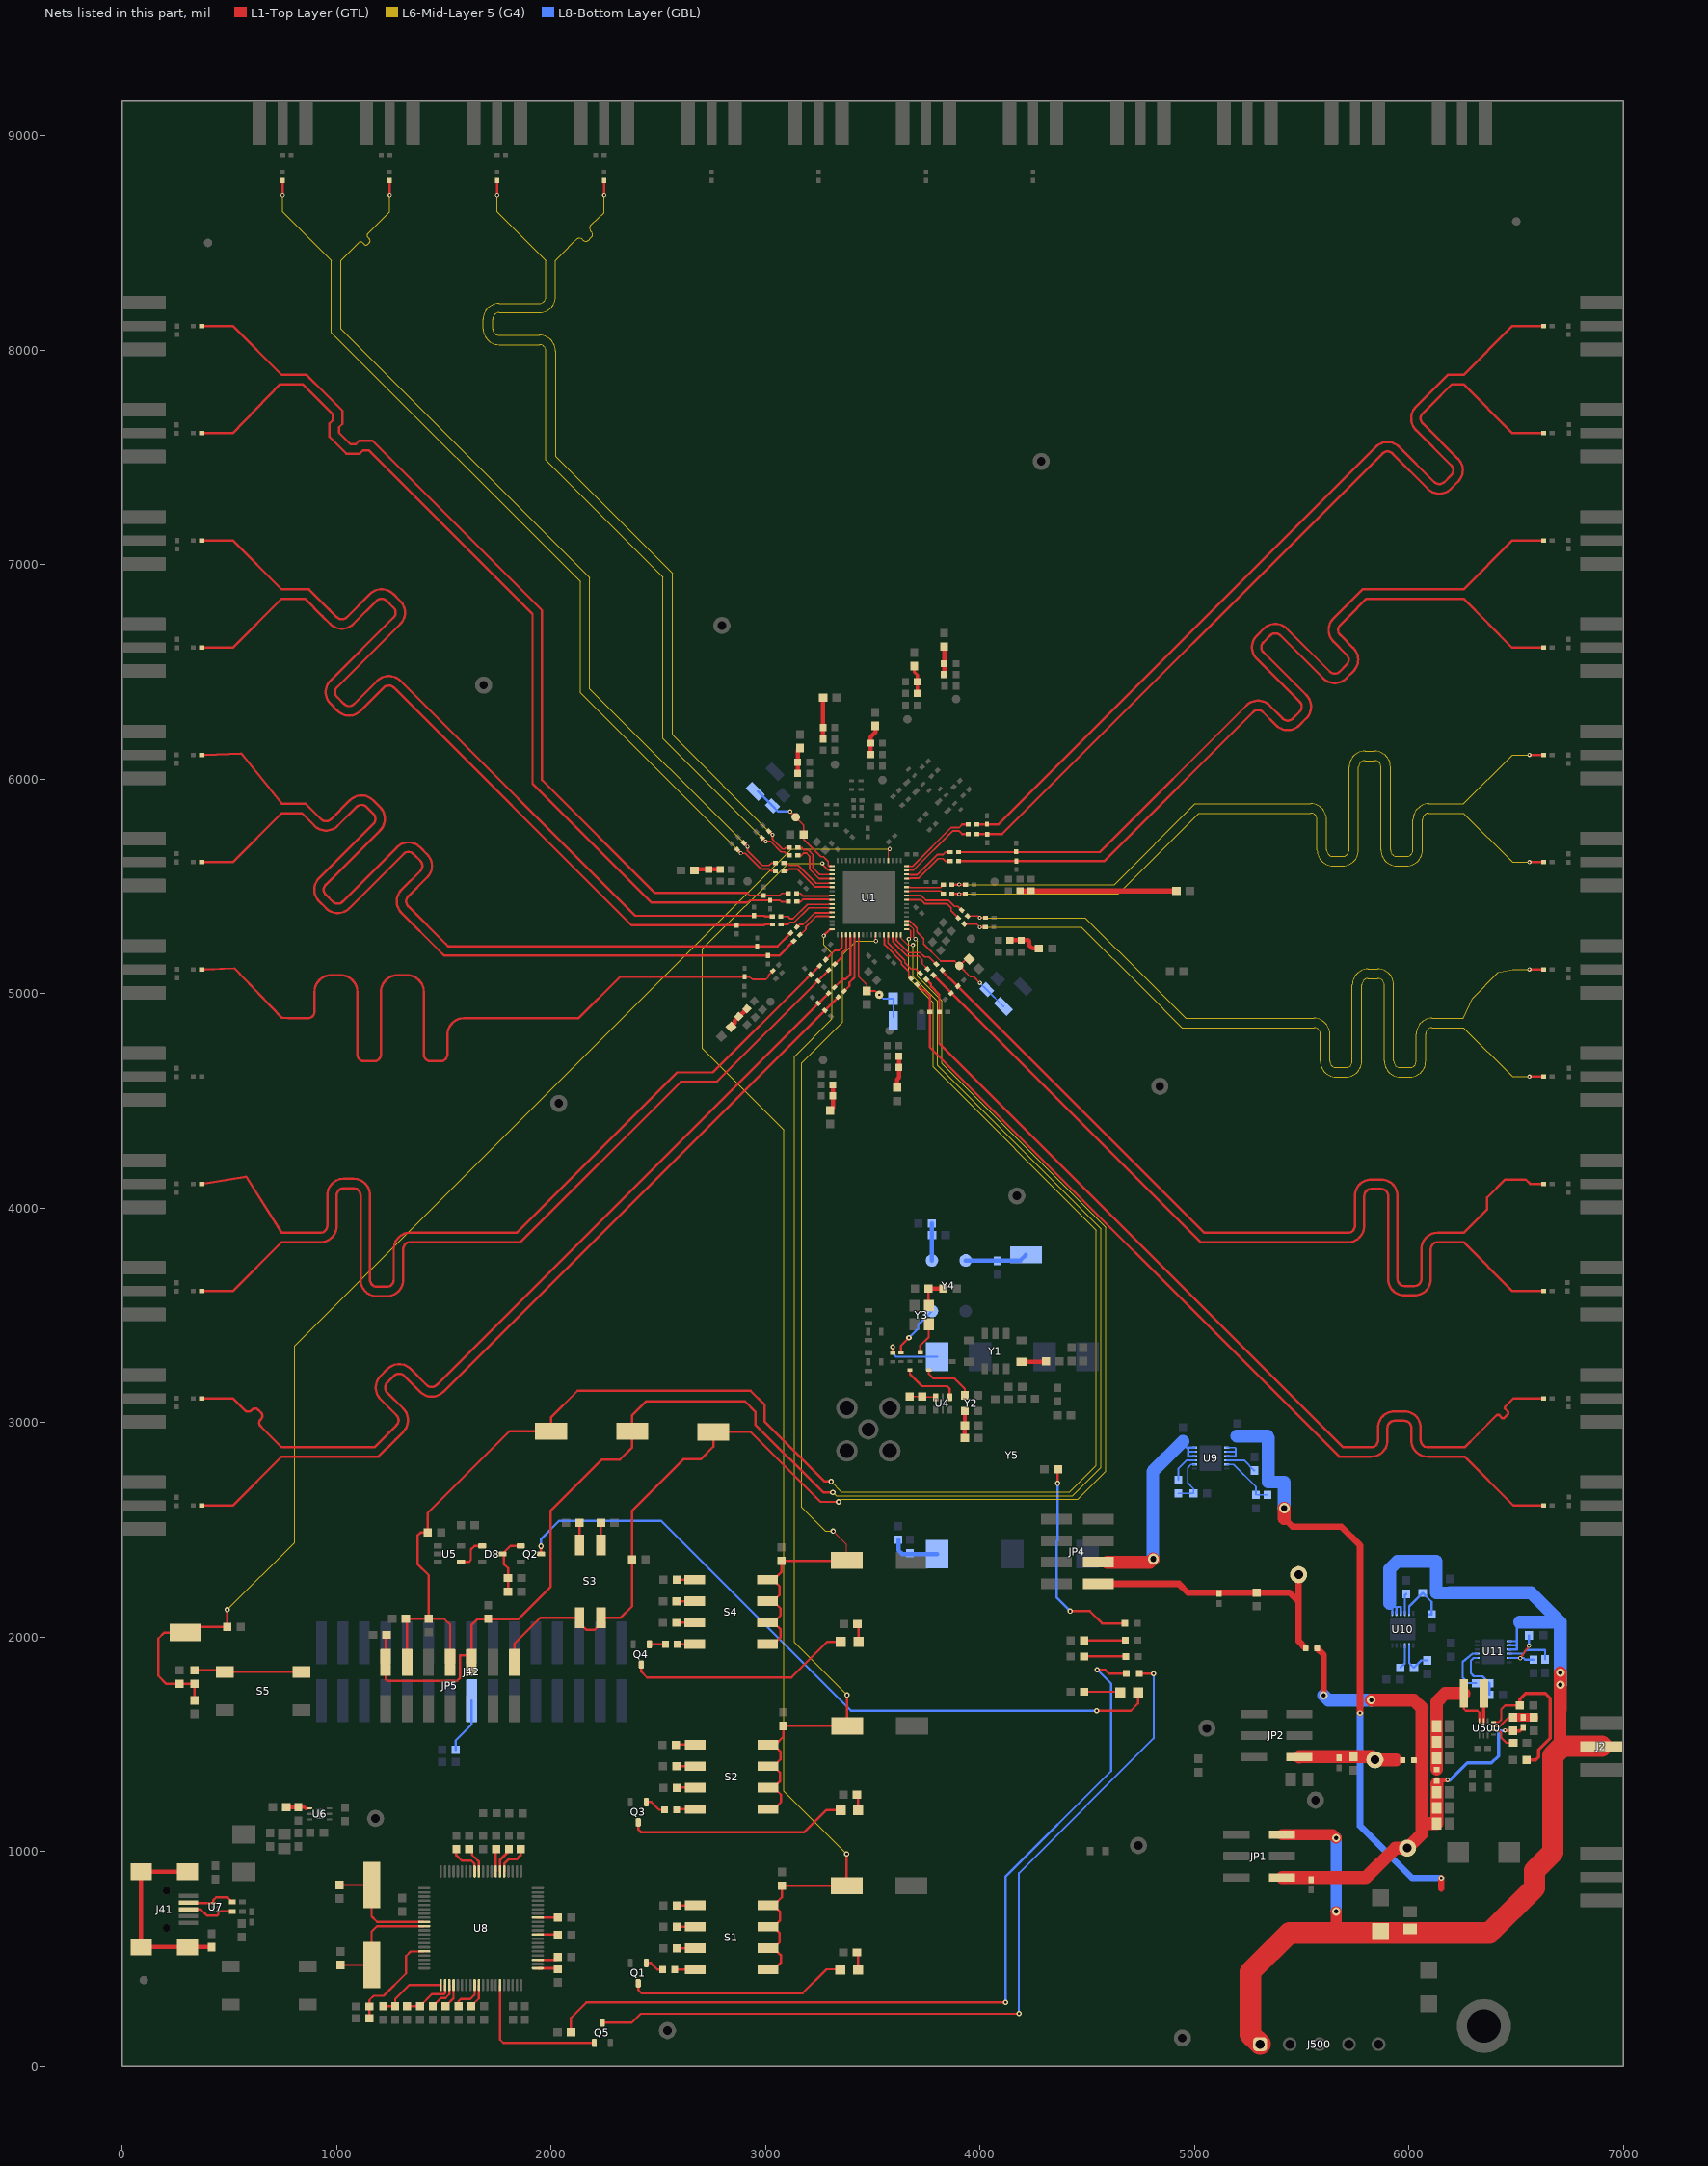
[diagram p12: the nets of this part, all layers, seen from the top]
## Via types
v1: diameter 20, hole 10, L1-Top Layer (GTL) to L8-Bottom Layer (GBL), tented top, 1246 vias
v2: diameter 30, hole 12, L1-Top Layer (GTL) to L8-Bottom Layer (GBL), 519 vias
v3: diameter 25, hole 12, L1-Top Layer (GTL) to L8-Bottom Layer (GBL), tented top, 172 vias
v4: diameter 30, hole 12, L1-Top Layer (GTL) to L8-Bottom Layer (GBL), tented top, 57 vias
v5: diameter 20, hole 10, L1-Top Layer (GTL) to L8-Bottom Layer (GBL), 48 vias
v6: diameter 19.68, hole 7.87, L1-Top Layer (GTL) to L8-Bottom Layer (GBL), 47 vias
v7: diameter 25, hole 10, L1-Top Layer (GTL) to L8-Bottom Layer (GBL), tented top, 35 vias
v8: diameter 25, hole 12, L1-Top Layer (GTL) to L8-Bottom Layer (GBL), 24 vias
v9: diameter 18, hole 10, L1-Top Layer (GTL) to L8-Bottom Layer (GBL), tented top, 12 vias
v10: diameter 30, hole 10, L1-Top Layer (GTL) to L8-Bottom Layer (GBL), 10 vias
v11: diameter 40, hole 20, L1-Top Layer (GTL) to L8-Bottom Layer (GBL), 10 vias
v12: diameter 39.37, hole 19.68, L1-Top Layer (GTL) to L8-Bottom Layer (GBL), tented top, 6 vias
v13: diameter 25, hole 10, L1-Top Layer (GTL) to L8-Bottom Layer (GBL), 5 vias
v14: diameter 23, hole 10, L1-Top Layer (GTL) to L8-Bottom Layer (GBL), tented top, 4 vias
v15: diameter 50, hole 28, L1-Top Layer (GTL) to L8-Bottom Layer (GBL), 4 vias
v16: diameter 20/0/0/0/0/0/20 (per signal layer), hole 10, L1-Top Layer (GTL) to L8-Bottom Layer (GBL), tented top, 2 vias
v17: diameter 25, hole 12, L1-Top Layer (GTL) to L8-Bottom Layer (GBL), tented both sides, 1 vias

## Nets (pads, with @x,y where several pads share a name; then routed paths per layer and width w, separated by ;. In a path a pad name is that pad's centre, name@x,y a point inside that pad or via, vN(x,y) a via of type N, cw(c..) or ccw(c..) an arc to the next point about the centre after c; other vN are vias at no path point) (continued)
LDO3: C23.1 JP4.3 U9.10 U9.11 U9.12 | length 1006.9
  L1-Top Layer (GTL) w60: JP4.3@4593.28,2347.6 4791.1,2347.6 v15(4807.1,2363.6)
  L8-Bottom Layer (GBL) w10: C23.1@4933,2911.5 4939,2905.5 4965.5,2879 4970,2879 ; U9.10@5000.26,2843.33 4970.33,2843.33 4970,2843.66 4970,2863 ; U9.11@5000.26,2863.02 4970.02,2863.02 ; U9.12@5000.26,2882.7 4973.7,2882.7 4970,2879 ; 4970,2863 4970,2879
  L8-Bottom Layer (GBL) w60: v15(4807.1,2363.6) 4804.96,2365.74 4804.96,2771.46 4939,2905.5 C23.1@4946,2912.5
LDO3_IN: C1.1 C8.1 C10.1 C22.1 D1.1 J2.1 J500.1 JP1.5 R201.1 R202.1 R203.1 U9.1 U9.2 U9.3 U10.1 U10.2 U10.3 U11.1 U11.2 U11.3 | length 8840.7
  L1-Top Layer (GTL) w30: 5418,2553 5456.8,2514.2 5684.6,2514.2 5771.58,2427.22 v8(5771.58,1645.42) ; 6150.14,827.24 v3(6150.14,875.54)
  L1-Top Layer (GTL) w50: JP1.5@5408,1078 5644.5,1078 v11(5660.2,1062.3) ; 5660.2,623.9 v11(5660.2,720.5)
  L1-Top Layer (GTL) w60: 5418,2553 v15(5418,2601) ; 6704,1471.9 v11(6705.7,1833.4)
  L1-Top Layer (GTL) w100: J500.1@5305.7,101.2 5260,146.9 5260,437.53 5442.65,620.18 6375.18,620.18 6585,830 6585,910.4 6670.81,996.21 6670.81,1445.8 6715.01,1490 J2.1@6896.57,1490 J2.1@6897.17,1490
  L8-Bottom Layer (GBL) w8: U9.3@5149.87,2843.33 5192.33,2843.33 5192.33,2879.33 5188.96,2882.7 U9.1@5149.87,2882.7 ; U9.2@5149.87,2863.02 5191.35,2863.02
  L8-Bottom Layer (GBL) w10: 5899.67,2139.93 5921.73,2139.93 ; U10.1@5921.73,2110.2 5921.73,2139.93 ; U10.2@5941.42,2110.2 5941.42,2140.18 5941.2,2140.4 5922.2,2140.4 5921.73,2139.93 ; 5942.1,2139.5 5961.1,2139.5 U10.3@5961.1,2110.2 ; U11.3@6467,1941.24 6503.2,1941.4 6503.2,1961.4 ; U11.2@6467,1960.93 6503.2,1961.4 ; U11.1@6467,1980.61 6503.2,1980.4 ; 6503.2,2069.4 6503.2,1980.4 ; 6503.2,1961.4 6503.2,1980.4
  L8-Bottom Layer (GBL) w30: v8(5771.58,1645.42) 5771.58,1119.34 6015.38,875.54 v3(6150.14,875.54)
  L8-Bottom Layer (GBL) w50: v11(5660.2,720.5) v11(5660.2,1062.3)
  L8-Bottom Layer (GBL) w60: C22.1@5197.5,2936.5 5340,2936.5 5340,2932.5 ; 5343.5,2929.01 5343.5,2722 5418,2722 v15(5418,2601) ; 5910.2,2157.4 5910.2,2316.33 5945.77,2351.9 6126.7,2351.9 R201.1@6126.7,2205.4 C1.1@6189.7,2205.4 ; C1.1@6191.2,2206.9 6568.7,2206.9 6705.7,2069.9 ; 6515.2,2069.4 6559.21,2069.68 6594.2,2069.9 6705.7,2069.9 ; v11(6705.7,1776.9) v11(6705.7,1833.4) 6705.7,2069.9
LF1: C67.1 C68.2 C69.1 TP27.1 U1.6 | length 501
  L1-Top Layer (GTL) w7: U1.6@3433.94,5273.62 3433.94,5078.74 3471.84,5040.84 C67.1@3471.84,5011.92 3512.03,5011.92 v1(3529.53,4994.42)
  L8-Bottom Layer (GBL) w7: v1(3529.53,4994.42) 3547.85,4976.1 C68.2@3594.92,4976.1 C69.1@3594.92,4890.43
LF2: C72.1 C73.2 C74.1 TP28.1 U1.19 | length 700.6
  L1-Top Layer (GTL) w8: U1.19@3656.38,5338.58 3671.42,5338.58 3705.54,5304.46 3705.54,5286.65 3736.59,5255.6 3736.59,5231.18 3816.32,5151.45 3881.02,5151.45 TP28.1@3903.24,5129.23 ; C72.1@3949.03,5160.07 3934.08,5160.07 TP28.1@3903.24,5129.23 ; v1(3998.59,5049.9) 3969.65,5078.84 3953.63,5078.84 TP28.1@3903.24,5129.23
  L8-Bottom Layer (GBL) w8: v1(3998.59,5049.9) 4030.86,5017.63 C74.1@4108.53,4939.96
LF3: C75.1 C76.2 C77.1 TP29.1 U1.49 | length 538.7
  L1-Top Layer (GTL) w8: TP29.1@3140.18,5822.1 3177.27,5785.01 C75.1@3177.27,5741.54 3177.27,5718.77 3258.4,5637.64 3268.38,5637.64 3291.53,5614.49 3291.53,5597.6 3294.64,5594.49 U1.49@3309.92,5594.49
  L1-Top Layer (GTL) w11: v1(3114.06,5848.22) TP29.1@3140.18,5822.1
  L8-Bottom Layer (GBL) w11: C77.1@2964.04,5942.43 C76.2@3031.45,5875.02 3058.25,5848.22 v1(3114.06,5848.22)
LMKGPIO0: C88.1 S1.5 S1.6 S1.7 S1.8 TP31.1 U1.50 | length 6324
  L1-Top Layer (GTL) w8: v1(3263.86,5607.21) 3263.86,5601.97 3291.03,5574.8 U1.50@3309.92,5574.8
  L1-Top Layer (GTL) w11: S1.5@3010.2,448.55 3037.94,448.55 3070.7,481.31 3070.7,515.81 3037.96,548.55 S1.6@3036.94,548.55 ; S1.6@3010.2,548.55 S1.6@3036.94,548.55 ; S1.7@3010.2,648.55 S1.7@3035.96,648.55 ; S1.8@3010.2,748.55 S1.8@3035.96,748.55 ; S1.8@3036.7,748.55 S1.8@3035.96,748.55 ; S1.8@3038.1,748.55 3076.1,786.55 C88.1@3076.1,837.5 ; C88.1@3076,840.5 TP31.1@3377.5,840.5 ; TP31.1@3378,840 v3(3378,988) ; S1.7@3035.96,648.55 3065.7,618.81 3065.7,577.31 S1.6@3036.94,548.55 ; S1.7@3035.96,648.55 3036.44,648.55 3067.7,679.81 3067.7,716.81 S1.8@3035.96,748.55
  L6-Mid-Layer 5 (G4) w5: v1(3263.86,5607.21) 3105.21,5607.21 2706,5208 2706,4743 3085,4364 3085,1281 v3(3378,988)
LMKGPIO1: C91.1 S2.5 S2.6 S2.7 S2.8 TP33.1 U1.64 | length 4813.5
  L1-Top Layer (GTL) w11: S2.5@3010.8,1197.55 3038.54,1197.55 3071.3,1230.31 3071.3,1264.81 3038.55,1297.55 S2.6@3037.54,1297.55 ; S2.6@3010.8,1297.55 S2.6@3037.54,1297.55 ; S2.7@3010.8,1397.55 S2.7@3036.55,1397.55 ; S2.8@3010.8,1497.55 S2.8@3036.55,1497.55 ; S2.8@3037.3,1497.55 S2.8@3036.55,1497.55 ; S2.8@3044.9,1497.55 3082.9,1535.55 C91.1@3082.9,1586.5 ; C91.1@3083,1585.5 3379.5,1585.5 3380,1586.01 v3(3380,1729) ; v16(3270.9,5269.61) 3300.5,5299.21 U1.64@3309.92,5299.21 ; S2.7@3036.55,1397.55 3037.04,1397.55 3068.3,1428.81 3068.3,1465.81 S2.8@3036.55,1497.55 ; S2.7@3036.55,1397.55 3066.3,1367.81 3066.3,1326.31 S2.6@3037.54,1297.55
  L6-Mid-Layer 5 (G4) w5: v16(3270.9,5269.61) 3270.9,5226.1 3310,5187 3310,4882 3134,4706 3134,1975 v3(3380,1729)
LMKGPIO2: C95.1 S4.5 S4.6 S4.7 S4.8 TP38.1 U1.10 | length 4120.1
  L1-Top Layer (GTL) w5: v3(3315,2493) 3378,2430 TP38.1@3378,2357
  L1-Top Layer (GTL) w7: U1.10@3512.68,5273.62 3512.68,5246.1 v1(3514.43,5244.35)
  L1-Top Layer (GTL) w11: S4.5@3008.39,1966.55 3037.39,1966.55 3069.89,1999.05 3069.89,2033.55 3036.89,2066.55 S4.6@3035.89,2066.55 ; S4.6@3008.39,2066.55 S4.6@3035.89,2066.55 ; S4.7@3008.39,2166.55 S4.7@3035.39,2166.55 ; S4.8@3008.39,2266.55 S4.8@3034.89,2266.55 ; C95.1@3074,2354.5 C95.1@3074.29,2354.5 ; TP38.1@3375.5,2354.5 C95.1@3074.29,2354.5 ; S4.8@3034.89,2266.55 3064.89,2236.55 3064.89,2195.55 3035.89,2166.55 S4.7@3035.39,2166.55 ; S4.8@3034.89,2266.55 3036.29,2266.55 3074.29,2304.55 C95.1@3074.29,2354.5 ; S4.7@3035.39,2166.55 3069.89,2132.05 3069.89,2100.55 S4.6@3035.89,2066.55
  L6-Mid-Layer 5 (G4) w5: v3(3315,2493) 3279,2493 3169,2603 3169,4675 3360,4866 3360,5182 3422.35,5244.35 v1(3514.43,5244.35)
LMKPDN: C96.1 R75.2 R76.2 R77.1 TP40.1 U1.36 | length 6009.8
  L1-Top Layer (GTL) w5: U1.36@3571.73,5620.08 3571.73,5667.14 v1(3578.17,5673.58)
  L1-Top Layer (GTL) w11: R76.2@337.14,1704.22 R77.1@337.14,1781.22 R75.2@267.14,1781.22 205.78,1781.22 168,1819 168,1993 195.61,2020.61 TP40.1@294.81,2020.61 321.45,2047.25 C96.1@489.66,2047.25 v3(489.66,2126.66)
  L6-Mid-Layer 5 (G4) w5: v3(489.66,2126.66) 804,2441 804,3357 3120.58,5673.58 v1(3578.17,5673.58)
LMKSCK: C92.1 JP5.B02 JP5.B04 R60.1 R61.1 TP34.1 U1.17 | length 7708.3
  L1-Top Layer (GTL) w7: U1.17@3656.38,5299.21 3670.48,5299.21 3676.32,5293.37 3676.32,5262.45 v1(3667.74,5253.87)
  L1-Top Layer (GTL) w10: C92.1@1429.04,2085.18 1500.82,2085.18 1528.36,2057.64 JP5.B04@1528.36,1880.88
  L1-Top Layer (GTL) w11: JP5.B02@1328.36,1880.88 1328.36,2079.14 1334.4,2085.18 C92.1@1429.04,2085.18 1429.04,2286.96 1378,2338 1378,2474 1390.9,2486.9 R61.1@1423.91,2486.9 1423.91,2576.91 1806,2959 TP34.1@2000,2959 2000,3025 2123,3148 2929,3148 2996,3081 2996,3003 3274.5,2724.5 v3(3304.5,2724.5) ; R60.1@1332.11,2090.66 R60.1@1332.69,2091.24
  L6-Mid-Layer 5 (G4) w5: v3(3304.5,2724.5) 3353,2676 4418,2676 4542,2800 4542,3897 3782,4657 3782,4958 3667.74,5072.26 v1(3667.74,5253.87)
LMKSCS_ADD: C94.1 JP5.B07 S3.1 S3.2 TP37.1 U1.18 | length 6768.3
  L1-Top Layer (GTL) w7: U1.18@3656.38,5318.9 3670.6,5318.9 3690.32,5299.17 3690.32,5262 v1(3698.69,5253.63)
  L1-Top Layer (GTL) w11: JP5.B07@1828.36,1880.88 1828.36,1968.36 1950.22,2090.22 S3.1@2131.76,2090.22 S3.1@2131.76,2065.23 ; S3.1@2131.76,2064.73 S3.1@2131.76,2065.23 ; v3(3340,2630) 3256,2630 2930,2956 TP37.1@2756,2956 2756,2887 2697,2828 2616,2828 2377.5,2589.5 C94.1@2377.5,2361 2377.5,2143.5 2324.22,2090.22 S3.2@2231.76,2090.22 2231.76,2062.73 2201.76,2032.73 2164.26,2032.73 S3.1@2131.76,2065.23
  L6-Mid-Layer 5 (G4) w5: v3(3340,2630) 3352,2642 4455,2642 4586,2773 4586,3910 3823,4673 3823,4965 3707,5081 3707,5245.32 v1(3698.69,5253.63)
LMKSDIO: C93.1 JP5.B01 JP5.B05 R59.1 TP36.1 U1.16 | length 7721.3
  L1-Top Layer (GTL) w5: U1.16@3630.79,5273.62 3630.79,5257.47 3662.62,5225.64 v1(3686.71,5225.64)
  L1-Top Layer (GTL) w11: R59.1@1232.5,2010 1228.36,2005.86 JP5.B01@1228.36,1880.88 1228.36,1802.64 1236,1795 1561,1795 1574,1808 1574,1915 JP5.B05@1628.36,1915 ; JP5.B05@1628.36,1880.88 JP5.B05@1628.36,1915 ; JP5.B05@1630,1915 JP5.B05@1628.36,1915 ; v3(3313,2674) 3268,2674 2952,2990 2952,3050 2903,3099 2443,3099 2378,3034 TP36.1@2378,2959 2378,2884 2321,2827 2236,2827 1998,2589 1998,2234 1847.49,2083.49 1704.79,2083.49 1656.49,2083.49 1628.36,2055.36 JP5.B05@1628.36,1915
  L6-Mid-Layer 5 (G4) w5: v3(3313,2674) 3329,2658 4432,2658 4564,2790 4564,3902 3801,4665 3801,4964 3686.71,5078.29 v1(3686.71,5225.64)
NetC7_1: C7.1 U10.4 | length 93.6
  L8-Bottom Layer (GBL) w10: U10.4@5980.79,2110.2 5981.07,2110.49 5981.07,2174.02 5980.79,2174.3 5980.79,2194.49 C7.1@5987.2,2200.9
NetC13_1: C13.1 U11.4 | length 217.7
  L8-Bottom Layer (GBL) w10: U11.4@6467,1921.56 6530.2,1921.4 6547.2,1938.4 6634.2,1938.4 C13.1@6634.2,1894.9
NetC24_1: C24.1 U9.4 | length 149.1
  L8-Bottom Layer (GBL) w8: U9.4@5149.87,2823.65 5230.86,2823.65 C24.1@5279,2775.5
NetC28_2: C28.2 FB1.1 R11.1 | length 131.5
  L1-Top Layer (GTL) w20: FB1.1@3832.31,6486.34 C28.2@3832.27,6537.74 ; C28.2@3832.36,6537.83 R11.1@3832.36,6618.01
NetC31_2: C31.2 FB2.1 R12.1 | length 113.9
  L1-Top Layer (GTL) w20: R12.1@2839.03,4844.49 2856.45,4861.91 2856.45,4872.69 FB2.1@2911.97,4928.21
NetC34_2: C34.2 FB3.1 R16.1 | length 119.8
  L1-Top Layer (GTL) w15: R16.1@3693.18,6526.9 3693.18,6498.19 3706.73,6484.64 FB3.1@3706.73,6412.68
NetC37_2: C37.2 FB4.1 R17.1 | length 125.3
  L1-Top Layer (GTL) w20: R17.1@3301.03,4454.67 3313.65,4467.29 FB4.1@3313.65,4573.78 FB4.1@3313.65,4574.78
NetC40_2: C40.2 FB5.1 R18.1 | length 142.9
  L1-Top Layer (GTL) w20: FB5.1@3489.58,6113.87 C40.2@3489.58,6166.96 3489.58,6195.81 3511.08,6217.31 R18.1@3511.08,6247.83
NetC43_2: C43.2 FB6.1 R19.1 | length 730.2
  L1-Top Layer (GTL) w25: FB6.1@4185.81,5478.47 R19.1@4916,5478.47
NetC46_2: C46.2 FB7.1 R20.1 | length 148.7
  L1-Top Layer (GTL) w20: R20.1@3612.65,4561.77 3612.65,4599.65 3621.92,4608.92 C46.2@3621.92,4656.73 FB7.1@3621.92,4706.65
NetC49_2: C49.2 FB8.1 R21.1 | length 124.7
  L1-Top Layer (GTL) w10: R21.1@2667.99,5573.42 R21.1@2673.02,5578.45
  L1-Top Layer (GTL) w20: R21.1@2670,5578.45 FB8.1@2787.53,5578.45
NetC52_2: C52.2 FB9.1 R22.1 | length 162
  L1-Top Layer (GTL) w20: FB9.1@4138.22,5248.23 4191.67,5248.23 4224.77,5248.23 4229,5244 4229,5225 4243.88,5210.12 R22.1@4273.34,5210.12
NetC55_2: C55.2 FB10.1 R24.2 | length 192.5
  L1-Top Layer (GTL) w20: FB10.1@3266.7,6187.54 R24.2@3266.7,6380
NetC58_2: C58.2 FB11.1 R25.1 | length 122.7
  L1-Top Layer (GTL) w11: R25.1@3149.57,6133.77 R25.1@3160.02,6144.22
  L1-Top Layer (GTL) w20: FB11.1@3149.57,6025.89 C58.2@3149.57,6077.89 R25.1@3149.57,6133.77
NetC82_1: C82.1 R207.2 Y2.4 | length 127
  L1-Top Layer (GTL) w20: R207.2@3928.5,2927 3928.5,2985.7 3928.88,2986.07 Y2.4@3928.88,3053.89
NetC83_1: C83.1 R208.2 Y3.4 | length 148.3
  L1-Top Layer (GTL) w10: Y3.4@3759.14,3546 C83.1@3759.14,3624.84
  L1-Top Layer (GTL) w20: C83.1@3759.14,3624.84 R208.2@3828.56,3624.84
NetC84_1: C84.1 R209.2 Y4.4 | length 171.6
  L8-Bottom Layer (GBL) w20: Y4.4@3775.47,3755.47 R209.2@3775.47,3927.03
NetC85_1: C85.1 R210.2 Y5.3 | length 237.3
  L8-Bottom Layer (GBL) w20: R210.2@3619.07,2453.5 3619.07,2404.93 3638.38,2385.62 Y5.3@3799.78,2385.62
NetC86_1: C86.1 TP30.1 Y4.1 | length 291.7
  L8-Bottom Layer (GBL) w20: Y4.1@3932.95,3755.47 4187.67,3755.47 TP30.1@4213.84,3781.64
NetC87_1: C87.1 R211.2 U4.6 | length 122.5
  L1-Top Layer (GTL) w8: R211.2@3671,3120.5 3730.25,3120.5 3732.52,3118.23 U4.6@3792.57,3118.23
NetC90_1: C90.1 D8.3 Q2.1 R62.2 | length 279.6
  L1-Top Layer (GTL) w11: D8.3@1772.65,2386.9 1810.05,2424.3 Q2.1@1858.17,2424.3 ; D8.3@1778.91,2380.65 1778.91,2340.29 1798.55,2320.65 C90.1@1798.55,2275.2 R62.2@1798.55,2210.2
NetC132_2: C132.2 R145.2 U6.4 | length 110.2
  L1-Top Layer (GTL) w10: 856.09,1200.18 U6.4@875.22,1200.18
  L1-Top Layer (GTL) w15: R145.2@821.09,1206.68 849.6,1206.68 856.09,1200.18
  L1-Top Layer (GTL) w20: C132.2@767.16,1206.09 R145.2@820.5,1206.09
NetC135_1: C135.1 U8.69 Y6.1 | length 553
  L1-Top Layer (GTL) w10: C135.1@1012.71,843.35 1162.2,843.35 Y6.1@1162.71,843.86 1162.71,696.85 1188.18,671.38 U8.69@1407.95,671.38
NetC136_1: C136.1 U8.70 Y6.2 | length 559
  L1-Top Layer (GTL) w10: C136.1@1016.21,469.84 Y6.2@1162.71,469.84 1162.71,626.85 1187.55,651.69 U8.70@1407.95,651.69
NetC137_2: C137.2 R161.1 U8.1 | length 328.5
  L1-Top Layer (GTL) w10: C137.2@1217.71,278.35 R161.1@1272.71,278.35 1272.71,311.85 1337.95,377.09 U8.1@1485.7,377.09
NetC138_2: C138.2 R162.1 U8.2 | length 240.9
  L1-Top Layer (GTL) w10: C138.2@1327.71,278.35 R162.1@1387.71,278.35 1443.41,334.05 1500.41,334.05 1505.39,339.03 U8.2@1505.39,377.09
NetC139_1: C139.1 R165.2 U8.76 | length 483.9
  L1-Top Layer (GTL) w10: C139.1@1151.21,220.35 C139.1@1152.71,221.85 R165.2@1152.71,276.85 1152.71,306.85 1172.71,326.85 1218.96,326.85 1322.71,430.6 1322.71,511.85 1344.44,533.58 U8.76@1407.95,533.58
NetC154_1: C154.1 R201.2 U10.5 | length 249.1
  L8-Bottom Layer (GBL) w10: U10.5@6000.47,2110.2 6000.47,2142.17 R201.2@6063.7,2205.4 6105.2,2163.9 C154.1@6105.2,2104.9 C154.1@6095.21,2104.9
NetC155_1: C155.1 R202.2 U11.5 | length 236.5
  L1-Top Layer (GTL) w10: v5(6519.2,1900.4) v5(6559.2,1959.4)
  L8-Bottom Layer (GBL) w10: U11.5@6467,1901.87 6519.19,1902.29 6533.2,1902.4 6541.7,1893.9 C155.1@6580.2,1893.9 ; v5(6559.2,1959.4) R202.2@6559.2,2007.9
NetC156_1: C156.1 R203.2 U9.5 | length 265.4
  L8-Bottom Layer (GBL) w8: U9.5@5149.87,2803.96 5182.04,2803.96 5286,2700 C156.1@5286,2662.5 ; C156.1@5291.32,2662.5 R203.2@5340,2662.5
NetC501_1: C501.1 C502.1 C503.1 L500.1 L501.2 U500.3 | length 644.5
  L1-Top Layer (GTL) w10: L501.2@6255.75,1736.2 6255.75,1665.05 6265.2,1655.6 6318.8,1655.6 6327.97,1646.43 U500.3@6327.97,1608.45
  L1-Top Layer (GTL) w60: L500.1@6128.97,1384.43 C503.1@6128.97,1434.1 C502.1@6128.97,1510.6 C501.1@6128.97,1584.4 6128.97,1696.77 6168.4,1736.2 L501.2@6255.75,1736.2
NetC504_1: C504.1 C508.1 C509.1 C510.1 C511.1 JP1.1 L500.2 L502.1 L503.1 R501.2 TP1.1 | length 2851.6
  L1-Top Layer (GTL) w10: R501.2@6482.9,1564.1 R501.2@6485.1,1561.9
  L1-Top Layer (GTL) w15: v5(6447.4,1564.1) R501.2@6482.9,1564.1 ; R501.2@6485.1,1561.9 6516.93,1561.9 C511.1@6532.6,1577.58
  L1-Top Layer (GTL) w20: L500.2@6129.2,1328.63 6133.57,1333 v5(6179.4,1333)
  L1-Top Layer (GTL) w30: L503.1@5571.47,1947.3 5601.99,1916.79 v11(5601.99,1727.51)
  L1-Top Layer (GTL) w60: JP1.1@5408,878 5798.4,878 5935.9,1015.5 TP1.1@5992.6,1015.5 6059.69,1082.59 6059.69,1668.11 6022.6,1705.2 5823.58,1705.2 v11(5823.58,1705.8) ; 6060.79,1130 C510.1@6128.97,1130 ; C510.1@6129.2,1130.23 L500.2@6129.2,1317.2
  L8-Bottom Layer (GBL) w15: v5(6179.4,1333) 6179.4,1331.5 6191.5,1331.5 6272.4,1412.4 6385,1412.4 6417.6,1445 6417.6,1551.9 6428.37,1562.67 6445.97,1562.67 v5(6447.4,1564.1)
  L8-Bottom Layer (GBL) w60: v11(5601.99,1727.51) v11@5614,1715.5 ; 5623.7,1705.8 v11(5823.58,1705.8)
NetC511_2: C511.2 R501.1 R504.2 U500.9 | length 205
  L1-Top Layer (GTL) w10: U500.9@6393.92,1583.84 6423.68,1583.84 6464.74,1624.9 R501.1@6485.1,1624.9
  L1-Top Layer (GTL) w40: R501.1@6485.1,1624.9 R504.2@6581.9,1624.9
NetC512_1: C512.1 U500.8 | length 130.5
  L1-Top Layer (GTL) w10: U500.8@6393.92,1563.4 U500.8@6393.92,1564.16 6418.94,1564.16 6429.6,1553.5 6429.6,1530.3 6453.6,1506.3 C512.1@6486.1,1506.3
NetC513_1: C513.1 C514.1 JP2.1 L502.2 TP4.1 | length 459.1
  L1-Top Layer (GTL) w60: JP2.1@5488.3,1440 5488.3,1441.93 5826.37,1441.93 TP4.1@5841.1,1427.2 5939.41,1427.2
NetC515_1: C515.1 C516.1 JP4.1 L503.2 TP501.1 | length 1316.6
  L1-Top Layer (GTL) w30: JP4.1@4560.3,2247.6 4927,2247.6 4968.3,2206.3 5442.9,2206.3 5485.4,2163.8 ; TP501.1@5485.4,2290.5 5485.4,2163.8 ; L503.2@5518.33,1947.3 5485.4,1980.23 5485.4,2163.8
NetD3_1: D3.1 R13.2 | length 191.5
  L1-Top Layer (GTL) w11: R13.2@4485.65,1983.98 D3.1@4677.16,1983.98
NetD4_1: D4.1 R14.2 | length 192.8
  L1-Top Layer (GTL) w11: R14.2@4485.65,1909.24 D4.1@4678.48,1909.24
NetD5_1: D5.1 R15.2 | length 968.6
  L1-Top Layer (GTL) w11: v3(4361.6,2715.6) 4361.6,2779.9 R15.2@4362.59,2780.89 ; v3(4420.56,2120.14) 4511.86,2120.14 4569.02,2062.98 D5.1@4675.34,2062.98
  L8-Bottom Layer (GBL) w11: v3(4361.6,2715.6) 4361.6,2450.96 4356.1,2445.46 4356.1,2184.6 v3(4420.56,2120.14)
NetD6_1: D6.1 R54.1 | length 166.5
  L1-Top Layer (GTL) w11: R54.1@4484.86,1744.56 D6.1@4651.33,1744.56
NetD6_2: D6.2 Q2.3 | length 3322.3
  L1-Top Layer (GTL) w11: Q2.3@1952.65,2386.9 v3(1952.65,2423.2) ; v3(4544,1655.78) 4702.78,1655.78 4736.9,1689.9 D6.2@4736.9,1741.67
  L8-Bottom Layer (GBL) w11: v3(1952.65,2423.2) 1952.65,2456.65 2038,2542 2512,2542 3398.22,1655.78 v3(4544,1655.78)
NetD7_1: D7.1 R56.1 | length 81.7
  L1-Top Layer (GTL) w10: R56.1@3425.01,529.08 3431.34,522.75 D7.1@3431.34,450
NetD7_2: D7.2 Q1.3 | length 1026.1
  L1-Top Layer (GTL) w11: Q1.3@2406.08,385.25 2406.08,353.92 2421,339 3172,339 3283,450 D7.2@3348.66,450
NetD8_1: D8.1 U5.4 | length 157.7
  L1-Top Layer (GTL) w11: U5.4@1579.54,2349.5 1615.95,2349.5 1625.41,2358.96 1625.41,2406.9 1642.81,2424.3 D8.1@1678.17,2424.3
NetD9_1: D9.1 R67.1 | length 75.8
  L1-Top Layer (GTL) w11: R67.1@3425.01,1265.08 3431.85,1258.24 D9.1@3431.85,1192.08
NetD9_2: D9.2 Q3.3 | length 1024
  L1-Top Layer (GTL) w11: Q3.3@2406.09,1135.57 2406.09,1101.91 2418,1090 3180,1090 3282.08,1192.08 D9.2@3349.17,1192.08
NetD10_1: D10.1 R74.1 | length 83.8
  L1-Top Layer (GTL) w11: R74.1@3427.51,2059.81 3432.34,2054.98 D10.1@3432.34,1978
NetD10_2: D10.2 Q4.3 | length 1043.4
  L1-Top Layer (GTL) w11: Q4.3@2420.31,1871.56 2420.31,1837.69 2447,1811 3120,1811 3287,1978 D10.2@3349.66,1978
NetD12_1: D12.1 R166.1 | length 4048.8
  L1-Top Layer (GTL) w11: R166.1@2092.5,157 2092.5,224.5 2164,296 v3(4118,296) ; v3(4546,1847) 4583,1847 4601.15,1828.85 D12.1@4682.57,1828.85
  L8-Bottom Layer (GBL) w11: v3(4118,296) 4118,882 4611,1375 4611,1782 v3(4546,1847)
NetD12_2: D12.2 Q5.3 | length 3872.3
  L1-Top Layer (GTL) w10: Q5.3@2238.4,201.56 2375.56,201.56 2417,243 v3@4181,243 ; D12.2@4741.63,1828.85 v3(4809.15,1828.85)
  L8-Bottom Layer (GBL) w10: v3(4181,244) 4181,899 4809.15,1527.15 v3(4809.15,1828.85)
NetJ41_2: J41.2 R144.2 U7.1 | length 232.3
  L1-Top Layer (GTL) w11: J41.2@308.36,761.5 310.17,759.69 U7.1@425.17,759.69 425.17,773.17 438,786 491.38,786 R144.2@512.38,765
NetJ41_3: J41.3 R146.2 U7.4 | length 232.9
  L1-Top Layer (GTL) w11: J41.3@308.36,730 366,730 396,700 441,700 447.81,706.81 U7.4@447.81,720.32 512.06,720.32 R146.2@512.38,720
NetJ41_6: J41.6 J41.7 J41.8 J41.9 R148.1 | length 895.6
  L1-Top Layer (GTL) w20: J41.9@304.43,905.2 J41.8@87.89,905.2 J41.7@87.89,554.8 J41.6@304.43,554.8 414.7,554.8 R148.1@416,553.5
NetJ42_15: J42.15 R212.1 | length 260.8
  L8-Bottom Layer (GBL) w11: R212.1@1554.5,1473 1554.5,1517.5 1629,1592 J42.15@1629,1702.96
NetL501_1: L501.1 U500.2 | length 133.2
  L1-Top Layer (GTL) w15: U500.2@6347.66,1601.56 L501.1@6347.66,1734.8
NetQ1_1: Q1.1 R55.2 | length 89.7
  L1-Top Layer (GTL) w11: Q1.1@2443.48,479.73 2464.27,479.73 2495,449 R55.2@2520.44,449
NetQ3_1: Q3.1 R66.2 | length 100.9
  L1-Top Layer (GTL) w11: Q3.1@2443.49,1230.06 2466.94,1230.06 2503,1194 R66.2@2529.44,1194
NetQ4_1: Q4.1 R73.2 | length 77.3
  L1-Top Layer (GTL) w11: Q4.1@2457.71,1966.04 2457.95,1965.8 R73.2@2534.93,1965.8
NetQ5_1: Q5.1 U8.15 | length 700.6
  L1-Top Layer (GTL) w10: U8.15@1761.29,377.09 1761.34,377.04 1761.34,122.66 1776.92,107.08 Q5.1@2201,107.08
NetR1_1: R1.1 R2.2 U10.8 | length 190.2
  L8-Bottom Layer (GBL) w10: U10.8@6000.47,1960.6 6000.47,1878.62 R1.1@6022.7,1856.4 6057.19,1890.9 R2.2@6085.2,1890.9
NetR1_2: R1.2 U10.9 | length 112.9
  L8-Bottom Layer (GBL) w10: R1.2@5959.7,1856.4 5980.79,1877.49 U10.9@5980.79,1960.6
NetR3_1: R3.1 R5.2 U11.8 | length 252.9
  L8-Bottom Layer (GBL) w10: U11.8@6317.4,1901.87 6300.67,1901.87 6288.2,1889.4 6288.2,1830.4 6302.2,1816.4 6342.7,1816.4 R3.1@6374.7,1784.4 R5.2@6374.7,1730.4
NetR3_2: R3.2 U11.9 | length 226.2
  L8-Bottom Layer (GBL) w10: R3.2@6311.7,1784.4 6276.2,1784.4 6250.2,1810.4 6250.2,1883.4 6296.32,1921.56 U11.9@6317.4,1921.56
NetR8_1: R8.1 R9.2 U9.8 | length 240.8
  L8-Bottom Layer (GBL) w8: R8.1@4924.5,2669 R9.2@4995.5,2669 4995.5,2690.5 4968,2718 4968,2789 4982.96,2803.96 U9.8@5000.26,2803.96
NetR8_2: R8.2 U9.9 | length 143.8
  L8-Bottom Layer (GBL) w8: R8.2@4924,2732.5 4924,2783.38 4964.27,2823.65 U9.9@5000.26,2823.65
NetR46_2: R46.2 Y2.3 | length 244.5
  L1-Top Layer (GTL) w10: R46.2@3760.85,3243.89 3760.85,3226.07 3781.92,3205 3880.46,3205 3928.88,3156.58 Y2.3@3928.88,3126.73
NetR47_2: R47.2 Y3.3 | length 149.5
  L1-Top Layer (GTL) w10: R47.2@3720.85,3324.78 3720.85,3358.85 3760.85,3398.85 Y3.3@3760.78,3457.73
NetR48_2: R48.2 Y4.3 | length 280.7
  L1-Top Layer (GTL) w10: R48.2@3631.08,3324.13 3631.08,3358.08 v7(3668,3395)
  L8-Bottom Layer (GBL) w10: v7(3668,3395) 3711.08,3438.08 3711.08,3454.86 Y4.3@3775.47,3519.25 Y4.3@3749.68,3519.25
NetR49_2: R49.2 Y5.4 | length 273.6
  L1-Top Layer (GTL) w10: R49.2@3592.08,3322.71 v14(3592.08,3352.39)
  L8-Bottom Layer (GBL) w10: v14(3592.08,3352.39) 3592.08,3322.71 3607.91,3306.88 Y5.4@3799.78,3306.88
NetR50_2: R50.2 U4.4 | length 271.6
  L1-Top Layer (GTL) w10: R50.2@3672.76,3244.22 3672.76,3227.36 3672.76,3225.24 3729,3169 3847,3169 3857.53,3158.47 U4.4@3857.53,3118.23
NetR51_2: R51.2 S1.1 | length 84.7
  L1-Top Layer (GTL) w11: R51.2@2586.51,748.55 S1.1@2671.2,748.55
NetR52_2: R52.2 S1.2 | length 84.7
  L1-Top Layer (GTL) w11: R52.2@2586.51,648.55 S1.2@2671.2,648.55
NetR53_2: R53.2 S1.3 | length 84.7
  L1-Top Layer (GTL) w11: R53.2@2586.51,548.55 S1.3@2671.2,548.55
NetR55_1: R55.1 S1.4 | length 98.8
  L1-Top Layer (GTL) w11: R55.1@2572.36,448.55 S1.4@2671.2,448.55
NetR63_2: R63.2 S2.1 | length 84.7
  L1-Top Layer (GTL) w11: R63.2@2587.11,1497.55 S2.1@2671.8,1497.55
NetR64_2: R64.2 S2.2 | length 84.7
  L1-Top Layer (GTL) w11: R64.2@2587.11,1397.55 S2.2@2671.8,1397.55
NetR65_2: R65.2 S2.3 | length 84.7
  L1-Top Layer (GTL) w11: R65.2@2587.11,1297.55 S2.3@2671.8,1297.55
NetR66_1: R66.1 S2.4 | length 96.5
  L1-Top Layer (GTL) w11: R66.1@2575.33,1197.55 S2.4@2671.8,1197.55
NetR68_2: R68.2 S3.4 | length 102.5
  L1-Top Layer (GTL) w11: S3.4@2131.76,2429.2 R68.2@2131.76,2531.71
NetR69_2: R69.2 S3.3 | length 102.5
  L1-Top Layer (GTL) w11: S3.3@2231.76,2429.2 R69.2@2231.76,2531.71
NetR70_2: R70.2 S4.1 | length 84.7
  L1-Top Layer (GTL) w11: R70.2@2584.7,2266.55 R70.2@2585.94,2266.55 S4.1@2669.39,2266.55
NetR71_1: R71.1 S4.2 | length 84.7
  L1-Top Layer (GTL) w11: R71.1@2584.7,2166.55 S4.2@2669.39,2166.55
NetR72_2: R72.2 S4.3 | length 84.7
  L1-Top Layer (GTL) w11: R72.2@2584.7,2066.55 S4.3@2669.39,2066.55
NetR73_1: R73.1 S4.4 | length 102.5
  L1-Top Layer (GTL) w11: R73.1@2587.7,1966.55 S4.4@2669.39,1966.55 S4.4@2690.2,1966.55
NetR77_2: R77.2 S5.1 S5.2 | length 504.1
  L1-Top Layer (GTL) w11: R77.2@337.14,1842.72 R77.2@338.64,1844.22 ; R77.2@337.14,1844.22 R77.2@338.64,1844.22 ; S5.2@836.02,1836.72 S5.1@477.76,1836.72 470.26,1844.22 R77.2@338.64,1844.22
NetR150_1: R150.1 U8.21 | length 95
  L1-Top Layer (GTL) w12: U8.21@1937.47,454.84 2028.22,454.84 R150.1@2031.21,451.85
NetR151_1: R151.1 U8.29 | length 93.9
  L1-Top Layer (GTL) w12: U8.29@1937.47,612.32 2030.74,612.32 R151.1@2031.21,611.85
NetR152_1: R152.1 U8.23 | length 94.8
  L1-Top Layer (GTL) w12: U8.23@1937.47,494.21 2028.58,494.21 R152.1@2031.21,496.85
NetR153_1: R153.1 U8.33 | length 93
  L1-Top Layer (GTL) w12: U8.33@1937.47,691.06 R153.1@2030.43,691.06
NetR154_1: R154.1 U8.45 | length 157.7
  L1-Top Layer (GTL) w12: U8.45@1780.98,906.61 1780.98,942.96 1801.29,963.27 1839.13,963.27 1857.71,981.85 R154.1@1857.71,1010.35
NetR155_2: R155.2 U8.46 | length 120.9
  L1-Top Layer (GTL) w12: U8.46@1761.29,906.61 1761.29,960.43 1802.71,1001.85 R155.2@1802.71,1010.35
NetR156_2: R156.2 U8.47 | length 104.2
  L1-Top Layer (GTL) w12: U8.47@1741.61,906.61 1741.61,1009.25 R156.2@1742.71,1010.35
NetR157_1: R157.1 U8.51 | length 122.4
  L1-Top Layer (GTL) w11: R157.1@1617.71,1010.35 1630.98,997.08 1630.98,983.58 1644.25,970.31 1644.25,970.05 1662.87,951.43 U8.51@1662.87,906.61
NetR158_1: R158.1 U8.52 | length 165.5
  L1-Top Layer (GTL) w11: R158.1@1557.71,1010.35 1557.71,981.85 1582.71,956.85 1627.71,956.85 1643.18,941.38 U8.52@1643.18,906.61
NetR159_1: R159.1 U8.9 | length 156.4
  L1-Top Layer (GTL) w10: R159.1@1567.71,278.35 1567.71,301.85 1577.71,311.85 1622.71,311.85 1643.18,332.32 U8.9@1643.18,377.09
NetR160_1: R160.1 U8.10 | length 113.3
  L1-Top Layer (GTL) w10: R160.1@1627.71,278.35 1662.87,313.5 U8.10@1662.87,377.09
NetR163_1: R163.1 U8.3 | length 143.4
  L1-Top Layer (GTL) w10: R163.1@1447.71,278.35 1486.21,316.85 1507.71,316.85 1525.07,334.21 U8.3@1525.07,377.09
NetR164_1: R164.1 U8.4 | length 114.1
  L1-Top Layer (GTL) w10: R164.1@1507.71,278.35 1544.76,315.39 U8.4@1544.76,377.09
NetR206_2: R206.2 Y1.9 | length 108.4
  L1-Top Layer (GTL) w20: Y1.9@4196.72,3282.66 R206.2@4305.16,3282.66
NetR500_1: R500.1 R502.2 U500.10 | length 733.1
  L1-Top Layer (GTL) w10: U500.10@6393.92,1603.53 6419.33,1603.53 6429.6,1613.8 6429.6,1662.3 6448.1,1680.8 R502.2@6516.5,1680.8
  L1-Top Layer (GTL) w15: R502.2@6516.5,1680.8 6516.5,1710.3 6543.1,1736.9 6635.9,1736.9 6658.1,1714.7 6658.1,1527.1 6604.4,1473.4 6604.4,1440.5 6591,1427.1 R500.1@6547.6,1427.1
OUT0_A_N: R10.2 R128.1 R169.1 | length 4396.6
  L1-Top Layer (GTL) w11: 384,3612.5 515.5,3612.5 743.5,3840.5 831.75,3840.5 860,3840.5 923.67,3840.5 ccw(c923.67,3916.75) 999.92,3916.75 999.92,4059.8 cw(c1032.17,4059.8) 1032.17,4092.05 1078.67,4092.05 cw(c1078.67,4059.8) 1110.92,4059.8 1110.92,3665.2 ccw(c1187.17,3665.2) 1187.17,3588.95 1233.67,3588.95 ccw(c1233.67,3665.2) 1309.92,3665.2 1309.92,3808.25 cw(c1342.17,3808.25) 1342.17,3840.5 1857,3840.5 2604.76,4588.25 2772.27,4588.25 3244.86,5060.14 3246.14,5060.14 R10.2@3294.08,5109.08
OUT0_A_P: R6.2 R132.1 R167.1 | length 4439
  L1-Top Layer (GTL) w11: R132.1@370.68,4112.5 577.82,4145.61 743.5,3884.5 860,3884.5 923.67,3884.5 ccw(c923.67,3916.75) 955.92,3916.75 955.92,4059.8 cw(c1032.17,4059.8) 1032.17,4136.05 1078.67,4136.05 cw(c1078.67,4059.8) 1154.92,4059.8 1154.92,3665.2 ccw(c1187.17,3665.2) 1187.17,3632.95 1233.67,3632.95 ccw(c1233.67,3665.2) 1265.92,3665.2 1265.92,3808.25 cw(c1342.17,3808.25) 1342.17,3884.5 1838.78,3884.5 2586.53,4632.25 2754.05,4632.25 3192.97,5070.71 3213.14,5090.86 3252.08,5129.8 R6.2@3252.08,5130.08 ; 3192.13,5071.55 R167.1@3214.04,5090.46
OUT0_N: R10.1 U1.3 | length 158
  L1-Top Layer (GTL) w9: R10.1@3321.92,5136.92 3355.7,5170.7 3355.7,5187.7 3374.88,5206.88 ; 3374.88,5207.51 U1.3@3374.88,5273.62
OUT0_P: R6.1 U1.2 | length 158
  L1-Top Layer (GTL) w9: R6.1@3279.92,5157.92 3323,5201 3342,5201 3355.2,5214.2 U1.2@3355.2,5273.62
OUT1_A_N: C100.2 R80.2 R170.1 | length 4274.6
  L1-Top Layer (GTL) w11: C100.2@381,3112.5 515.5,3112.5 565,3063 571.47,3056.53 ccw(c586.57,3071.63) 601.66,3056.53 603.85,3058.72 cw(c618.95,3043.62) 634.05,3058.72 646.99,3045.78 cw(c631.89,3030.68) 646.99,3015.59 644.8,3013.4 ccw(c659.89,2998.3) 644.8,2983.2 649,2979 743.5,2884.5 854.75,2884.5 1176.1,2884.5 1243.24,2951.64 ; 1243.08,2951.82 1279.03,2987.76 ccw(c1256.25,3010.56) 1288.48,3010.56 ccw(c1256.25,3010.56) 1279.05,3033.34 1203.97,3108.45 cw(c1257.99,3162.44) 1204,3216.45 1236.92,3249.35 cw(c1290.91,3195.34) 1344.92,3249.33 1419.99,3174.22 ccw(c1442.79,3197) 1465.57,3174.2 3245.14,4952.86 R80.2@3293.36,5001.08
OUT1_A_P: C98.2 R7.2 R168.1 | length 4271.7
  L1-Top Layer (GTL) w11: 384,2612.5 515.5,2612.5 743.5,2840.5 854.75,2840.5 1194.33,2840.5 1274.35,2920.53 ; 1274.28,2920.6 1310.24,2956.54 ccw(c1256.25,3010.56) 1332.62,3010.56 ccw(c1256.25,3010.56) 1310.26,3064.54 1235.19,3139.65 cw(c1257.99,3162.44) 1235.2,3185.23 1268.12,3218.13 cw(c1290.91,3195.34) 1313.7,3218.12 1388.77,3143.01 ccw(c1442.79,3197) 1496.78,3142.98 3292.86,4938.14 R7.2@3337.72,4983
OUT1_N: R80.1 U1.4 | length 282.7
  L1-Top Layer (GTL) w11: R80.1@3320.92,5028.92 3360,5067 3373.02,5067 3394.57,5088.55 ; 3394.57,5088.96 U1.4@3394.57,5273.62
OUT1_P: R7.1 U1.5 | length 282.7
  L1-Top Layer (GTL) w11: R7.1@3365.92,5010.92 3390.5,5035.5 3390.5,5051.5 3414.25,5075.25 U1.5@3414.25,5273.62
OUT2_A_N: C103.2 R84.2 R173.1 | length 4297.3
  L1-Top Layer (GTL) w11: R84.2@3748.92,5066.08 3771,5044 3771,5034 3809.71,4994 ; 3809.71,4995.29 3809.71,4994 ; 6614,3112.5 6487.5,3112.5 6458,3083 6449.3,3074.3 ccw(c6455.1,3068.5) 6449.3,3062.7 6461.33,3050.68 cw(c6455.53,3044.88) 6461.33,3039.08 6443.94,3021.69 cw(c6438.14,3027.48) 6432.34,3021.69 6420.31,3033.71 ccw(c6414.51,3027.91) 6408.72,3033.71 6318.5,2943.5 6259.5,2884.5 6184.5,2884.5 6086.75,2884.5 cw(c6086.75,2916.75) 6054.5,2916.75 6054.5,2975.42 ccw(c5978.25,2975.42) 5978.25,3051.67 5931.75,3051.67 ccw(c5931.75,2975.42) 5855.5,2975.42 5855.5,2916.75 cw(c5823.25,2916.75) 5823.25,2884.5 5692.73,2884.5 3809.71,4767.52 3809.71,4914.81 3809.71,4994
OUT2_A_P: C101.2 R81.2 R171.1 | length 4297.3
  L1-Top Layer (GTL) w11: R81.2@3705.66,5042.34 3733,5015 3741,5015 3766,4990 3765.91,4914.81 3765.71,4749.29 5674.51,2840.5 5823.25,2840.5 ccw(c5823.25,2916.75) 5899.5,2916.75 5899.5,2975.42 cw(c5931.75,2975.42) 5931.75,3007.67 5978.25,3007.67 cw(c5978.25,2975.42) 6010.5,2975.42 6010.5,2916.75 ccw(c6086.75,2916.75) 6086.75,2840.5 6184.5,2840.5 6259.5,2840.5 6487.5,2612.5 6614,2612.5
OUT2_N: R84.1 U1.13 | length 255.4
  L1-Top Layer (GTL) w8: U1.13@3571.73,5273.62 3571.73,5257.81 3569.94,5256.02 3569.94,5234.69 3649.5,5155.13 3649.5,5143.13 3678.53,5114.1 3700.9,5114.1 ; 3700.81,5114.19 R84.1@3720.49,5094.51
OUT2_P: R81.1 U1.12 | length 255.4
  L1-Top Layer (GTL) w8: U1.12@3552.05,5273.62 3552.05,5255.56 3553.94,5253.66 3553.94,5228.06 3633.5,5148.5 3633.5,5136.59 ; 3633.5,5136.5 3666.64,5103.36 3666.64,5081.36 R81.1@3677.82,5070.18
OUT3_A_N: C104.2 R87.2 R174.1 | length 5950.6
  L1-Top Layer (GTL) w11: R87.2@3782.92,5086.08 R174.1@3865.22,5003.72 ; C104.2@6625.37,3612.5 6482.5,3612.5 6254.5,3840.5 6133.75,3840.5 ccw(c6133.75,3808.25) 6101.5,3808.25 6101.5,3668.58 cw(c6025.25,3668.58) 6025.25,3592.33 5978.75,3592.33 cw(c5978.75,3668.58) 5902.5,3668.58 5902.5,4056.42 ccw(c5870.25,4056.42) 5870.25,4088.67 5823.75,4088.67 ccw(c5823.75,4056.42) 5791.5,4056.42 5791.5,3916.75 cw(c5715.25,3916.75) 5715.25,3840.5 5027.68,3840.5 ; R174.1@3865.22,5003.72 5027.68,3840.5 ; R174.1@3865.22,5003.72 5027.68,3840.5
OUT3_A_P: C102.2 R83.2 R172.1 | length 4306.1
  L1-Top Layer (GTL) w11: R83.2@3822.62,5105 3895.77,5034.25 5045.91,3884.5 5715.25,3884.5 ccw(c5715.25,3916.75) 5747.5,3916.75 5747.5,4056.42 cw(c5823.75,4056.42) 5823.75,4132.67 5870.25,4132.67 cw(c5870.25,4056.42) 5946.5,4056.42 5946.5,3668.58 ccw(c5978.75,3668.58) 5978.75,3636.33 6025.25,3636.33 ccw(c6025.25,3668.58) 6057.5,3668.58 6057.5,3808.25 cw(c6133.75,3808.25) 6133.75,3884.5 6254.5,3884.5 6364,3994 6364,4049 6448,4133 6543.5,4133 6564,4112.5 C102.2@6627.31,4112.5
OUT3_N: R87.1 U1.14 | length 257.7
  L1-Top Layer (GTL) w8: U1.14@3591.42,5273.62 3591.42,5257.81 3593.26,5255.97 3593.26,5242.9 ; 3593.26,5242.79 3661.14,5174.91 3713.07,5174.91 3728.98,5159.02 3728.98,5140.02 R87.1@3755,5114
OUT3_P: R83.1 U1.15 | length 257.7
  L1-Top Layer (GTL) w8: U1.15@3611.1,5273.62 3611.1,5257.81 3609.26,5255.97 3609.26,5249.42 3667.77,5190.91 3719.7,5190.91 3740.59,5170 3761,5170 R83.1@3795,5136
OUT4_A_N: C107.2 R93.2 R204.1 | length 4320.7
  L1-Top Layer (GTL) w11: R93.2@3866.91,5464.22 v9(3902.84,5464.22) 3931,5464.99 R204.1@3931.31,5465 ; v5(6560.67,5612.5) C107.2@6617,5612.5
  L6-Mid-Layer 5 (G4) w5: v9(3902.84,5464.22) 4644.45,5464.22 5020.73,5840.5 5541.35,5840.5 cw(c5541.35,5810.35) 5571.5,5810.35 5571.5,5669.5 ccw(c5645.65,5669.5) 5645.65,5595.35 5690.35,5595.35 ccw(c5690.35,5669.5) 5764.5,5669.5 5764.5,6055.5 cw(c5794.65,6055.5) 5794.65,6085.65 5839.35,6085.65 cw(c5839.35,6055.5) 5869.5,6055.5 5869.5,5669.5 ccw(c5943.65,5669.5) 5943.65,5595.35 5988.35,5595.35 ccw(c5988.35,5669.5) 6062.5,5669.5 6062.5,5810.35 cw(c6092.65,5810.35) 6092.65,5840.5 6200,5840.5 6254.5,5840.5 6482.5,5612.5 v5(6560.67,5612.5)
OUT4_A_P: C105.2 R89.2 R176.1 | length 4320.7
  L1-Top Layer (GTL) w11: R89.2@3867.91,5508.22 v9(3902.84,5508.22) 3932,5508 R176.1@3932.31,5508 ; v5(6560.67,6112.5) C105.2@6617,6112.5
  L6-Mid-Layer 5 (G4) w5: v9(3902.84,5508.22) 4626.22,5508.22 5002.5,5884.5 5541.35,5884.5 cw(c5541.35,5810.35) 5615.5,5810.35 5615.5,5669.5 ccw(c5645.65,5669.5) 5645.65,5639.35 5690.35,5639.35 ccw(c5690.35,5669.5) 5720.5,5669.5 5720.5,6055.5 cw(c5794.65,6055.5) 5794.65,6129.65 5839.35,6129.65 cw(c5839.35,6055.5) 5913.5,6055.5 5913.5,5669.5 ccw(c5943.65,5669.5) 5943.65,5639.35 5988.35,5639.35 ccw(c5988.35,5669.5) 6018.5,5669.5 6018.5,5810.35 cw(c6092.65,5810.35) 6092.65,5884.5 6200,5884.5 6254.5,5884.5 6482.5,6112.5 v5(6560.67,6112.5)
OUT4_N: R93.1 U1.26 | length 178.3
  L1-Top Layer (GTL) w8: U1.26@3656.38,5476.38 3672.19,5476.38 3674.03,5478.22 3815.21,5478.22 ; 3815.09,5478.22 R93.1@3828.31,5465
OUT4_P: R89.1 U1.27 | length 178.3
  L1-Top Layer (GTL) w8: U1.27@3656.38,5496.06 3672.19,5496.06 3674.03,5494.22 3814.42,5494.22 ; 3814.54,5494.22 R89.1@3828.31,5508
OUT5_A_N: C108.2 R95.2 R177.1 | length 4207.6
  L1-Top Layer (GTL) w8: R95.2@3941.92,5361.08 3991.26,5361.08 v9(3998.89,5353.45)
  L1-Top Layer (GTL) w11: v9(3998.89,5353.45) R177.1@4022.45,5353.45 ; v5(6560.67,5112.5) C108.2@6617,5112.5
  L6-Mid-Layer 5 (G4) w5: v9@3998.89,5353.45 4490.55,5353.45 4795.89,5048.11 4959.5,4884.5 5556.35,4884.5 cw(c5556.35,4810.35) 5630.5,4810.35 5630.5,4684.9 ccw(c5660.65,4684.9) 5660.65,4654.75 5705.35,4654.75 ccw(c5705.35,4684.9) 5735.5,4684.9 5735.5,5040.1 cw(c5809.65,5040.1) 5809.65,5114.25 5854.35,5114.25 cw(c5854.35,5040.1) 5928.5,5040.1 5928.5,4684.9 ccw(c5958.65,4684.9) 5958.65,4654.75 6003.35,4654.75 ccw(c6003.35,4684.9) 6033.5,4684.9 6033.5,4810.35 cw(c6107.65,4810.35) 6107.65,4884.5 6155.65,4884.5 6254.5,4884.5 6295.27,4977.27 6416.05,5098.05 6482.5,5112.5 v5(6560.67,5112.5)
OUT5_A_P: C106.2 R91.2 R175.1 | length 4212.3
  L1-Top Layer (GTL) w8: R91.2@3926.55,5323.45 3984.89,5323.45 v9(3998.89,5309.45)
  L1-Top Layer (GTL) w11: v9(3998.89,5309.45) R175.1@4022.45,5309.45 ; v5(6560.67,4612.5) C106.2@6617,4612.5
  L6-Mid-Layer 5 (G4) w5: v9(3998.89,5309.45) 4472.32,5309.45 4764.78,5017 4941.28,4840.5 5556.35,4840.5 cw(c5556.35,4810.35) 5586.5,4810.35 5586.5,4684.9 ccw(c5660.65,4684.9) 5660.65,4610.75 5705.35,4610.75 ccw(c5705.35,4684.9) 5779.5,4684.9 5779.5,5040.1 cw(c5809.65,5040.1) 5809.65,5070.25 5854.35,5070.25 cw(c5854.35,5040.1) 5884.5,5040.1 5884.5,4684.9 ccw(c5958.65,4684.9) 5958.65,4610.75 6003.35,4610.75 ccw(c6003.35,4684.9) 6077.5,4684.9 6077.5,4810.35 cw(c6107.65,4810.35) 6107.65,4840.5 6160,4840.5 ; 6155.65,4840.5 6254.5,4840.5 6482.5,4612.5 v5(6560.67,4612.5)
OUT5_N: R95.1 U1.25 | length 284.8
  L1-Top Layer (GTL) w8: U1.25@3656.38,5456.69 3725.27,5456.69 3746.96,5435 3851.63,5435 3880.41,5406.22 3895.83,5406.22 ; 3896.83,5406.17 R95.1@3914.08,5388.92
OUT5_P: R91.1 U1.24 | length 284.8
  L1-Top Layer (GTL) w8: U1.24@3656.38,5437.01 3722.33,5437.01 3740.33,5419 3844.94,5419 ; 3845,5419 3865,5399 3865,5386 R91.1@3898.05,5351.95
OUT6_A_N: C111.2 R100.2 R205.1 | length 4304.4
  L1-Top Layer (GTL) w11: R100.2@3899.69,5659 4559.59,5660.82 5242.04,6343.26 cw(c5295.95,6289.34) 5349.87,6343.26 5411.63,6281.5 ccw(c5434.43,6304.31) 5457.23,6281.51 5490.11,6314.39 ccw(c5467.31,6337.19) 5499.56,6337.19 ccw(c5467.31,6337.19) 5490.11,6359.99 5289.88,6560.23 cw(c5343.8,6614.14) 5289.88,6668.06 5322.76,6700.94 cw(c5376.68,6647.02) 5430.6,6700.94 5630.83,6500.71 ccw(c5653.63,6523.51) 5676.44,6500.71 5709.32,6533.59 ccw(c5686.51,6556.39) 5718.76,6556.39 ccw(c5686.51,6556.39) 5709.32,6579.2 5647.56,6640.95 cw(c5701.48,6694.87) 5647.56,6748.79 5683.45,6784.67 5783.27,6884.5 6170.5,6884.5 6254.5,6884.5 6482.5,7112.5 6614,7112.5
OUT6_A_P: C109.2 R97.2 R179.1 | length 4318.4
  L1-Top Layer (GTL) w11: R97.2@3899.69,5617 4577.82,5616.82 5273.15,6312.15 cw(c5295.95,6289.34) 5318.76,6312.15 5380.51,6250.39 ccw(c5434.43,6304.31) 5488.35,6250.39 5521.23,6283.27 ccw(c5467.31,6337.19) 5543.56,6337.19 ccw(c5467.31,6337.19) 5521.23,6391.11 5320.99,6591.34 cw(c5343.8,6614.14) 5320.99,6636.95 5353.87,6669.83 cw(c5376.68,6647.02) 5399.48,6669.83 5599.72,6469.6 ccw(c5653.63,6523.51) 5707.55,6469.6 5740.43,6502.48 ccw(c5686.51,6556.39) 5762.76,6556.39 ccw(c5686.51,6556.39) 5740.43,6610.31 5678.67,6672.07 cw(c5701.48,6694.87) 5678.67,6717.67 5714.56,6753.56 5801.5,6840.5 6170.5,6840.5 6254.5,6840.5 6480.3,6612.4 C109.2@6627.31,6612.5
OUT6_N: R100.1 U1.30 | length 248.1
  L1-Top Layer (GTL) w8: U1.30@3656.38,5555.12 3672.19,5555.12 3674.03,5553.28 3705.28,5553.28 3799.69,5647.69 3826.69,5647.69 3838,5659 R100.1@3859.9,5659
OUT6_P: R97.1 U1.29 | length 248.1
  L1-Top Layer (GTL) w8: U1.29@3656.38,5535.43 3672.19,5535.43 3674.03,5537.28 3711.9,5537.28 3803.63,5629 3826,5629 3838,5617 R97.1@3860.73,5617
OUT7_A_N: C112.2 R102.2 R180.1 | length 4183.4
  L1-Top Layer (GTL) w11: R102.2@3983.69,5743.73 4032,5743.73 4102.73,5743.73 5876.87,7517.87 cw(c5899.67,7495.06) 5922.48,7517.87 6087.31,7353.03 ccw(c6141.23,7406.95) 6195.14,7353.03 6228.02,7385.91 ccw(c6174.11,7439.83) 6250.36,7439.83 ccw(c6174.11,7439.83) 6228.02,7493.75 6063.19,7658.58 cw(c6085.99,7681.39) 6063.19,7704.19 6099.08,7740.08 6199.5,7840.5 6254.5,7840.5 6482.5,7612.5 6614,7612.5
OUT7_A_P: C110.2 R98.2 R178.1 | length 4178.7
  L1-Top Layer (GTL) w11: R98.2@3983.69,5789 R178.1@4027.35,5789 ; R178.1@4032,5789 4085.77,5789 5845.75,7548.98 cw(c5899.67,7495.06) 5953.59,7548.98 6118.42,7384.14 ccw(c6141.23,7406.95) 6164.03,7384.14 6196.91,7417.03 ccw(c6174.11,7439.83) 6206.36,7439.83 ccw(c6174.11,7439.83) 6196.91,7462.63 6032.08,7627.47 cw(c6085.99,7681.39) 6032.08,7735.3 6067.96,7771.19 6181.28,7884.5 6254.5,7884.5 6481.7,8112.9 6614,8112.5
OUT7_N: R102.1 U1.31 | length 369.5
  L1-Top Layer (GTL) w8: U1.31@3656.38,5574.8 3672.19,5574.8 3674.03,5576.65 3690.79,5576.65 3871.87,5757.73 3902.64,5757.73 3916.64,5743.73
  L1-Top Layer (GTL) w11: 3916.64,5743.73 R102.1@3944.31,5743.73
OUT7_P: R98.1 U1.32 | length 369.5
  L1-Top Layer (GTL) w8: U1.32@3656.38,5594.49 3672.19,5594.49 3674.03,5592.65 3684.16,5592.65 3865.24,5773.73 3902.64,5773.73 3916.64,5787.73
  L1-Top Layer (GTL) w11: 3916.64,5787.73 R98.1@3944.31,5787.73
OUT8_A_N: C115.2 R107.2 R183.1 | length 4248.1
  L1-Top Layer (GTL) w8: v9(3000.79,5708.54) 3023.42,5708.54 3072,5659.96 3086.96,5659.96 3102.91,5644 R107.2@3112.31,5644
  L1-Top Layer (GTL) w11: v5(1747.5,8723.67) C115.2@1747.5,8780 ; R183.1@2984.13,5725.2 v9(3000.79,5708.54)
  L6-Mid-Layer 5 (G4) w5: v5(1747.5,8723.67) 1747.5,8645.5 1975.5,8417.5 1975.5,8329.65 1975.5,8295.25 1975.5,8248.4 cw(c1945.35,8248.4) 1945.35,8218.25 1757.05,8218.25 ccw(c1757.05,8144.1) 1682.91,8144.1 1682.91,8099.4 ccw(c1757.05,8099.4) 1757.05,8025.25 1945.35,8025.25 cw(c1945.35,7995.1) 1975.5,7995.1 1975.5,7487.5 2521,6942 2521,6188.33 v9(3000.79,5708.54)
OUT8_A_P: C113.2 R104.2 R181.1 | length 4248.1
  L1-Top Layer (GTL) w8: v9(3031.9,5739.65) 3031.9,5719.85 3077.8,5673.96 3088,5673.96 3094.04,5680 R104.2@3111.31,5680
  L1-Top Layer (GTL) w11: v5(2247.5,8723.67) C113.2@2247.5,8780 ; R181.1@3015.24,5756.31 v9(3031.9,5739.65)
  L6-Mid-Layer 5 (G4) w5: v5(2247.5,8723.67) 2247.5,8640 2190,8588 2184.16,8582.17 ccw(c2197.78,8568.56) 2184.16,8554.94 2187.1,8552.01 cw(c2173.49,8538.4) 2187.1,8524.78 2175.43,8513.12 cw(c2161.82,8526.73) 2148.21,8513.12 2145.27,8516.05 ccw(c2131.66,8502.44) 2118.05,8516.05 2108.5,8506.5 2054.15,8452.15 2019.5,8417.5 2019.5,8329.65 2019.5,8295.25 2019.5,8248.4 cw(c1945.35,8248.4) 1945.35,8174.25 1757.05,8174.25 ccw(c1757.05,8144.1) 1726.9,8144.1 1726.9,8099.4 ccw(c1757.05,8099.4) 1757.05,8069.25 1945.35,8069.25 cw(c1945.35,7995.1) 2019.5,7995.1 2019.5,7505.73 2565,6960.22 2565,6206.55 v9(3031.9,5739.65)
OUT8_N: R107.1 U1.52 | length 246.9
  L1-Top Layer (GTL) w8: R107.1@3152.68,5644 3167,5644 3176.39,5654.39 3191.61,5654.39 3205,5640 3205,5579.37 3248.94,5535.43 U1.52@3309.92,5535.43
OUT8_P: R104.1 U1.51 | length 246.9
  L1-Top Layer (GTL) w8: R104.1@3151.11,5680 3167.5,5680 3174.5,5671 3197,5671 3221,5647 3221,5586 3251.88,5555.12 U1.51@3309.92,5555.12
OUT9_A_N: C116.2 R108.2 R184.1 | length 4229.9
  L1-Top Layer (GTL) w8: v9(2915.75,5684.8) 2915.75,5665 2983.75,5597 ; 2983.96,5597 3016,5597 3028,5609 R108.2@3045.31,5609
  L1-Top Layer (GTL) w11: v5(1247.5,8723.67) C116.2@1247.5,8780 ; R184.1@2899.09,5701.46 v9(2915.75,5684.8)
  L6-Mid-Layer 5 (G4) w5: v5(1247.5,8723.67) 1247.5,8645.5 1148.5,8546.5 1144.79,8542.79 ccw(c1153.45,8534.13) 1144.79,8525.47 1152.2,8518.06 cw(c1143.53,8509.39) 1152.2,8500.73 1144.77,8493.31 cw(c1136.11,8501.97) 1127.45,8493.31 1120.04,8500.72 ccw(c1111.38,8492.05) 1102.71,8500.72 1098.5,8496.5 1019.5,8417.5 1019.5,8098.73 2180,6938.22 2180,6420.55 v9(2915.75,5684.8)
OUT9_A_P: C114.2 R106.2 R182.1 | length 4230.7
  L1-Top Layer (GTL) w8: v9(2884.64,5653.69) 2904.44,5653.69 2977.12,5581 3016.21,5581 ; 3016,5581 3027,5570 R106.2@3045.31,5570
  L1-Top Layer (GTL) w11: v5(747.5,8723.67) C114.2@747.5,8780 ; R182.1@2867.98,5670.35 v9(2884.64,5653.69)
  L6-Mid-Layer 5 (G4) w5: v5(747.5,8723.67) 747.5,8645.5 975.5,8417.5 975.5,8080.5 2136,6920 2136,6402.32 v9(2884.64,5653.69)
OUT9_N: R108.1 U1.53 | length 265.4
  L1-Top Layer (GTL) w8: R108.1@3084.68,5609 3099,5609 3111,5597 3152.63,5597 3235.72,5513.91 3292.27,5513.91 3294.11,5515.75 U1.53@3309.92,5515.75
OUT9_P: R106.1 U1.54 | length 265.4
  L1-Top Layer (GTL) w8: R106.1@3084.27,5570 3100,5570 3111,5581 3146,5581 3229.09,5497.91 3292.27,5497.91 3294.11,5496.06 U1.54@3309.92,5496.06
OUT10_A_N: C119.2 R114.2 R187.1 | length 4386.1
  L1-Top Layer (GTL) w8: 2913.39,5424.85 2927.39,5434.85 R187.1@3020.85,5434.85 ; R187.1@3021,5435 3066,5435 3073,5428 R114.2@3106.31,5428 ; R114.2@3106,5427.69 R114.2@3106.31,5428 ; R114.2@3106.91,5428 R114.2@3106.31,5428
  L1-Top Layer (GTL) w11: 384,7612.5 515.5,7612.5 735.5,7840.5 841.28,7840.5 918.91,7762.86 982.32,7699.45 982.32,7673.84 966.7,7658.22 966.7,7595.3 1044.5,7517.5 1107.42,7517.5 1123.04,7533.12 1148.65,7533.12 1913,6768.77 1913,5977.77 2465.92,5424.85 2913.39,5424.85
OUT10_A_P: C117.2 R110.2 R185.1 | length 4383.2
  L1-Top Layer (GTL) w8: 2913.39,5468.85 2927.39,5456.85 2991.21,5457 3065,5457 3075,5467 R110.2@3104.72,5467
  L1-Top Layer (GTL) w11: 384,8112.5 515.5,8112.5 743.5,7884.5 859.5,7884.5 950.02,7793.98 1026.32,7717.68 1026.32,7655.61 1010.7,7639.99 1010.7,7614.38 1063.58,7561.5 1089.19,7561.5 1104.81,7577.12 1166.88,7577.12 1957,6787 1957,5996 2484.15,5468.85 2913.39,5468.85
OUT10_N: R114.1 U1.57 | length 170.2
  L1-Top Layer (GTL) w8: R114.1@3144.98,5428 3163.15,5428 3174,5438.85 3292.27,5438.85 3294.11,5437.01 U1.57@3309.92,5437.01
OUT10_P: R110.1 U1.56 | length 170.2
  L1-Top Layer (GTL) w8: R110.1@3145.51,5467 3161.85,5467 3174,5454.85 3292.27,5454.85 3294.11,5456.69 U1.56@3309.92,5456.69
OUT11_A_N: C120.2 R116.2 R188.1 | length 4283.9
  L1-Top Layer (GTL) w11: 384,7112.5 515.5,7112.5 743.5,6884.5 870.5,6884.5 965.14,6789.86 ; 965,6790 1000.89,6754.11 ccw(c1023.69,6776.92) 1046.49,6754.11 1155.23,6862.85 cw(c1209.15,6808.94) 1263.07,6862.85 1295.95,6829.97 cw(c1242.03,6776.06) 1318.28,6776.06 cw(c1242.03,6776.06) 1295.95,6722.14 1001.75,6427.94 ccw(c1024.55,6405.14) 1001.75,6382.33 1034.63,6349.45 ccw(c1057.43,6372.26) 1080.24,6349.45 1188.98,6458.19 cw(c1242.89,6404.27) 1296.81,6458.19 2392.51,5362.49 2893.27,5362.49 2994,5362.49 2997.49,5359 R116.2@3032,5359
OUT11_A_P: C118.2 R112.2 R186.1 | length 4283.9
  L1-Top Layer (GTL) w11: 384,6612.5 515.5,6612.5 743.5,6840.5 852.28,6840.5 934.02,6758.75 ; 933.89,6758.89 969.77,6723 ccw(c1023.69,6776.92) 1077.61,6723 1186.35,6831.74 cw(c1209.15,6808.94) 1231.95,6831.74 1264.83,6798.86 cw(c1242.03,6776.06) 1274.28,6776.06 cw(c1242.03,6776.06) 1264.83,6753.25 970.64,6459.05 ccw(c1024.55,6405.14) 970.64,6351.22 1003.52,6318.34 ccw(c1057.43,6372.26) 1111.35,6318.34 1220.09,6427.08 cw(c1242.89,6404.27) 1265.7,6427.08 2374.28,5318.49 2893.27,5318.49 2994,5318.49 2997.51,5322 R112.2@3031.99,5322
OUT11_N: R116.1 U1.58 | length 271.5
  L1-Top Layer (GTL) w8: R116.1@3071.01,5359 3104.49,5359 3115,5348.49 3126.49,5348.49 3194.48,5415.48 3292.27,5415.48 3294.11,5417.32 U1.58@3309.92,5417.32
OUT11_P: R112.1 U1.59 | length 271.5
  L1-Top Layer (GTL) w8: R112.1@3071,5322 3104.51,5322 3115,5332.49 3133.12,5332.49 3201.11,5399.48 3292.27,5399.48 3294.11,5397.64 U1.59@3309.92,5397.64
OUT12_A_N: C123.2 R123.2 R191.1 | length 4360.1
  L1-Top Layer (GTL) w11: 384,5612.5 515.5,5612.5 743.5,5840.5 837.5,5840.5 896.44,5781.56 ccw(c950.36,5835.48) 1004.27,5781.56 1092.74,5870.02 cw(c1115.54,5847.22) 1138.35,5870.02 1171.23,5837.14 cw(c1148.42,5814.34) 1180.67,5814.34 cw(c1148.42,5814.34) 1171.23,5791.54 917.58,5537.88 ccw(c971.49,5483.97) 917.58,5430.05 950.46,5397.17 ccw(c1004.37,5451.09) 1058.29,5397.17 1311.94,5650.82 cw(c1334.75,5628.02) 1357.55,5650.82 1390.43,5617.94 cw(c1367.63,5595.14) 1399.88,5595.14 cw(c1367.63,5595.14) 1390.43,5572.33 1301.97,5483.87 ccw(c1355.88,5429.95) 1301.97,5376.03 1478.33,5199.67 1501.22,5176.78 2960,5176.78 3062.78,5176.78 R123.2@3131.08,5245.08
OUT12_A_P: C121.2 R118.2 R189.1 | length 4361.4
  L1-Top Layer (GTL) w11: 384,6112.5 554.92,6118.83 743.5,5884.5 855.73,5884.5 927.55,5812.67 ccw(c950.36,5835.48) 973.16,5812.67 1061.63,5901.14 cw(c1115.54,5847.22) 1169.46,5901.14 1202.34,5868.26 cw(c1148.42,5814.34) 1224.67,5814.34 cw(c1148.42,5814.34) 1202.34,5760.42 948.69,5506.77 ccw(c971.49,5483.97) 948.69,5461.16 981.57,5428.28 ccw(c1004.37,5451.09) 1027.18,5428.28 1280.83,5681.93 cw(c1334.75,5628.02) 1388.66,5681.93 1421.54,5649.05 cw(c1367.63,5595.14) 1443.88,5595.14 cw(c1367.63,5595.14) 1421.54,5541.22 1333.08,5452.76 ccw(c1355.88,5429.95) 1333.08,5407.15 1509.45,5230.78 1519.45,5220.78 2960,5219.98 3038,5219.93 3054.93,5219.93 R118.2@3117.08,5282.08
OUT12_N: R123.1 U1.61 | length 193.1
  L1-Top Layer (GTL) w8: R123.1@3160.92,5272.92 3187.81,5299.81 3187.81,5312.19 3235.74,5360.11 3292.27,5360.11 3294.11,5358.27 U1.61@3309.92,5358.27
OUT12_P: R118.1 U1.60 | length 193.1
  L1-Top Layer (GTL) w8: R118.1@3144.92,5309.92 3157,5322 3175,5322 3229.11,5376.11 ; 3229.16,5376.11 3292.27,5376.11 3294.11,5377.95 U1.60@3309.92,5377.95
OUT13_A_N: C124.2 R124.2 R134.1 | length 4222.3
  L1-Top Layer (GTL) w8: 2921.46,5077.98 2940,5066 3002,5066 3013,5077 3013,5085.63 R124.2@3034.08,5106.71
  L1-Top Layer (GTL) w11: 384,5112.5 523.05,5117.66 745.23,4886.54 775,4884.5 864.38,4884.5 ccw(c864.38,4916.75) 896.63,4916.75 896.63,5008.37 cw(c972.88,5008.37) 972.88,5084.62 1019.38,5084.62 cw(c1019.38,5008.37) 1095.63,5008.37 1095.63,4716.63 ccw(c1127.88,4716.63) 1127.88,4684.38 1174.38,4684.38 ccw(c1174.38,4716.63) 1206.63,4716.63 1206.63,5008.37 cw(c1282.88,5008.37) 1282.88,5084.62 1329.38,5084.62 cw(c1329.38,5008.37) 1405.63,5008.37 1405.63,4716.63 ccw(c1437.88,4716.63) 1437.88,4684.38 1484.38,4684.38 ccw(c1484.38,4716.63) 1516.63,4716.63 1516.63,4808.25 cw(c1592.88,4808.25) 1592.88,4884.5 1752,4884.5 2127.19,4884.5 2320.68,5077.98 2921.46,5077.98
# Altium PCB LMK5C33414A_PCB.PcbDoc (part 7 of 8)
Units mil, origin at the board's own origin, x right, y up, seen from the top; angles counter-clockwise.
Board outline 7000 x 9161 mil, 8 copper layers (L1-Top Layer (GTL), L2-GND Plane (GP1), L3-Mid-Layer 2 (G1), L4-Mid-Layer 3 (G2), L5-Mid-Layer 4 (G3), L6-Mid-Layer 5 (G4), L7-Mid-Layer 6 (G5), L8-Bottom Layer (GBL)), stack 61.2 mil thick; 521 components, 286 nets, 1393 pads, 2202 vias.

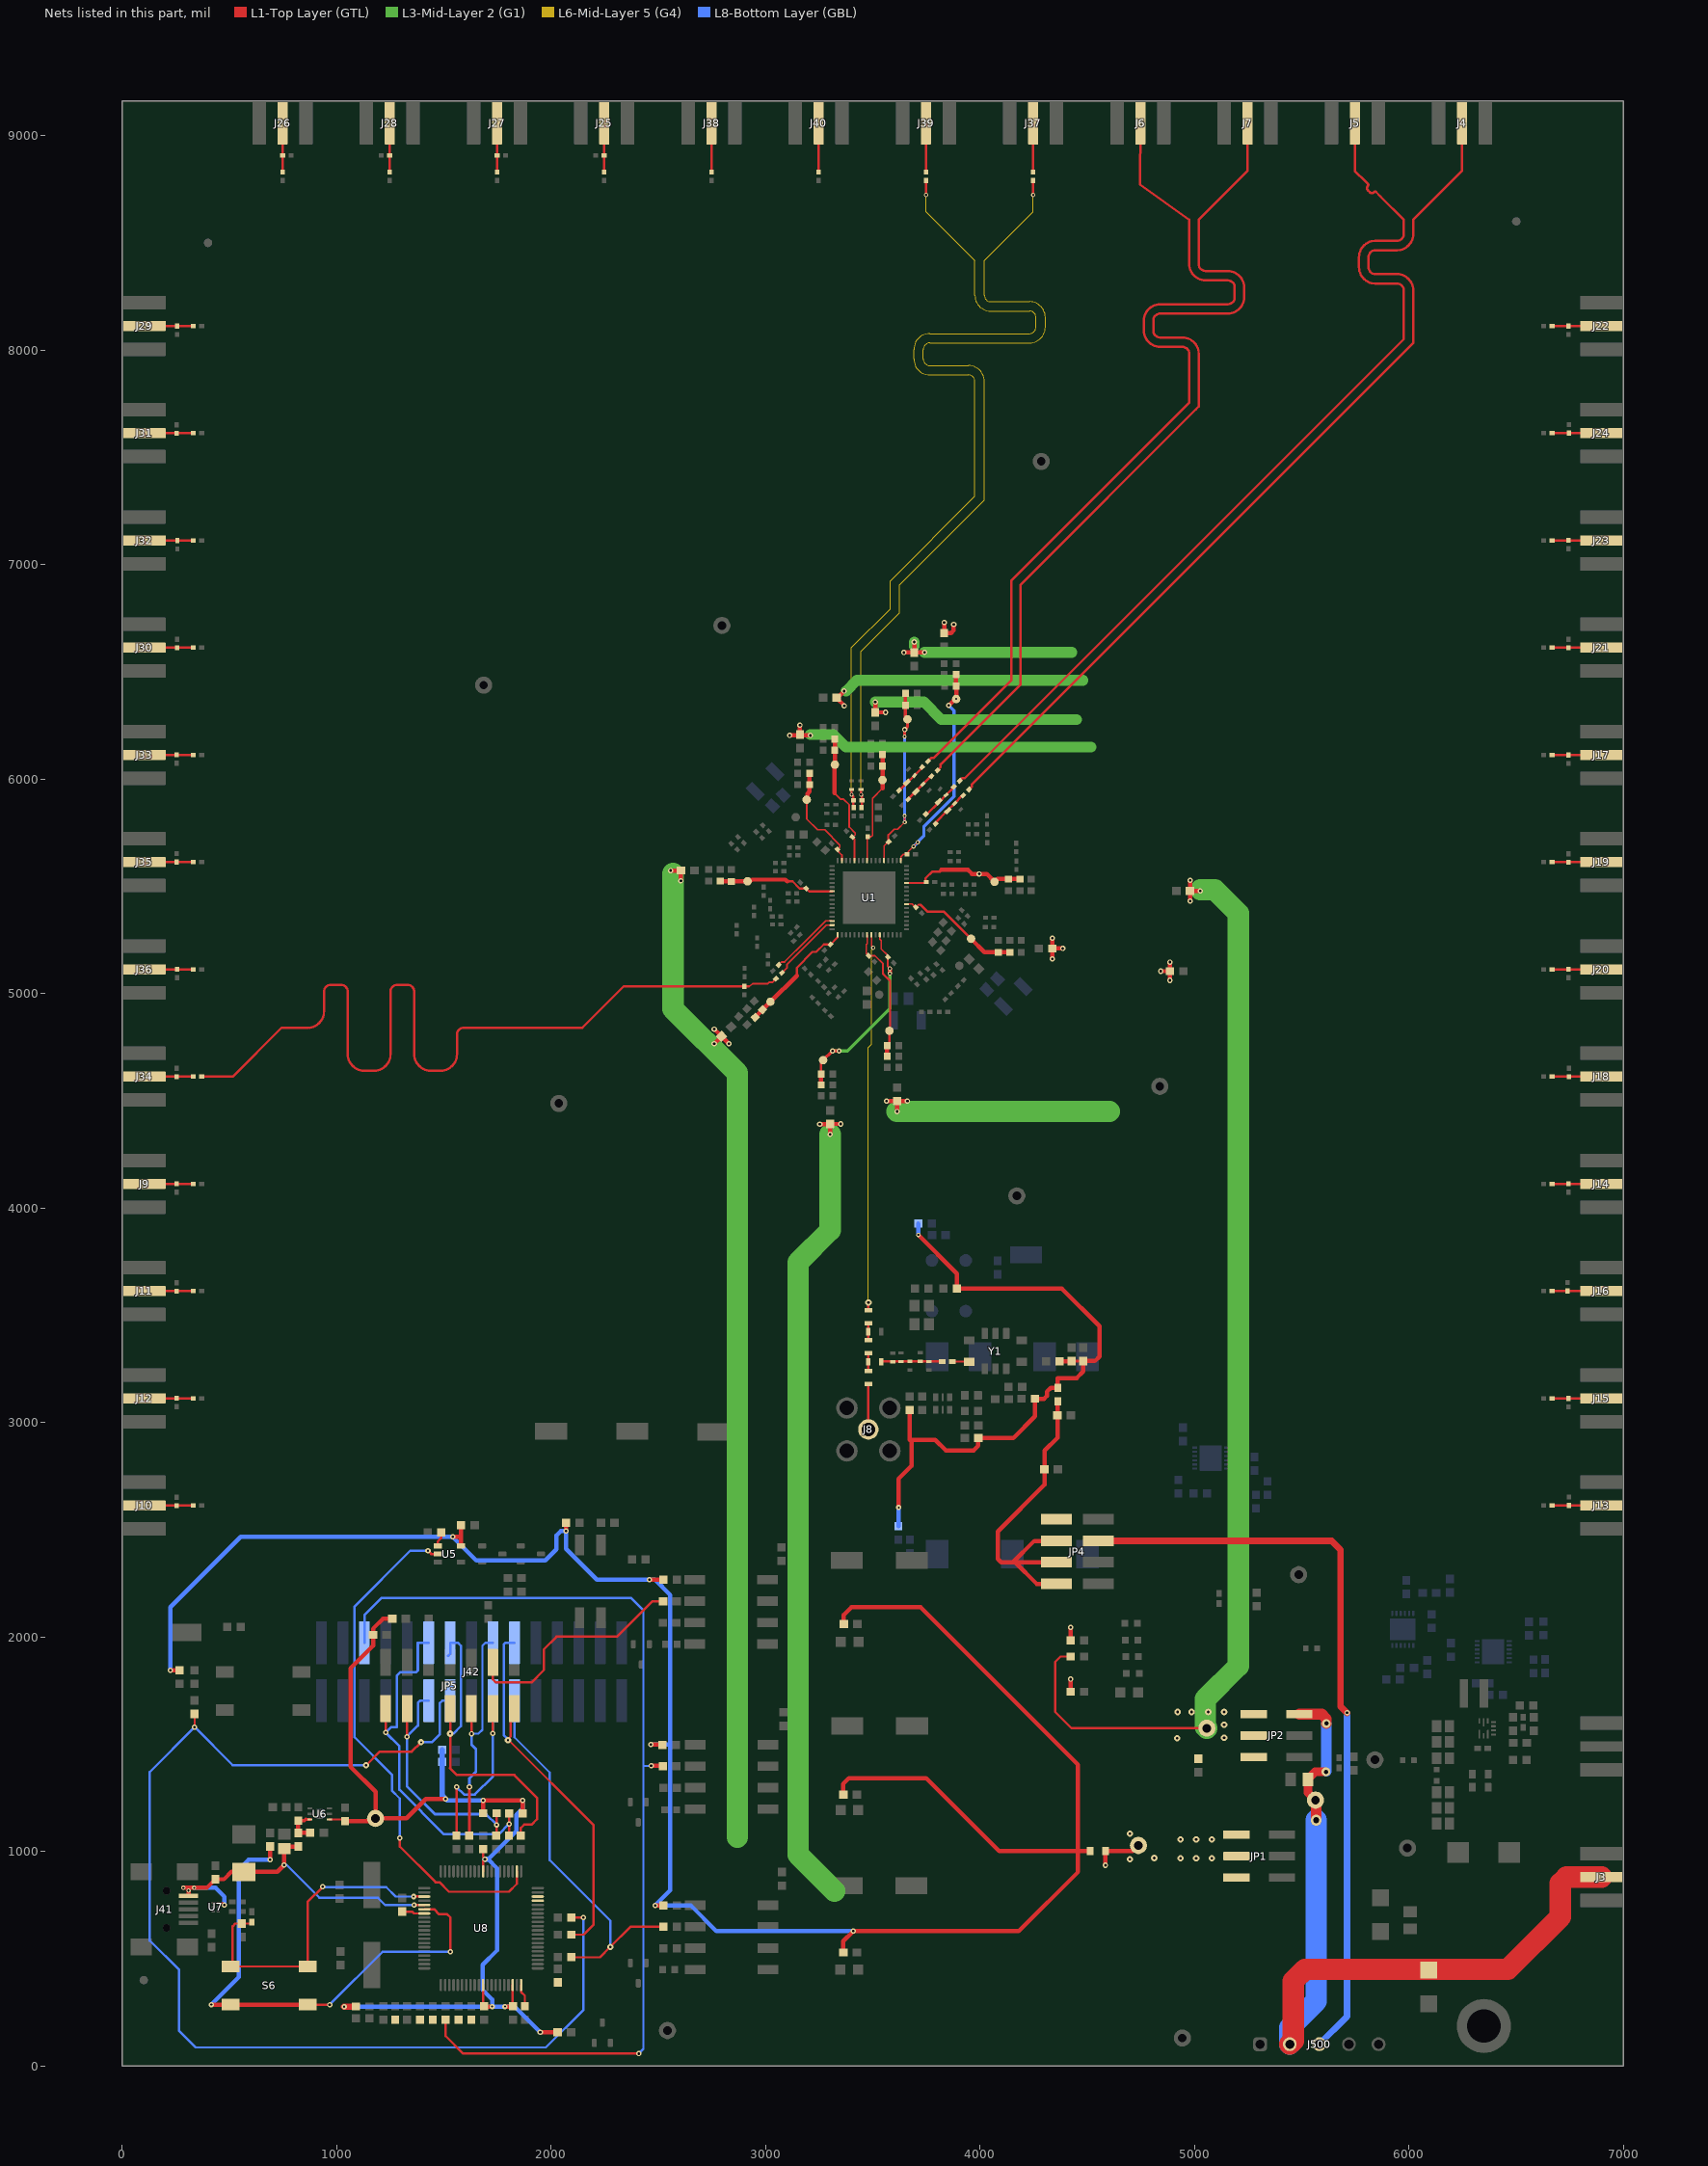
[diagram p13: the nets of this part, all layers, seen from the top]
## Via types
v1: diameter 20, hole 10, L1-Top Layer (GTL) to L8-Bottom Layer (GBL), tented top, 1246 vias
v2: diameter 30, hole 12, L1-Top Layer (GTL) to L8-Bottom Layer (GBL), 519 vias
v3: diameter 25, hole 12, L1-Top Layer (GTL) to L8-Bottom Layer (GBL), tented top, 172 vias
v4: diameter 30, hole 12, L1-Top Layer (GTL) to L8-Bottom Layer (GBL), tented top, 57 vias
v5: diameter 20, hole 10, L1-Top Layer (GTL) to L8-Bottom Layer (GBL), 48 vias
v6: diameter 19.68, hole 7.87, L1-Top Layer (GTL) to L8-Bottom Layer (GBL), 47 vias
v7: diameter 25, hole 10, L1-Top Layer (GTL) to L8-Bottom Layer (GBL), tented top, 35 vias
v8: diameter 25, hole 12, L1-Top Layer (GTL) to L8-Bottom Layer (GBL), 24 vias
v9: diameter 18, hole 10, L1-Top Layer (GTL) to L8-Bottom Layer (GBL), tented top, 12 vias
v10: diameter 30, hole 10, L1-Top Layer (GTL) to L8-Bottom Layer (GBL), 10 vias
v11: diameter 40, hole 20, L1-Top Layer (GTL) to L8-Bottom Layer (GBL), 10 vias
v12: diameter 39.37, hole 19.68, L1-Top Layer (GTL) to L8-Bottom Layer (GBL), tented top, 6 vias
v13: diameter 25, hole 10, L1-Top Layer (GTL) to L8-Bottom Layer (GBL), 5 vias
v14: diameter 23, hole 10, L1-Top Layer (GTL) to L8-Bottom Layer (GBL), tented top, 4 vias
v15: diameter 50, hole 28, L1-Top Layer (GTL) to L8-Bottom Layer (GBL), 4 vias
v16: diameter 20/0/0/0/0/0/20 (per signal layer), hole 10, L1-Top Layer (GTL) to L8-Bottom Layer (GBL), tented top, 2 vias
v17: diameter 25, hole 12, L1-Top Layer (GTL) to L8-Bottom Layer (GBL), tented both sides, 1 vias

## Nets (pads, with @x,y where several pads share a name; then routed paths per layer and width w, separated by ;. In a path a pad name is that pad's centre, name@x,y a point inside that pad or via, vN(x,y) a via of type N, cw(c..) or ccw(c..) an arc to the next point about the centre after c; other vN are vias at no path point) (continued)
OUT13_A_P: C122.2 R120.2 R190.1 | length 4218.2
  L1-Top Layer (GTL) w8: 2921.46,5033.98 2939.92,5045.44 3009.2,5045.44 ; 3009.24,5045.44 3016.8,5053 3032.37,5053 R120.2@3047.08,5067.71
  L1-Top Layer (GTL) w11: 384,4612.5 515.5,4612.5 743.5,4840.5 775,4840.5 864.38,4840.5 ccw(c864.38,4916.75) 940.63,4916.75 940.63,5008.37 cw(c972.88,5008.37) 972.88,5040.62 1019.38,5040.62 cw(c1019.38,5008.37) 1051.63,5008.37 1051.63,4716.63 ccw(c1127.88,4716.63) 1127.88,4640.38 1174.38,4640.38 ccw(c1174.38,4716.63) 1250.63,4716.63 1250.63,5008.37 cw(c1282.88,5008.37) 1282.88,5040.62 1329.38,5040.62 cw(c1329.38,5008.37) 1361.63,5008.37 1361.63,4716.63 ccw(c1437.88,4716.63) 1437.88,4640.38 1484.38,4640.38 ccw(c1484.38,4716.63) 1560.63,4716.63 1560.63,4808.25 cw(c1592.88,4808.25) 1592.88,4840.5 1752,4840.5 2145.42,4840.5 2338.9,5033.98 2921.46,5033.98
OUT13_N: R124.1 U1.62 | length 335.2
  L1-Top Layer (GTL) w8: R124.1@3060.92,5133.55 3074,5146.63 3088,5146.63 3191,5249.63 ; 3190,5248.63 3279.96,5338.58 ; 3280.09,5338.58 U1.62@3309.92,5338.58
OUT13_P: R120.1 U1.63 | length 335.2
  L1-Top Layer (GTL) w8: R120.1@3075.92,5096.55 3099.81,5120.44 3099.81,5135.81 3206,5242 3282.9,5318.9 ; 3282.8,5318.9 3282.9,5318.9 ; U1.63@3309.92,5318.9 3282.9,5318.9
OUT_XO: R43.2 Y1.5 | length 64.6
  L1-Top Layer (GTL) w10: R43.2@3870.18,3284.21 Y1.5@3934.78,3284.21
PUR: R147.1 R149.2 S6.1 S6.2 U8.63 | length 1550.1
  L1-Top Layer (GTL) w11: S6.1@496.38,473.07 S6.1@505.87,463.58 S6.1@507.02,463.58 ; S6.1@506.36,462.93 S6.1@507.02,463.58 ; R147.1@604,663.5 527.23,663.5 514.5,650.77 514.5,610 514.5,471.07 S6.1@507.02,463.58 ; v3(935,835) 864.13,764.13 S6.2@864.13,463.58 S6.1@507.02,463.58 ; v7@1358.68,789.69 U8.63@1408.08,789.69
  L8-Bottom Layer (GBL) w11: v3(935,835) 937,833 1231,833 1274.67,789.33 v7(1358.32,789.33)
R_IN0_N: R29.1 R30.2 R31.1 R32.2 | length 179.4
  L1-Top Layer (GTL) w11: R31.1@3750.15,5833.65 3809.23,5892.72 3841.73,5925.22 R30.2@3877,5960.49
R_IN0_P: R26.2 R27.1 R28.2 R29.2 | length 179.4
  L1-Top Layer (GTL) w11: R27.1@3789.11,5794.68 3848.19,5853.76 3881.07,5886.64 R26.2@3915.96,5921.53
R_IN1_N: R36.1 R37.2 R38.1 R39.2 | length 153
  L1-Top Layer (GTL) w11: R38.1@3663.53,5906.31 3699.61,5942.39 3733.11,5975.89 R37.2@3771.69,6014.47
R_IN1_P: R33.2 R34.1 R35.2 R36.2 | length 153
  L1-Top Layer (GTL) w11: R34.1@3623.53,5946.31 3659.61,5982.39 R35.2@3693.81,6016.61 3730.69,6053.47 R33.2@3731.69,6054.47
R_IN2_N: R130.2 R140.2 R141.1 R192.1 | length 4276.6
  L1-Top Layer (GTL) w11: R141.1@3400.59,5951.23 v9(3400.59,5927.67) 3409,5917.26 R130.2@3409,5867.04 ; v5(3747.5,8723.67) R140.2@3747.5,8780
  L6-Mid-Layer 5 (G4) w5: v9(3400.59,5927.67) 3400.59,6613.57 3581,6793.98 3581,6923.66 3975.5,7318.16 3975.5,7853.88 ccw(c3945.35,7853.88) 3945.35,7884.03 3764.94,7884.03 cw(c3764.94,7958.18) 3690.79,7958.18 3690.79,8002.88 cw(c3764.94,8002.88) 3764.94,8077.03 4230.07,8077.03 ccw(c4230.07,8107.18) 4260.22,8107.18 4260.22,8151.88 ccw(c4230.07,8151.88) 4230.07,8182.03 4049.65,8182.03 cw(c4049.65,8256.18) 3975.5,8256.18 3975.5,8306.1 3975.5,8417.5 3747.5,8645.5 v5(3747.5,8723.67)
R_IN2_P: R126.2 R136.1 R137.2 R192.2 | length 4276.6
  L1-Top Layer (GTL) w10: v9(3444.59,5927.67) 3449,5925.26 R126.2@3449,5866.69
  L1-Top Layer (GTL) w11: v9(3444.59,5927.67) R136.1@3444.59,5951.23 ; v5(4247.5,8723.67) R137.2@4247.5,8780
  L6-Mid-Layer 5 (G4) w5: v9(3444.59,5927.67) 3444.59,6595.34 3625,6775.75 3625,6905.43 4019.5,7299.93 4019.5,7853.88 ccw(c3945.35,7853.88) 3945.35,7928.03 3764.94,7928.03 cw(c3764.94,7958.18) 3734.79,7958.18 3734.79,8002.88 cw(c3764.94,8002.88) 3764.94,8033.03 4230.07,8033.03 ccw(c4230.07,8107.18) 4304.22,8107.18 4304.22,8151.88 ccw(c4230.07,8151.88) 4230.07,8226.03 4049.65,8226.03 cw(c4049.65,8256.18) 4019.5,8256.18 4019.5,8306.1 4019.5,8417.5 4247.5,8645.5 v5(4247.5,8723.67)
SCLK: R61.2 U5.1 | length 69.1
  L1-Top Layer (GTL) w11: U5.1@1471.28,2424.3 1471.28,2445.28 1486.91,2460.91 R61.2@1486.91,2486.9
SMA_IN0_N: J5.1 R30.1 | length 4373.5
  L1-Top Layer (GTL) w11: R30.1@3905.16,5991.65 3917.4,6003.89 3928.25,6003.89 5975.5,8051.14 5975.5,8278.05 ccw(c5943.25,8278.05) 5943.25,8310.3 5843.05,8310.3 cw(c5843.05,8386.55) 5766.8,8386.55 5766.8,8433.05 cw(c5843.05,8433.05) 5843.05,8509.3 5943.25,8509.3 ccw(c5943.25,8541.55) 5975.5,8541.55 5975.5,8608 5866.75,8716.75 5846.92,8736.58 ccw(c5841.99,8731.64) 5837.05,8736.58 cw(c5826.91,8746.73) 5816.76,8736.58 5808.06,8745.28 cw(c5818.21,8755.42) 5808.06,8765.57 ccw(c5803.13,8770.5) 5808.06,8775.44 5798.5,8785 5747.5,8834 J5.1@5747.5,9057.57
SMA_IN0_P: J4.1 R26.1 | length 4382.9
  L1-Top Layer (GTL) w11: R26.1@3948.61,5951.18 3960.85,5963.42 3960.85,5974.27 6019.5,8032.92 6019.5,8278.05 ccw(c5943.25,8278.05) 5943.25,8354.3 5843.05,8354.3 cw(c5843.05,8386.55) 5810.8,8386.55 5810.8,8433.05 cw(c5843.05,8433.05) 5843.05,8465.3 5943.25,8465.3 ccw(c5943.25,8541.55) 6019.5,8541.55 6019.5,8608 6247.5,8836 J4.1@6247.5,9057.57
SMA_IN1_N: J7.1 R37.1 | length 4322.5
  L1-Top Layer (GTL) w11: R37.1@3801.03,6040.81 3816.14,6055.92 3816.14,6068.8 4189.07,6441.72 4189.07,6487.36 ; 4189,6487.36 4189,6906.5 5006.42,7723.91 5019.31,7736.8 5019.31,7982.62 ccw(c4943.06,7982.62) 4943.06,8058.87 4840,8058.87 cw(c4840,8091.12) 4807.75,8091.12 4807.75,8137.62 cw(c4840,8137.62) 4840,8169.87 5154.61,8169.87 ccw(c5154.61,8246.12) 5230.86,8246.12 5230.86,8292.62 ccw(c5154.61,8292.62) 5154.61,8368.87 5051.56,8368.87 cw(c5051.56,8401.12) 5019.31,8401.12 5019.31,8454.5 5019.31,8493 5019.31,8607.8 5247.5,8836 J7.1@5247.5,9057.57
SMA_IN1_P: J6.1 R33.1 | length 4311.1
  L1-Top Layer (GTL) w11: R33.1@3757.03,6082.81 3772.14,6097.92 3782.95,6097.92 4145,6459.98 4145,6924.72 4975.31,7755.03 4975.31,7982.62 ccw(c4943.06,7982.62) 4943.06,8014.87 4840,8014.87 cw(c4840,8091.12) 4763.75,8091.12 4763.75,8137.62 cw(c4840,8137.62) 4840,8213.87 5154.61,8213.87 ccw(c5154.61,8246.12) 5186.86,8246.12 5186.86,8292.62 ccw(c5154.61,8292.62) 5154.61,8324.87 5051.56,8324.87 cw(c5051.56,8401.12) 4975.31,8401.12 4975.31,8454.5 4975.31,8493 4975.31,8608.2 4745,8772 J6.1@4747.5,9057.57
SMA_IN2_N: J39.1 R140.1 | length 225.9
  L1-Top Layer (GTL) w11: R140.1@3747,8829.68 3747,8905 ; 3747.5,8907 J39.1@3747.5,9057.57
SMA_IN2_P: J37.1 R137.1 | length 217.6
  L1-Top Layer (GTL) w11: R137.1@4247.5,8840 4247.5,8907 J37.1@4247.5,9057.57
SMA_IN3_N: J40.1 R142.1 | length 217.6
  L1-Top Layer (GTL) w11: R142.1@3247.5,8840 3247.5,8907 J40.1@3247.5,9057.57
SMA_IN3_P: J38.1 R139.1 | length 217.6
  L1-Top Layer (GTL) w11: R139.1@2747.5,8840 2747.5,8907 J38.1@2747.5,9057.57
SMA_O0_N: J11.1 R82.1 R128.2 | length 217.6
  L1-Top Layer (GTL) w11: J11.1@103.43,3612.5 254,3612.5 R128.2@321,3612.5
SMA_O0_P: J9.1 R78.1 R132.2 | length 227.9
  L1-Top Layer (GTL) w11: J9.1@103.43,4112.5 254,4112.5 R132.2@331.31,4112.5
SMA_O1_N: C100.1 J12.1 R85.1 | length 217.6
  L1-Top Layer (GTL) w11: J12.1@103.43,3112.5 254,3112.5 C100.1@321,3112.5
SMA_O1_P: C98.1 J10.1 R79.1 | length 217.6
  L1-Top Layer (GTL) w11: J10.1@103.43,2612.5 254,2612.5 C98.1@321,2612.5
SMA_O2_N: C103.1 J15.1 R90.1 | length 219.6
  L1-Top Layer (GTL) w11: C103.1@6677,3112.5 6744,3112.5 J15.1@6896.57,3112.5
SMA_O2_P: C101.1 J13.1 R86.1 | length 219.6
  L1-Top Layer (GTL) w11: C101.1@6677,2612.5 6744,2612.5 J13.1@6896.57,2612.5
SMA_O3_N: C104.1 J16.1 R92.1 | length 227.9
  L1-Top Layer (GTL) w11: C104.1@6668.63,3612.5 6744,3612.5 J16.1@6896.57,3612.5
SMA_O3_P: C102.1 J14.1 R88.1 | length 227.9
  L1-Top Layer (GTL) w11: C102.1@6668.63,4112.5 6744,4112.5 J14.1@6896.57,4112.5
SMA_O4_N: C107.1 J19.1 R99.1 | length 219.6
  L1-Top Layer (GTL) w11: C107.1@6677,5612.5 6744,5612.5 J19.1@6896.57,5612.5
SMA_O4_P: C105.1 J17.1 R94.1 | length 219.6
  L1-Top Layer (GTL) w11: C105.1@6677,6112.5 6744,6112.5 J17.1@6896.57,6112.5
SMA_O5_N: C108.1 J20.1 R101.1 | length 219.6
  L1-Top Layer (GTL) w11: C108.1@6677,5112.5 6744,5112.5 J20.1@6896.57,5112.5
SMA_O5_P: C106.1 J18.1 R96.1 | length 219.6
  L1-Top Layer (GTL) w11: C106.1@6677,4612.5 6744,4612.5 J18.1@6896.57,4612.5
SMA_O6_N: C111.1 J23.1 R109.1 | length 219.6
  L1-Top Layer (GTL) w11: C111.1@6677,7112.5 6744,7112.5 J23.1@6896.57,7112.5
SMA_O6_P: C109.1 J21.1 R103.1 | length 219.6
  L1-Top Layer (GTL) w11: C109.1@6677,6612.5 6744,6612.5 J21.1@6896.57,6612.5
SMA_O7_N: C112.1 J24.1 R111.1 | length 219.6
  L1-Top Layer (GTL) w11: C112.1@6677,7612.5 6744,7612.5 J24.1@6896.57,7612.5
SMA_O7_P: C110.1 J22.1 R105.1 | length 219.6
  L1-Top Layer (GTL) w11: C110.1@6677,8112.5 6744,8112.5 J22.1@6896.57,8112.5
SMA_O8_N: C115.1 J27.1 R117.1 | length 217.6
  L1-Top Layer (GTL) w11: C115.1@1747.5,8840 1747.5,8907 J27.1@1747.5,9057.57
SMA_O8_P: C113.1 J25.1 R113.1 | length 217.6
  L1-Top Layer (GTL) w11: C113.1@2247.5,8840 2247.5,8907 J25.1@2247.5,9057.57
SMA_O9_N: C116.1 J28.1 R119.1 | length 217.6
  L1-Top Layer (GTL) w11: C116.1@1247.5,8840 1247.5,8907 J28.1@1247.5,9057.57
SMA_O9_P: C114.1 J26.1 R115.1 | length 217.6
  L1-Top Layer (GTL) w11: C114.1@747.5,8840 747.5,8907 J26.1@747.5,9057.57
SMA_O10_N: C119.1 J31.1 R125.1 | length 217.6
  L1-Top Layer (GTL) w11: J31.1@103.43,7612.5 254,7612.5 C119.1@321,7612.5
SMA_O10_P: C117.1 J29.1 R121.1 | length 217.6
  L1-Top Layer (GTL) w11: J29.1@103.43,8112.5 254,8112.5 C117.1@321,8112.5
SMA_O11_N: C120.1 J32.1 R127.1 | length 217.6
  L1-Top Layer (GTL) w11: J32.1@103.43,7112.5 254,7112.5 C120.1@321,7112.5
SMA_O11_P: C118.1 J30.1 R122.1 | length 217.6
  L1-Top Layer (GTL) w11: J30.1@103.43,6612.5 254,6612.5 C118.1@321,6612.5
SMA_O12_N: C123.1 J35.1 R133.1 | length 217.6
  L1-Top Layer (GTL) w11: J35.1@103.43,5612.5 254,5612.5 C123.1@321,5612.5
SMA_O12_P: C121.1 J33.1 R129.1 | length 217.6
  L1-Top Layer (GTL) w11: J33.1@103.43,6112.5 254,6112.5 C121.1@321,6112.5
SMA_O13_N: C124.1 J36.1 R135.1 | length 217.6
  L1-Top Layer (GTL) w11: J36.1@103.43,5112.5 254,5112.5 C124.1@321,5112.5
SMA_O13_P: C122.1 J34.1 R131.1 | length 217.6
  L1-Top Layer (GTL) w11: J34.1@103.43,4612.5 254,4612.5 C122.1@321,4612.5
SMA_XO_P: C70.1 J8.1 | length 211.7
  L1-Top Layer (GTL) w11: J8.1@3479,2967.4 C70.1@3479,3179.05
U2A_3V3: C97.1 C130.1 C142.2 C143.2 C144.2 R57.2 R58.2 R59.2 R60.2 R165.1 R166.2 R212.2 TP41.1 U6.1 U8.11 U8.18 U8.50 | length 4978
  L1-Top Layer (GTL) w8: C130.1@1031.51,1149 C130.1@1039,1141.51
  L1-Top Layer (GTL) w10: U8.50@1682.55,906.61 1682.55,954.77 v3(1690.82,963.04) 1682.71,971.15 C144.2@1682.71,1010.35
  L1-Top Layer (GTL) w11: U6.1@965.78,1149 C130.1@1031.51,1149 ; U8.11@1682.55,377.09 U8.11@1682.71,376.93 ; C142.2@1682.71,283.35 C142.2@1687.71,278.35 ; C143.2@1820.35,280.71 C143.2@1822.71,278.35
  L1-Top Layer (GTL) w12: C142.2@1682.71,283.35 U8.11@1682.71,376.93 ; C143.2@1820.35,280.71 U8.18@1820.35,377.09
  L1-Top Layer (GTL) w20: C130.1@1039,1141.51 1168.52,1141.51 TP41.1@1180.98,1153.97 ; R60.2@1259.5,2085 1216,2085 1169.5,2038.5 R59.2@1169.5,2010 1169.5,1959.5 1064,1854 1064,1395 1180.98,1278.02 TP41.1@1180.98,1153.97 ; v3(1508,1244) 1415,1244 1324.97,1153.97 TP41.1@1180.98,1153.97 ; R58.2@1682.97,1178.52 v3(1682.97,1238.28) ; v3@1684.13,1237.12 v3(1866.51,1237.12) R57.2@1866.51,1177.36 ; C142.2@1687.71,278.35 1689.21,276.85 v7@1722.71,276.85 ; v7(1784.71,276.85) 1821.21,276.85 C143.2@1822.71,278.35 ; v3(1949.05,157) R166.2@2029.5,157
  L1-Top Layer (GTL) w30: v7(1034.71,275.85) 1088.72,275.85 R165.1@1089.72,276.85
  L8-Bottom Layer (GBL) w20: v7@1035.71,276.85 v7(1724.71,276.85) ; v3(1508,1244) 1513.72,1238.28 v3(1682.97,1238.28) ; v3(1866.51,1237.12) 1866.51,1200.08 1836.9,1170.47 1836.9,1094.1 1705.84,963.04 1747,921.88 1747,538 1680.28,471.28 1680.28,353.72 1724.71,309.29 v7(1724.71,276.85) ; v3(1949.05,157) 1829.2,276.85 v7(1784.71,276.85) v7(1724.71,276.85)
  L8-Bottom Layer (GBL) w25: R212.2@1491.5,1473 1491.5,1260.5 v3(1508,1244) ; v3(1690.82,963.04) 1705.84,963.04
U2A_I2CPU: U5.2 U8.42 | length 2414.9
  L1-Top Layer (GTL) w11: v3(1294,1063) 1294,1023 1461,856 1479,856 1523,812 1803,812 1840.03,849.03 U8.42@1840.03,906.61 ; v7(1425.41,2401.9) 1440.41,2386.9 U5.2@1471.28,2386.9
  L8-Bottom Layer (GBL) w11: v3(1294,1063) 1294,1247 1257,1284 1257,1358 1083,1532 1083,2142 1342.9,2401.9 v7(1425.41,2401.9)
U2A_SCLBRD: U8.38
U2A_SDABRD: U8.37
U2AADC0: R161.2 | length 4.2
  L1-Top Layer (GTL) w11: R161.2@1272.71,215.35 R161.2@1275.71,212.35
U2AADC1: R162.2
U2AGPIO0: J42.20 JP5.A01 R57.1 R155.1 | length 1715.7
  L1-Top Layer (GTL) w12: v3(1228.36,1554.64) JP5.A01@1228.36,1665.92 ; R155.1@1802.71,1073.35 1803.71,1074.35 v7(1803.71,1127.85) R57.1@1803.71,1177.16
  L8-Bottom Layer (GBL) w12: J42.20@1429,1973.04 1378,1973.04 1378,1844 1369,1835 1296,1835 1280,1819 1280,1580 1253.72,1580 v3(1228.36,1554.64) 1292,1491 1292,1288 1500,1080 1755.86,1080 v7(1803.71,1127.85)
U2AGPIO1: J42.19 JP5.A02 R58.1 R156.1 | length 1193.9
  L1-Top Layer (GTL) w12: v3(1327,1535) 1327,1664.56 JP5.A02@1327.99,1665.55 ; R156.1@1742.71,1073.35 1745.71,1076.35 v7(1745.71,1123.85) R58.1@1745.71,1178.26
  L8-Bottom Layer (GBL) w12: J42.19@1429,1702.96 1389.96,1702.96 1379,1692 1379,1587 v3(1327,1535) 1327,1305 1458,1174 1695.56,1174 v7(1745.71,1123.85)
U2AGPIO2: J42.18 JP5.A04 R154.2 | length 1537.6
  L1-Top Layer (GTL) w11: JP5.A04@1528.36,1665.92 1530,1664.28 1529,1663.28 v10(1529,1549) 1529,1390.28 1530,1389.28 1528.36,1387.64 1560,1356 1828,1356 1934,1250 1934,1150 1908.85,1124.85 1873.85,1124.85 1857.71,1108.71 R154.2@1857.71,1073.35 R154.2@1860.71,1076.35
  L8-Bottom Layer (GBL) w11: J42.18@1519,1911 1529,1921 J42.18@1529,1973.04 1564.96,1973.04 1579,1959 1579,1584 1544,1549 v10(1529,1549)
U2AGPIO3: J42.17 R76.1 R153.2 | length 5573.9
  L1-Top Layer (GTL) w10: v3(337.14,1579.72) R76.1@337.14,1641.22
  L1-Top Layer (GTL) w11: v10(1137,1402) 1200.35,1465.35 1349.75,1465.35 v10(1393.4,1509) ; R153.2@2094.21,691.85 v3(2150.85,691.85)
  L8-Bottom Layer (GBL) w11: v10(1137,1402) 514.86,1402 v3(337.14,1579.72) 128,1370.58 128,584 265,447 265,163 342,86 1975,86 2150.85,261.85 v3(2150.85,691.85) ; v10(1393.4,1509) 1443,1509 1481,1547 1481,1692 1491.96,1702.96 J42.17@1529,1702.96
U2AGPIO4: J42.14 JP5.A05 R157.2 | length 1120.1
  L1-Top Layer (GTL) w10: v3(1628.36,1548.7) JP5.A05@1628.36,1665.92
  L1-Top Layer (GTL) w12: R157.2@1617.71,1073.35 1618.71,1074.35 v3(1618.71,1300.29)
  L8-Bottom Layer (GBL) w10: v3(1628.36,1548.7) 1660.7,1548.7 1679,1567 1679,1959 1693.04,1973.04 J42.14@1729,1973.04
  L8-Bottom Layer (GBL) w12: v3(1618.71,1300.29) 1618.71,1340.71 1649,1371 1649,1477.72 1628.36,1498.36 v3(1628.36,1548.7)
U2AGPIO5: J42.13 JP5.A06 R158.2 | length 917.8
  L1-Top Layer (GTL) w11: v3(1728.36,1550) JP5.A06@1728.36,1665.92
  L1-Top Layer (GTL) w12: R158.2@1557.71,1073.35 R158.2@1558.71,1074.35 ; R158.2@1557.71,1075.35 R158.2@1558.71,1074.35 ; v3(1558.71,1300.29) R158.2@1558.71,1074.35
  L8-Bottom Layer (GBL) w11: v3(1558.71,1300.29) 1594,1265 1644,1265 1728.36,1349.36 v3(1728.36,1550) 1728.36,1702.32 J42.13@1729,1702.96
U2AGPIO5/SOMI: JP5.B06 R71.2 | length 1091.3
  L1-Top Layer (GTL) w11: JP5.B06@1728.36,1880.88 1728.36,1801.64 1742,1788 1908,1788 1966,1846 1966,1942 2025,2001 2307,2001 2472.55,2166.55 R71.2@2521.71,2166.55
U2AGPIO6: J42.12 JP5.A07 R151.2 | length 1823.6
  L1-Top Layer (GTL) w10: R151.2@2094.21,611.85 R151.2@2098.21,615.85
  L1-Top Layer (GTL) w11: JP5.A07@1828.36,1665.92 1810.86,1648.42 1810.86,1536.1 1798.4,1523.64 v10(1798.4,1518.5) 1801.7,1518.5 2198,1122.2 2198,659 2150.85,611.85 R151.2@2094.21,611.85
  L8-Bottom Layer (GBL) w11: v10(1798.4,1518.5) 1798.4,1523.64 1779,1543.04 1779,1965 1787.04,1973.04 J42.12@1829,1973.04
U2AGPIO7: J42.11 R52.1 R152.2 | length 1820.8
  L1-Top Layer (GTL) w11: R152.2@2094.8,506.26 2227.26,506.26 v10(2276,555) 2369.55,648.55 R52.1@2523.52,648.55
  L8-Bottom Layer (GBL) w11: J42.11@1829,1702.96 1829,1532 1993,1368 1993,960 2276,677 v10(2276,555)
U2AGPIO8: J42.26 R64.1 R164.2 | length 4664.2
  L1-Top Layer (GTL) w11: R164.2@1507.71,215.35 1507.71,138.95 1589.66,57 v3(2408,57)
  L1-Top Layer (GTL) w20: v3(2466,1399) 2519.2,1399 R64.1@2521.08,1397.12
  L8-Bottom Layer (GBL) w10: 2431,1399 v3(2466,1399)
  L8-Bottom Layer (GBL) w11: J42.26@1129,1973.04 1129,2101 1210,2182 2372,2182 2430,2124 2430,79 v3(2408,57)
U2AGPIO9: R163.2
U2AGPIO10: R160.2
U2AGPIO11: R159.2 | length 2.8
  L1-Top Layer (GTL) w11: R159.2@1565.71,213.35 R159.2@1567.71,215.35
U2AGPIO12: R150.2
V18: C140.2 U8.67 | length 122.1
  L1-Top Layer (GTL) w11: C140.2@1317.21,707.85 C140.2@1305.71,719.35 1351,719.35 1359.61,710.75 U8.67@1407.95,710.75
VBUS: C131.1 C133.2 D11.1 FB13.1 J41.1 U7.6 U8.65 | length 1657.9
  L1-Top Layer (GTL) w11: U7.6@447.81,759.69 466.31,759.69 v7(476,750) ; v13(1360.4,750.12) U8.65@1407.95,750.12
  L1-Top Layer (GTL) w20: v1(285,830) 307.5,830 308.5,831 309,830.5 ; J41.1@308.36,792.99 309,793.63 v1(309,818) 309,830.5 ; FB13.1@820.5,1022.59 764.72,1022.59 C131.1@755.13,1013.01 v3(755.13,936.59) 723.18,904.64 D11.1@567.86,904.64 508.89,904.64 474.54,870.29 C133.2@434.1,870.29 393.81,830 v1(335,830) 309.5,830 309,830.5
  L8-Bottom Layer (GBL) w11: v3(755.13,936.59) 766.41,936.59 919,784 1192,784 1225.88,750.12 v13(1360.4,750.12)
  L8-Bottom Layer (GBL) w20: v1(335,830) 435,830 476,789 v7(476,750)
VBUS_FILT: C129.2 FB13.2 R145.1 U6.6 | length 170.1
  L1-Top Layer (GTL) w12: 855.5,1149.59 856.09,1149 U6.6@875.22,1149
  L1-Top Layer (GTL) w15: R145.1@820.5,1143.09 849,1143.09 855.5,1149.59
  L1-Top Layer (GTL) w20: R145.1@820.5,1143.09 820.5,1086.62 C129.2@876.46,1086.62
VCC_XO: C78.1 FB12.2 JP4.2 JP4.4 JP4.6 JP4.8 R15.1 | length 1585.1
  L1-Top Layer (GTL) w20: 4301.42,2754.85 4300.76,2755.51 ; JP4.2@4347.7,2247.6 4263.7,2247.6 4163.7,2347.6 ; JP4.4@4347.7,2347.6 4163.7,2347.6 ; JP4.6@4347.7,2447.6 4252.8,2447.6 4152.8,2347.6 ; FB12.2@4361.69,3098.59 4360.76,3097.67 C78.1@4360.76,3032.57 4360.76,2928.76 4300.76,2868.76 4300.76,2755.51 ; 4152.8,2347.6 4163.7,2347.6 ; 4152.8,2347.6 4098.9,2347.6 4082.26,2364.24 4082.26,2492.06 4300.76,2710.56 4300.76,2755.51
VCC_XO_FILT: C79.2 C80.1 FB12.1 R44.1 R206.1 R207.1 R208.1 R209.1 R210.1 R211.1 | length 3145.8
  L1-Top Layer (GTL) w12: C80.1@4426.5,3286.39 C79.2@4480.99,3286.39
  L1-Top Layer (GTL) w20: v7(3620.32,2603.43) 3620.32,2737.51 3679.59,2796.79 3679.59,2910.14 ; R211.1@3671,3057.5 3671,2918.73 3679.59,2918.73 3791,2918.73 3839.73,2870 3970,2870 3991.5,2891.5 R207.1@3991.5,2927 4154.28,2927 4255.86,3028.58 R44.1@4255.86,3110.68 4297.83,3110.68 4311.07,3123.92 4311.07,3143.29 4329.37,3161.59 FB12.1@4361.69,3161.59 4361.69,3207.31 4450.29,3207.31 4480.99,3238.01 C79.2@4480.99,3286.39 4535.16,3286.39 4556.26,3307.49 4556.26,3449.27 4380.69,3624.84 R208.1@3891.56,3624.84 3891.56,3694.44 v5(3711.5,3874.5) ; R206.1@4370.5,3285 4425.11,3285 C80.1@4426.24,3286.13 C80.1@4426.5,3286.39
  L8-Bottom Layer (GBL) w20: R210.1@3619.07,2516.5 v7@3619.07,2602.18 ; v5(3711.5,3874.5) R209.1@3711.5,3928
VCORE: C141.2 U8.20 | length 105.9
  L1-Top Layer (GTL) w11: U8.20@1859.72,377.09 1859.72,344.84 1877.05,327.51 C141.2@1877.05,278.35
VDD_APLL1_XO: C47.1 C48.2 FB7.2 TP14.1 U1.8 | length 637.5
  L1-Top Layer (GTL) w8: U1.8@3473.31,5273.62 3473.31,5232.16 3469.57,5228.42 3469.57,5186.89 C48.2@3480.34,5176.12 3509.84,5176.12 3547.05,5138.91 3547.05,5091.95
  L1-Top Layer (GTL) w11: 3547.05,5091.95 3580.54,5058.46 3580.54,4841.57 3577,4838.03 TP14.1@3577,4825.94 3577,4766.78 C47.1@3566.8,4756.58
  L1-Top Layer (GTL) w20: FB7.2@3566.8,4706.65 C47.1@3566.8,4756.58
VDD_APLL2: C53.1 C54.2 FB9.2 TP16.1 U1.23 | length 584.4
  L1-Top Layer (GTL) w8: U1.23@3656.38,5417.32 3682.99,5417.32 C54.2@3699.16,5401.15 ; C54.2@3700.16,5402.15 3712.11,5414.1 3721.9,5414.1
  L1-Top Layer (GTL) w11: 3721.9,5414.1 3753.94,5382.06 3830.76,5382.06 TP16.1@3958,5254.82
  L1-Top Layer (GTL) w20: TP16.1@3957.71,5255.11 4019.71,5193.11 FB9.2@4138.22,5193.11
VDD_APLL3: C59.1 C60.2 FB11.2 TP18.1 U1.47 | length 505.9
  L1-Top Layer (GTL) w8: TP18.1@3195.39,5907.81 TP18.1@3191.41,5903.83 3191.41,5814.06 3242.18,5763.29 3275.33,5763.29 3346,5692.62 3346,5682.82 C60.2@3335.09,5671.91 ; C60.2@3332.09,5668.91 3355.2,5645.8 U1.47@3355.2,5620.08
  L1-Top Layer (GTL) w20: TP18.1@3195.39,5907.81 3195.39,5931.39 3204.69,5940.69 C59.1@3204.69,5973.89 FB11.2@3204.69,6025.89
VDD_DIG: C41.1 C42.2 FB5.2 TP12.1 U1.41 | length 532.8
  L1-Top Layer (GTL) w8: U1.41@3473.31,5620.08 3473.31,5728.73 C42.2@3476.04,5731.46 3492.2,5731.46 3498,5737.26 3498,5910 3544.7,5956.7
  L1-Top Layer (GTL) w20: 3544.7,5956.7 TP12.1@3544.7,5995.31 C41.1@3544.7,6060.78 FB5.2@3544.7,6113.87
VDD_IN0: C29.1 C30.2 FB1.2 TP8.1 U1.33 | length 1079.2
  L1-Top Layer (GTL) w7: U1.33@3630.79,5620.08 3630.79,5637.7 3642.28,5649.19 C30.2@3659.66,5649.19 3665,5654.53 3665,5661.13 v1(3708.87,5705)
  L1-Top Layer (GTL) w20: v3(3854.25,6343.27) TP8.1@3888.33,6377.35 ; C29.1@3887.43,6434.97 FB1.2@3887.43,6486.34 ; TP8.1@3888.73,6377.75 C29.1@3888.73,6433.67
  L8-Bottom Layer (GBL) w15: v1(3689.88,5686.01) 3737.67,5733.8 3737.67,5776.48 3878.86,5917.67 3878.86,6318.67 v3(3854.25,6343.27) ; v3@3858.25,6343.27 v3(3854.25,6343.27) ; v1(3888.33,6373.35) 3884.33,6373.35 v3(3854.25,6343.27)
VDD_IN1: C35.1 C36.2 FB3.2 TP10.1 U1.37 | length 893.4
  L1-Top Layer (GTL) w8: U1.37@3552.05,5620.08 3552.05,5688.28 3572,5708.23 3572,5739.53 3598.72,5766.25 3615.88,5766.25 3648,5798.37 v1(3648,5828)
  L1-Top Layer (GTL) w15: v1@3648.24,6198 v3(3648.24,6230.29) 3661.18,6243.23 TP10.1@3661.18,6278.63 3651.61,6288.2 C35.1@3651.61,6344.14 FB3.2@3651.61,6392.68
  L8-Bottom Layer (GBL) w15: v1(3648.24,5798.61) v3(3648.24,6230.29)
  other v1: 3648,6198
VDD_IN23: C56.1 C57.2 FB10.2 TP17.1 U1.44 | length 621.7
  L1-Top Layer (GTL) w8: 3321.81,5935.19 3351.02,5905.98 3363.78,5905.98 3389.62,5880.14 3389.62,5776.35 3417.53,5748.44 3417.53,5739.93 3405.67,5728.07 3414.25,5719.49 U1.44@3414.25,5620.08
  L1-Top Layer (GTL) w20: 3321.81,5935.19 TP17.1@3321.81,6066.45 ; TP17.1@3322.5,6067.14 FB10.2@3322.5,6186.86
VDD_PLANE: C6.2 JP1.2 JP1.4 JP1.6 NT1.2 R11.2 R13.1 R16.2 R18.2 R20.2 R22.2 R24.1 R25.2 R54.2 TP2.1 | length 6508
  L1-Top Layer (GTL) w20: v3(3111.56,6203.21) R25.2@3160.02,6203.21 ; v3(3160.02,6251.66) R25.2@3160.02,6203.21 ; v3(3208.47,6203.21) R25.2@3160.02,6203.21 ; v3(3366.19,6410) 3332.38,6376.19 v3(3366.64,6341.93) ; v3(3511.08,6359.28) R18.2@3511.08,6310.83 v3(3559.53,6310.83) ; v3(3564.11,4498.42) 3612.56,4498.42 v3(3612.56,4449.96) ; R20.2@3612.65,4498.77 v3(3661.1,4498.77) ; v3(3644.73,6589.9) R16.2@3693.18,6589.9 ; R16.2@3692.17,6590.39 R16.2@3692.96,6590.39 ; v3(3692.96,6638.84) R16.2@3692.96,6590.39 ; v3(3740.62,6590.39) R16.2@3692.96,6590.39 ; v3(3832.36,6729.45) R11.2@3832.36,6681 3865,6681 3877,6693 v3(3877,6720.87) ; R22.2@4336.33,5210.12 v3(4336.33,5258.57) ; v3(4336.68,5161.57) 4336.68,5210.03 v3(4385.14,5210.03) ; R54.2@4421.86,1744.56 v3(4421.86,1803.14) ; R13.1@4421.86,1983.18 v3(4421.86,2044.56) ; v3(4584.65,935.35) NT1.2@4584.65,1001.42 4711.74,1001.42 TP2.1@4738.19,1027.87 ; v3(4842,5104) C6.2@4884.5,5104 ; v3(4884.5,5061.5) C6.2@4884.5,5104 ; v3(4884.5,5146.5) C6.2@4884.5,5104
  L3-Mid-Layer 2 (G1) w50: v3@3208.47,6207.21 3316.01,6207.21 3374.52,6148.7 4518,6148.7 ; v3@3375,6410 3425.45,6460.45 4480,6460.45 ; v3(3511.08,6359.28) 3737.03,6359.28 3819.18,6277.13 4450,6277.13 ; 3692.96,6618.84 v3(3692.96,6638.84) ; v3@3740.62,6590.84 4427,6590.84
  L3-Mid-Layer 2 (G1) w100: v3(3612.56,4449.96) 4603,4449.96
  other v4: 4698.19,962.87 4934.33,968.5 5007.67,968.5 5081,968.5 4812,969 4934.17,1056.11 5007.51,1056.11 5080.84,1056.11 4698.19,1082.87
VDDGPIO: C89.2 NT1.1 R51.1 R56.2 R63.1 R67.2 R68.1 R70.1 R74.2 R75.1 U5.5 | length 10571.7
  L1-Top Layer (GTL) w20: v3(224.42,1844.22) R75.1@262.93,1844.22 ; v17(1540.41,2466.9) 1579.3,2466.9 ; U5.5@1579.54,2424.3 C89.2@1579.54,2520.22 ; v3(2068.77,2493.21) R68.1@2068.77,2531.71 ; v3@2458,2266.55 R70.1@2522.95,2266.55 ; v3(2464,1498) 2516.1,1498 R63.1@2518.28,1495.82 ; v3(2485.01,748.55) R51.1@2523.52,748.55 ; R56.2@3362.01,529.08 3362.01,581.01 v3(3409,628) 4180,628 4456.49,904.49 4456.49,1001.42 ; R67.2@3362.01,1265.08 3362.01,1315.01 3389,1342 3748,1342 4088.58,1001.42 4456.49,1001.42 ; R74.2@3364.52,2059.81 3364.52,2103.52 3399,2138 3723,2138 4456.49,1404.51 4456.49,1001.42 ; NT1.1@4513.79,1001.42 4456.49,1001.42
  L8-Bottom Layer (GBL) w20: v3(224.42,1844.22) 224.42,2138.42 552.9,2466.9 v17(1540.41,2466.9) 1650.31,2357 1972,2357 2024,2409 2024,2473 2044.21,2493.21 v3(2068.77,2493.21) 2068.77,2410.23 2212.45,2266.55 2484.44,2266.55 2555,2195.99 2555,818.54 v3(2485.01,748.55) 2650.45,748.55 2771,628 v3(3409,628) ; v3(2464,1498) 2551.65,1498 2553.82,1495.82
  other v3: 2458,2267
VDDO_0_1: C32.1 C33.2 FB2.2 TP9.1 U1.1 | length 567.6
  L1-Top Layer (GTL) w10: 3146,5083 3146,5119.61 3218.76,5194.52 3237.07,5194.52 3271.6,5229.05 C33.2@3302.41,5229.05 3335.51,5262.15 U1.1@3335.51,5273.62
  L1-Top Layer (GTL) w20: FB2.2@2950.95,4889.24 C32.1@2985.79,4924.08 ; C32.1@2985.79,4924.94 TP9.1@3019.75,4958.9 ; TP9.1@3022.58,4961.73 3146,5083
VDDO_2_3: C38.1 C39.2 FB4.2 TP11.1 U1.11 | length 947.8
  L1-Top Layer (GTL) w8: U1.11@3532.36,5273.62 3532.36,5254.03 3538.94,5247.45 3538.94,5207.3 3569.82,5176.42 3569.82,5126.18 v1(3579.15,5116.85)
  L1-Top Layer (GTL) w11: C38.1@3258.53,4623.46 3258.53,4679.61 TP11.1@3268.02,4689.1
  L1-Top Layer (GTL) w15: TP11.1@3268.02,4689.1 v3(3311.21,4732.29) v14(3342,4732.29)
  L1-Top Layer (GTL) w20: FB4.2@3258.53,4573.78 C38.1@3258.53,4623.46 ; v1(3579.15,5093) v1(3579.15,5116.85)
  L3-Mid-Layer 2 (G1) w15: v3(3311.21,4732.29) 3381.39,4732.29 3579.15,4930.05 v1(3579.15,5116.85)
VDDO_4_TO_7: C44.1 C45.2 FB6.2 TP13.1 U1.28 | length 595.7
  L1-Top Layer (GTL) w8: U1.28@3656.38,5515.75 C45.2@3745.1,5515.75 ; v3@3997.12,5557.76 v3@3997.96,5557.76
  L1-Top Layer (GTL) w11: C45.2@3745.1,5515.75 3745.1,5536.48 3777.71,5569.09 3810.6,5569.09
  L1-Top Layer (GTL) w15: 3810.6,5569.09 3818.64,5577.13
  L1-Top Layer (GTL) w20: 3818.64,5577.13 3942.72,5577.13 3962.09,5557.76 3995.49,5557.76 v3(3995.92,5557.76) v3@3997.12,5557.76 ; v3@3997.96,5557.76 4030.46,5557.76 TP13.1@4067.45,5520.77 4080.27,5533.59 C44.1@4133,5533.59 FB6.2@4185.81,5533.59
VDDO_8_TO_13: C50.1 C51.2 FB8.2 TP15.1 U1.55 | length 543.3
  L1-Top Layer (GTL) w10: FB8.2@2792.53,5523.34 FB8.2@2792.69,5523.18 ; 3100,5523.18 3124.98,5523.18 3158.27,5489.89 C51.2@3188.98,5489.89 3202.49,5476.38 U1.55@3309.92,5476.38
  L1-Top Layer (GTL) w20: FB8.2@2792.69,5523.18 C50.1@2840.69,5523.18 TP15.1@2915.38,5523.18 2919.08,5526.89 2932.67,5526.89 2936.78,5531 3092.18,5531 3100,5523.18
VDDO_PLANE: C21.2 JP2.2 JP2.4 JP2.6 R12.2 R14.1 R17.2 R19.2 R21.2 TP5.1 | length 13953.6
  L1-Top Layer (GTL) w10: R14.1@4421.86,1908.44 4374.43,1908.44 4349.89,1883.9 4349.89,1650.19 4425.49,1574.59 TP5.1@5057.36,1574.59
  L1-Top Layer (GTL) w20: v3(2556.55,5573.42) R21.2@2605,5573.42 v3(2605,5524.97) ; v3(2760.23,4765.68) R12.2@2794.49,4799.94 ; v3(2760.23,4834.21) R12.2@2794.49,4799.94 ; v3(2828.75,4765.68) R12.2@2794.49,4799.94 ; v3(3252.49,4391.32) 3300.94,4391.32 v3(3300.94,4342.86) ; R17.2@3301.03,4391.67 v3(3349.48,4391.67) ; v3(4978.74,5430.34) R19.2@4978.74,5478.79 v3(5027.19,5478.79) ; R19.2@4979,5479 v3(4979,5527.45)
  L3-Mid-Layer 2 (G1) w100: 2567.59,5558.97 2567.59,4929.38 2867.75,4629.22 2867.75,1066.46 ; v3(3300.94,4342.86) 3300.94,3895.99 3151,3746.05 3151,985.3 3321.47,814.83 ; v3@5027.19,5483.79 5094.21,5483.79 5203.86,5374.14 5203.86,1864.65 5050,1710.79 5050,1581.95 TP5.1@5057.36,1574.59
  other v4: 4918,1527 5138.09,1530.05 5138.09,1590.18 4921,1650.31 4986.43,1650.31 5063.87,1650.31 5138.09,1650.31
VIN2: C27.1 D2.1 J3.1 J500.2 JP2.5 TP7.1 | length 3811.8
  L1-Top Layer (GTL) w5: TP7.1@5563.8,1239.2 TP7.1@5567.32,1235.68
  L1-Top Layer (GTL) w40: TP7.1@5563.8,1239.2 5528.12,1274.88 C27.1@5528.12,1336.34 5562.38,1370.6 v11(5612.3,1370.6)
  L1-Top Layer (GTL) w50: JP2.5@5488.3,1640 5593.7,1640 5614.7,1619 v11(5614.7,1596.3) ; v15(5567.32,1145.88) TP7.1@5567.32,1235.68
  L1-Top Layer (GTL) w100: J500.2@5443.7,101.2 5460,117.5 5460,395 5515,450 6460.11,450 6705.62,695.51 6705.62,851.06 6734.56,880 J3.1@6896.57,880 J3.1@6897.17,880
  L8-Bottom Layer (GBL) w50: v11@5614.7,1373 v11(5614.7,1596.3)
  L8-Bottom Layer (GBL) w100: J500.2@5443.7,101.2 5443.7,178.7 5567.32,302.32 v15(5567.32,1145.88)
VIN3: J500.3 JP4.5 | length 3508.7
  L1-Top Layer (GTL) w30: JP4.5@4560.3,2447.6 5639.4,2447.6 5680,2407 5680,1677 v8(5711,1646)
  L8-Bottom Layer (GBL) w30: J500.3@5581.7,101.2 5711,230.5 v8(5711,1646)
VUSB: C134.2 S6.3 S6.4 U8.66 | length 2383.6
  L1-Top Layer (GTL) w11: S6.4@865.1,285.45 v3(967.14,285.45) ; U8.66@1407.95,730.43 1454.13,730.43 1477.71,706.85 1515.15,706.85 1530,692 v3(1530,532)
  L1-Top Layer (GTL) w20: v13(415.7,285.89) S6.3@505.34,285.89 ; S6.3@530,285 S6.4@850,285 ; v13(689.47,961.41) C134.2@689.47,1022.72
  L8-Bottom Layer (GBL) w11: v3(967.14,285.45) 1213.69,532 v3(1530,532)
  L8-Bottom Layer (GBL) w20: v13(415.7,285.89) 544,414.19 544,916.14 589.27,961.41 v13(689.47,961.41)
XO: R40.2 U1.9 | length 1763.3
  L1-Top Layer (GTL) w7: U1.9@3493.18,5273.62 3493.18,5221.24 v16(3501.36,5213.06)
  L1-Top Layer (GTL) w11: R40.2@3479,3523 v4(3479,3559)
  L6-Mid-Layer 5 (G4) w5: v4(3479,3559) 3479,4749 3493.24,4763.24 3493.24,5204.94 v16(3501.36,5213.06)
XO1_P: R40.1 R41.2 R42.2 | length 79.6
  L1-Top Layer (GTL) w11: R41.2@3479,3383.4 R42.2@3479,3423 R40.1@3479,3463
XO2_P: C70.2 C71.1 R41.1 | length 84.3
  L1-Top Layer (GTL) w11: C70.2@3479,3239.05 R41.1@3479,3323.4
XO3: C71.2 R43.1 R46.1 R47.1 R48.1 R49.1 R50.1 | length 286.9
  L1-Top Layer (GTL) w11: C71.2@3539,3282.4 C71.2@3540.81,3284.21 ; C71.2@3539,3284.21 C71.2@3540.81,3284.21 ; C71.2@3541.1,3284.5 C71.2@3540.81,3284.21 ; R43.1@3822.94,3284.21 3720.85,3284.21 3631.08,3284.21 C71.2@3540.81,3284.21
pads on no net: D8.2 FID1.1 FID2.1 FID3.1 FID4.1 FID5.1 FID6.1 J41.4 J41.10 J41.11 J42.1 J42.2 J42.3 J42.5 J42.7 J42.9 J42.10 J42.21 J42.22 J42.23 J42.24 J42.25 J42.29 J42.30 LBL1.0 MH1.1 SH1.0 SH2.0 SH4.0 SH5.0 SH6.0 U4.2 U4.5 U6.2 U6.5 U7.2 U7.5 U8.5 U8.6 U8.7 U8.8 U8.12 U8.13 U8.16 U8.17 U8.22 U8.24 U8.25 U8.26 U8.27 U8.28 U8.30 U8.31 U8.32 U8.34 U8.35 U8.36 U8.39 U8.40 U8.41 U8.43 U8.44 U8.48 U8.53 U8.54 U8.55 U8.56 U8.71 U8.72 U8.73 U8.74 U8.75 U8.77 U8.78 U8.79 U8.80 U500.5 Y1.1 Y1.2 Y1.3 Y1.6 Y1.7 Y1.10 Y5.1 Y5.2 Y5.5 Y5.6
copper on no net:
  other v12: 6349,88.56 6264.61,137.28 6433.39,137.28 6264.61,234.72 6433.39,234.72 6349,283.44

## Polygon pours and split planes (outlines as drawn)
GND on L8-Bottom Layer (GBL) "L8-BOTTOM_LAYER_(GBL)_GND_P026" (solid, remove dead copper, pour order 26): 16,9145 6982,9145 6982,20 6895,20 16,20
GND on L8-Bottom Layer (GBL) "L8-BOTTOM_LAYER_(GBL)_GND_P010" (solid, pour order 10): 3469.7,5245.81 3470.28,5246.39 3522.13,5246.39 3522.13,5237.74 3560.73,5199.14 3560.73,3516.13 3541.72,3497.12 3412.66,3497.12 3385.58,3524.2 3402.29,3540.91 3402.29,5225.64 3424.19,5247.54 3457.6,5247.54 3458.55,5246.59 3469.95,5246.59
GND on L3-Mid-Layer 2 (G1) "L3-MID-LAYER_2_(G1)_GND_P028" (solid, remove dead copper, pour order 28): 16,9145 6982,9145 6982,20 6895,20 16,20
VDD_PLANE on L3-Mid-Layer 2 (G1) "L3-MID-LAYER_2_(G1)_VDD_PLANE_P002" (solid, pour order 2): 5056,858 4426,858 4311,973 4311,6103 4298,6116 4298,6694 3792.9,6694 3792.9,6770.66 4298,6764 4383,6849 4846,6849 4859,6849 4908,6813 4908,1295 5011,1209 5140.5,1110 5140.5,942.5
VDDO_PLANE on L3-Mid-Layer 2 (G1) "L3-MID-LAYER_2_(G1)_VDDO_PLANE_P000" (solid, pour order 0): 1939.1,1280.49 1962.55,1257.04 3786.97,1257.04 4294,964 4417.9,842.1 5095.48,851.64 5176.71,932.87 5176.71,1123 4948.63,1288.64 4889.12,1369 4889.12,1669.98 4889.12,1819.84 4996.99,1927.71 5592.62,1927.71 5372.19,860.54 5129,347.18 5095.48,347.18 2276.78,347.18 1922.21,701.75 1922.21,1225.43
GND on L7-Mid-Layer 6 (G5) "L7-MID-LAYER_6_(G5)_GND_P024" (solid, remove dead copper, pour order 24): 16,9145 6982,9145 6982,20 6895,20 16,20
GND on L4-Mid-Layer 3 (G2) "L4-MID-LAYER_3_(G2)_GND_P018" (solid, remove dead copper, pour order 18): 16,9145 6982,9145 6982,20 6895,20 16,20
GND on L5-Mid-Layer 4 (G3) "L5-MID-LAYER_4_(G3)_GND_P020" (solid, remove dead copper, pour order 20): 16,9145 6982,9145 6982,20 6895,20 16,20
GND on L6-Mid-Layer 5 (G4) "L6-MID-LAYER_5_(G4)_GND_P022" (solid, remove dead copper, pour order 22): 16,9145 6982,9145 6982,20 6895,20 16,20
GND on L1-Top Layer (GTL) "L1-TOP_LAYER_(GTL)_GND_P016" (solid, remove dead copper, pour order 16): 16,9145 6982,9145 6982,20 6895,20 16,20
GND on L2-GND Plane (GP1) (split plane): 6979.9,8165 6790,8165 6790,8060 6979.9,8060 6979.9,7665 6790,7665 6790,7560 6979.9,7560 6979.9,7165 6790,7165 6790,7060 6979.9,7060 6979.9,6665 6790,6665 6790,6560 6979.9,6560 6979.9,6165 6790,6165 6790,6060 6979.9,6060 6979.9,5665 6790,5665 6790,5560 6979.9,5560 6979.9,5165 6790,5165 6790,5060 6979.9,5060 6979.9,4665 6790,4665 6790,4560 6979.9,4560 6979.9,4165 6790,4165 6790,4060 6979.9,4060 6979.9,3665 6790,3665 6790,3560 6979.9,3560 6979.9,3165 6790,3165 6790,3060 6979.9,3060 6979.9,2665 6790,2665 6790,2560 6979.9,2560 6979.9,20.1 20.1,20.1 20.1,2560 210,2560 210,2665 20.1,2665 20.1,3060 210,3060 210,3165 20.1,3165 20.1,3560 210,3560 210,3665 20.1,3665 20.1,4060 210,4060 210,4165 20.1,4165 20.1,4560 210,4560 210,4665 20.1,4665 20.1,5060 210,5060 210,5165 20.1,5165 20.1,5560 210,5560 210,5665 20.1,5665 20.1,6060 210,6060 210,6165 20.1,6165 20.1,6560 210,6560 210,6665 20.1,6665 20.1,7060 210,7060 210,7165 20.1,7165 20.1,7560 210,7560 210,7665 20.1,7665 20.1,8060 210,8060 210,8165 20.1,8165 20.1,9140.9 695,9140.9 695,8951 800,8951 800,9140.9 1195,9140.9 1195,8951 1300,8951 1300,9140.9 1695,9140.9 1695,8951 1800,8951 1800,9140.9 2195,9140.9 2195,8951 2300,8951 2300,9140.9 2695,9140.9 2695,8951 2800,8951 2800,9140.9 3195,9140.9 3195,8951 3300,8951 3300,9140.9 3695,9140.9 3695,8951 3800,8951 3800,9140.9 4195,9140.9 4195,8951 4300,8951 4300,9140.9 4695,9140.9 4695,8951 4800,8951 4800,9140.9 5195,9140.9 5195,8951 5300,8951 5300,9140.9 5695,9140.9 5695,8951 5800,8951 5800,9140.9 6195,9140.9 6195,8951 6300,8951 6300,9140.9 6979.9,9140.9

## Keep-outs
Keep-Out Layer:
  text ".Layer_Name" at 577,-1758.49 h60

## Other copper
L1-Top Layer (GTL):
  rectangle net +12V: 6345.8,1478.8 6375.4,1515.7
  rectangle net GND: 6169.5,1351.9 6310.9,1627.4
  rectangle net GND: 6167.6,1085.3 6335.4,1315.1
  region net GND: 6183,8971 6183,9139 6165,9139 6165,8971
  region net GND: 6330,8971 6330,9139 6312,9139 6312,8971
  region net GND: 5683,8971 5683,9139 5665,9139 5665,8971
  region net GND: 5830,8971 5830,9139 5812,9139 5812,8971
  region net GND: 5183,8971 5183,9139 5165,9139 5165,8971
  region net GND: 5330,8971 5330,9139 5312,9139 5312,8971
  region net GND: 4683,8971 4683,9139 4665,9139 4665,8971
  region net GND: 4830,8971 4830,9139 4812,9139 4812,8971
  region net GND: 4183,8971 4183,9139 4165,9139 4165,8971
  region net GND: 4330,8971 4330,9139 4312,9139 4312,8971
  region net GND: 3683,8971 3683,9139 3665,9139 3665,8971
  region net GND: 3830,8971 3830,9139 3812,9139 3812,8971
  region net GND: 3183,8971 3183,9139 3165,9139 3165,8971
  region net GND: 3330,8971 3330,9139 3312,9139 3312,8971
  region net GND: 2683,8971 2683,9139 2665,9139 2665,8971
  region net GND: 2830,8971 2830,9139 2812,9139 2812,8971
  region net GND: 2183,8971 2183,9139 2165,9139 2165,8971
  region net GND: 2330,8971 2330,9139 2312,9139 2312,8971
  region net GND: 1830,8971 1830,9139 1812,9139 1812,8971
  region net GND: 1683,8971 1683,9139 1665,9139 1665,8971
  region net GND: 1330,8971 1330,9139 1312,9139 1312,8971
  region net GND: 1183,8971 1183,9139 1165,9139 1165,8971
  region net GND: 830,8971 830,9139 812,9139 812,8971
  region net GND: 683,8971 683,9139 665,9139 665,8971
  region net GND: 190,8195 22,8195 22,8177 190,8177
  region net GND: 190,8048 22,8048 22,8030 190,8030
  region net GND: 190,7695 22,7695 22,7677 190,7677
  region net GND: 190,7548 22,7548 22,7530 190,7530
  region net GND: 190,7195 22,7195 22,7177 190,7177
  region net GND: 190,7048 22,7048 22,7030 190,7030
  region net GND: 190,6695 22,6695 22,6677 190,6677
  region net GND: 190,6548 22,6548 22,6530 190,6530
  region net GND: 190,6195 22,6195 22,6177 190,6177
  region net GND: 190,6048 22,6048 22,6030 190,6030
  region net GND: 190,5695 22,5695 22,5677 190,5677
  region net GND: 190,5548 22,5548 22,5530 190,5530
  region net GND: 190,5195 22,5195 22,5177 190,5177
  region net GND: 190,5048 22,5048 22,5030 190,5030
  region net GND: 190,4695 22,4695 22,4677 190,4677
  region net GND: 190,4548 22,4548 22,4530 190,4530
  region net GND: 190,4195 22,4195 22,4177 190,4177
  region net GND: 190,4048 22,4048 22,4030 190,4030
  region net GND: 190,3695 22,3695 22,3677 190,3677
  region net GND: 190,3548 22,3548 22,3530 190,3530
  region net GND: 190,3195 22,3195 22,3177 190,3177
  region net GND: 190,3048 22,3048 22,3030 190,3030
  region net GND: 190,2695 22,2695 22,2677 190,2677
  region net GND: 190,2548 22,2548 22,2530 190,2530
  rectangle net GND: 6810,2677 6978,2695
  rectangle net GND: 6810,2530 6978,2548
  rectangle net GND: 6810,3177 6978,3195
  rectangle net GND: 6810,3030 6978,3048
  rectangle net GND: 6810,3677 6978,3695
  rectangle net GND: 6810,3530 6978,3548
  rectangle net GND: 6810,4177 6978,4195
  rectangle net GND: 6810,4030 6978,4048
  rectangle net GND: 6810,4677 6978,4695
  rectangle net GND: 6810,4530 6978,4548
  rectangle net GND: 6810,5177 6978,5195
  rectangle net GND: 6810,5030 6978,5048
  rectangle net GND: 6810,5677 6978,5695
  rectangle net GND: 6810,5530 6978,5548
  rectangle net GND: 6810,6177 6978,6195
  rectangle net GND: 6810,6030 6978,6048
  rectangle net GND: 6810,6677 6978,6695
  rectangle net GND: 6810,6530 6978,6548
  rectangle net GND: 6810,7177 6978,7195
  rectangle net GND: 6810,7030 6978,7048
  rectangle net GND: 6810,7677 6978,7695
  rectangle net GND: 6810,7530 6978,7548
  rectangle net GND: 6810,8030 6978,8048
  rectangle net GND: 6810,8177 6978,8195
  rectangle net GND: 976,1057.5 986,1128
  region net GND: 986,1118 986,1128 915.5,1128 915.5,1118
  rectangle net GND: 934.46,1086.62 944.46,1125.38
  rectangle net GND: 915.5,1118 925.5,1243
  region net VDDGPIO: 4528.19,1046 4407,1046 4407,939 4528.19,939
  region net GND: 5171.24,1372.03 5061.24,1372.03 5061.24,1307.03 5171.24,1307.03
  region net VDD_PLANE: 5121.85,951.11 5121.85,1071.11 4808.84,1071.11 4808.84,951.11
  region net VDD_PLANE: 4824,1098 4678.19,1098 4678.19,947.87 4824,947.87
  rectangle net VDDO_PLANE: 4897.76,1416.84 5010.03,1671.09
  rectangle net VDDO_PLANE: 4982.7,1410.43 5300.5,1677
  rectangle net VCC_XO: 3990.9,2206.8 4376.5,2591.1
  region net LDO3_IN: 6116.1,892.8 6116.1,634.9 6184.07,634.9 6184.07,892.8
  rectangle net VDD_PLANE: 5035.4,825.2 5215.8,1118.4
  rectangle net GND: 6198.6,1305.2 6334.8,1395.9
  rectangle net GND: 6240.4,1376.4 6334.3,1458.1
  rectangle net GND: 6113.6,918.5 6335.8,1086.45
  rectangle net GND: 6300.8,1455.9 6333.7,1515.4
  rectangle net GND: 6293.2,1512.4 6333.1,1583.3
  rectangle net NetC504_1: 6461.6,1538.3 6544.2,1595.1
  rectangle net +12V: 6384.5,1393.2 6506.6,1456.6
  rectangle net +12V: 6357.8,1447.1 6438.3,1501.2
  rectangle net NetC501_1: 6165.4,1635.5 6205.5,1837.3
  rectangle net NetC501_1: 6098.8,1635.5 6165.4,1807.3
  rectangle net NetC504_1: 6030.1,1099.6 6158.4,1343.1
  rectangle net NetR500_1: 6523.7,1408.6 6611.1,1460.6
  rectangle net NetL501_1: 6300.5,1669.4 6398.7,1836.8
  rectangle net GND: 6610.6,1581.6 6641.7,1699.6
  rectangle net +12V: 6428.4,1454.3 6456.12,1474.9
  rectangle net +12V: 6345.7,1017.5 6608.6,1398.5
  rectangle net +12V: 6345.7,945.5 6535.9,1017.5
  rectangle net +12V: 6526.5,990.1 6580.5,1017.5
  rectangle net +12V: 6533.7,970 6560.4,993.7
  region net NetC501_1: 6323,1636 6323,1649.1 6315.57,1660.6 6292.5,1660.6 6292.5,1837.4 6205.5,1837.3 6205.5,1636
  region net GND: 6559.9,1584.1 6562.9,1584.1 6641.9,1584.1 6641.9,1534.2 6577,1469.3 6523.8,1469.3 6523.8,1527.4 6523.8,1529 6559.9,1529
  pour cut-out: 1232.71,966.85 1092.71,966.85 1092.71,346.85 1232.71,346.85
  pour cut-out: 49.33,977.57 386.64,977.57 386.64,482.43 385.07,484 50,484 49,483
  text ".Layer_Name" at 326,-1754.49 h60
L3-Mid-Layer 2 (G1):
  region net VDDO_PLANE: 5057,5403 5057,5559.89 4949.42,5559.89 4949.42,5403
  rectangle net VDD_PLANE: 3309.82,6321.92 3417.31,6433.06
  rectangle net VDD_PLANE: 3479.57,6284.54 3587,6395.68
  rectangle net VDD_PLANE: 3093.99,6175 3234.63,6260.55
  rectangle net VDD_PLANE: 3546.24,4418.92 3681.22,4518.4
  region net VDD_PLANE: 4415.86,5123.23 4415.86,5280.12 4308.28,5280.12 4308.28,5123.23
  rectangle net VDD_PLANE: 3627.9,6555.98 3758.8,6667.12
  region net VDDO_PLANE: 2524.4,5608.78 2524.4,5501.35 2635.54,5501.35 2635.54,5608.78
  region net VDDO_PLANE: 2790.48,4686.93 2859.74,4756.2 2758.64,4857.3 2689.38,4788.04
  rectangle net VDDO_PLANE: 3234.71,4312.18 3369.69,4411.66
  pour cut-out: 153 vertices and 0 holes, not listed, extent -200,-200 7200,9361
  pour cut-out: 4016.89,5353.45 4016.89,5309.45 3980.89,5309.45 3980.89,5353.45
  pour cut-out: 3920.84,5508.22 3920.84,5464.22 3884.84,5464.22 3884.84,5508.22
  pour cut-out: 3400.59,5945.67 3444.59,5945.67 3444.59,5909.67 3400.59,5909.67
  pour cut-out: 2871.91,5666.42 2903.02,5697.53 2928.48,5672.07 2897.37,5640.96
  pour cut-out: 2988.06,5721.27 3019.17,5752.38 3044.63,5726.92 3013.52,5695.81
  pour cut-out: 3284.61,5833.65 3328.61,5833.65 3328.61,5797.65 3284.61,5797.65
  text ".Layer_Name" at 326,-1754.49 h60
L4-Mid-Layer 3 (G2):
  pour cut-out: 153 vertices and 0 holes, not listed, extent -200,-200 7200,9361
  pour cut-out: 3284.61,5833.65 3328.61,5833.65 3328.61,5797.65 3284.61,5797.65
  pour cut-out: 2988.06,5721.27 3019.17,5752.38 3044.63,5726.92 3013.52,5695.81
  pour cut-out: 2871.91,5666.42 2903.02,5697.53 2928.48,5672.07 2897.37,5640.96
  pour cut-out: 3400.59,5945.67 3444.59,5945.67 3444.59,5909.67 3400.59,5909.67
  pour cut-out: 3920.84,5508.22 3920.84,5464.22 3884.84,5464.22 3884.84,5508.22
  pour cut-out: 4016.89,5353.45 4016.89,5309.45 3980.89,5309.45 3980.89,5353.45
  text ".Layer_Name" at 321,-1754.49 h60
L5-Mid-Layer 4 (G3):
  pour cut-out: 3284.61,5833.65 3328.61,5833.65 3328.61,5797.65 3284.61,5797.65
  pour cut-out: 2988.06,5721.27 3019.17,5752.38 3044.63,5726.92 3013.52,5695.81
  pour cut-out: 2871.91,5666.42 2903.02,5697.53 2928.48,5672.07 2897.37,5640.96
  pour cut-out: 3400.59,5945.67 3444.59,5945.67 3444.59,5909.67 3400.59,5909.67
  pour cut-out: 3920.84,5508.22 3920.84,5464.22 3884.84,5464.22 3884.84,5508.22
  pour cut-out: 4016.89,5353.45 4016.89,5309.45 3980.89,5309.45 3980.89,5353.45
  text ".Layer_Name" at 321,-1754.49 h60
L6-Mid-Layer 5 (G4):
  pour cut-out: 4016.89,5353.45 4016.89,5309.45 3980.89,5309.45 3980.89,5353.45
  pour cut-out: 3920.84,5508.22 3920.84,5464.22 3884.84,5464.22 3884.84,5508.22
  pour cut-out: 3400.59,5945.67 3444.59,5945.67 3444.59,5909.67 3400.59,5909.67
  pour cut-out: 2871.91,5666.42 2903.02,5697.53 2928.48,5672.07 2897.37,5640.96
  pour cut-out: 2988.06,5721.27 3019.17,5752.38 3044.63,5726.92 3013.52,5695.81
  pour cut-out: 3284.61,5833.65 3328.61,5833.65 3328.61,5797.65 3284.61,5797.65
L7-Mid-Layer 6 (G5):
  pour cut-out: 3284.61,5833.65 3328.61,5833.65 3328.61,5797.65 3284.61,5797.65
  pour cut-out: 2988.06,5721.27 3019.17,5752.38 3044.63,5726.92 3013.52,5695.81
  pour cut-out: 2871.91,5666.42 2903.02,5697.53 2928.48,5672.07 2897.37,5640.96
  pour cut-out: 3400.59,5945.67 3444.59,5945.67 3444.59,5909.67 3400.59,5909.67
  pour cut-out: 3920.84,5508.22 3920.84,5464.22 3884.84,5464.22 3884.84,5508.22
  pour cut-out: 4016.89,5353.45 4016.89,5309.45 3980.89,5309.45 3980.89,5353.45
L8-Bottom Layer (GBL):
  rectangle net LDO3_IN: 6485.2,1937.4 6526.2,2099.4
  rectangle net VBUS: 255,801 372,849
  rectangle net LDO2: 6240.2,1937.4 6295.2,1985.4
  region net LDO3_IN: 5968.2,2127.4 5968.2,2168.4 5880.2,2168.4 5880.2,2127.4
  region net LDO1: 5966.2,1893.4 5966.2,1941.4 5865.2,1941.4 5865.2,1893.4
  rectangle net LDO3: 4920,2838 4981,2942
  rectangle net LDO3_IN: 5166,2836 5228,2966
  text ".Layer_Name" at 321,-1754.49 h60
L2-GND Plane (GP1) (plane layer: these items are gaps in the copper):
  region: 3044.67,5727.19 3019.22,5752.65 2988.1,5721.54 3013.56,5696.08
  region: 2928.52,5672.34 2903.06,5697.8 2871.95,5666.68 2897.41,5641.23
  region: 4016.73,5353.67 3980.73,5353.67 3980.73,5309.67 4016.73,5309.67
  region: 3444.81,5909.83 3444.81,5945.83 3400.81,5945.83 3400.81,5909.83
  region: 3328.61,5797.65 3328.61,5833.65 3284.61,5833.65 3284.61,5797.65
  rectangle: 3885,5464 3921,5508
  pour cut-out: 3779.16,5891.79 3809.16,5921.79 3873.57,5857.38 3843.57,5827.38
  pour cut-out: 3631.8,5979.2 3661.8,6009.2 3726.2,5944.8 3696.2,5914.8
  pour cut-out: 3666.71,5927.74 3686.21,5908.24 3633.82,5855.85 3614.32,5875.35
  pour cut-out: 3624.01,5969.16 3643.51,5949.66 3591.12,5897.28 3571.62,5916.78
  pour cut-out: 3759.21,6105.24 3778.71,6085.74 3726.32,6033.35 3706.82,6052.85
  pour cut-out: 3803.21,6063.24 3822.71,6043.74 3770.32,5991.35 3750.82,6010.85
  pour cut-out: 3907.34,6014.08 3926.84,5994.58 3874.45,5942.19 3854.95,5961.69
  pour cut-out: 3950.79,5973.61 3970.29,5954.11 3917.9,5901.72 3898.4,5921.22
  pour cut-out: 3794.4,5813.9 3813.9,5794.4 3761.51,5742.01 3742.01,5761.51
  pour cut-out: 3749.04,5859.04 3768.54,5839.54 3716.15,5787.15 3696.65,5806.65
  pour cut-out: 391,8131.5 391,8095.5 312,8095.5 312,8131.5
  pour cut-out: 390,7632 390,7595 313,7595 313,7632
  pour cut-out: 390,7130.5 390,7095.5 312,7095.5 312,7130.5
  pour cut-out: 389,6632 389,6593 313,6593 313,6632
  pour cut-out: 389,6133 389,6093 313,6093 313,6133
  pour cut-out: 389,5632 389,5593 313,5593 313,5632
  pour cut-out: 389,5132 389,5093 313,5093 313,5132
  pour cut-out: 389,4632 389,4593 313,4593 313,4632
  pour cut-out: 389,4132 389,4093 313,4093 313,4132
  pour cut-out: 390.5,3632 390.5,3592 311.5,3592 311.5,3632
  pour cut-out: 389,3132 389,3093 313,3093 313,3132
  pour cut-out: 389,2632 389,2593 313,2593 313,2632
  pour cut-out: 6606,2593 6606,2632 6685,2632 6685,2593
  pour cut-out: 6607,3092 6607,3132 6685,3132 6685,3092
  pour cut-out: 6608,3593 6608,3633 6686,3633 6686,3593
  pour cut-out: 6608,4093 6608,4133 6686,4133 6686,4093
  pour cut-out: 6608.04,4592 6608.04,4633.5 6686,4633.5 6686,4592
  pour cut-out: 6608,5093 6608,5133 6685,5133 6685,5093
  pour cut-out: 6609,5591 6609,5633 6685,5633 6685,5591
  pour cut-out: 6608,6092 6608,6133 6685,6133 6685,6092
  pour cut-out: 6608,6592 6608,6632 6686,6632 6686,6592
  pour cut-out: 6606,7092 6606,7132 6686,7132 6686,7092
  pour cut-out: 6608,7593 6608,7632 6685,7632 6685,7593
  pour cut-out: 6609,8092 6609,8133 6685,8133 6685,8092
  pour cut-out: 4267,8772 4228,8772 4228,8848 4267,8848
  pour cut-out: 3768,8771 3727,8771 3727,8849 3768,8849
  pour cut-out: 3268,8771 3228,8771 3228,8848 3268,8848
  pour cut-out: 2768,8771 2728,8771 2728,8849 2768,8849
  pour cut-out: 2267,8771 2228,8771 2228,8848 2267,8848
  pour cut-out: 1768,8771 1727,8771 1727,8849 1768,8849
  pour cut-out: 1267,8771 1228,8771 1228,8848 1267,8848
  pour cut-out: 766,8770 729.5,8770 729.5,8848 766,8848
  pour cut-out: 153 vertices and 0 holes, not listed, extent -200,-200 7200,9361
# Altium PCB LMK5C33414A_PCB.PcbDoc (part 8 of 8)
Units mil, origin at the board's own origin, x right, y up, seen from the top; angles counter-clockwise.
Board outline 7000 x 9161 mil, 8 copper layers (L1-Top Layer (GTL), L2-GND Plane (GP1), L3-Mid-Layer 2 (G1), L4-Mid-Layer 3 (G2), L5-Mid-Layer 4 (G3), L6-Mid-Layer 5 (G4), L7-Mid-Layer 6 (G5), L8-Bottom Layer (GBL)), stack 61.2 mil thick; 521 components, 286 nets, 1393 pads, 2202 vias.

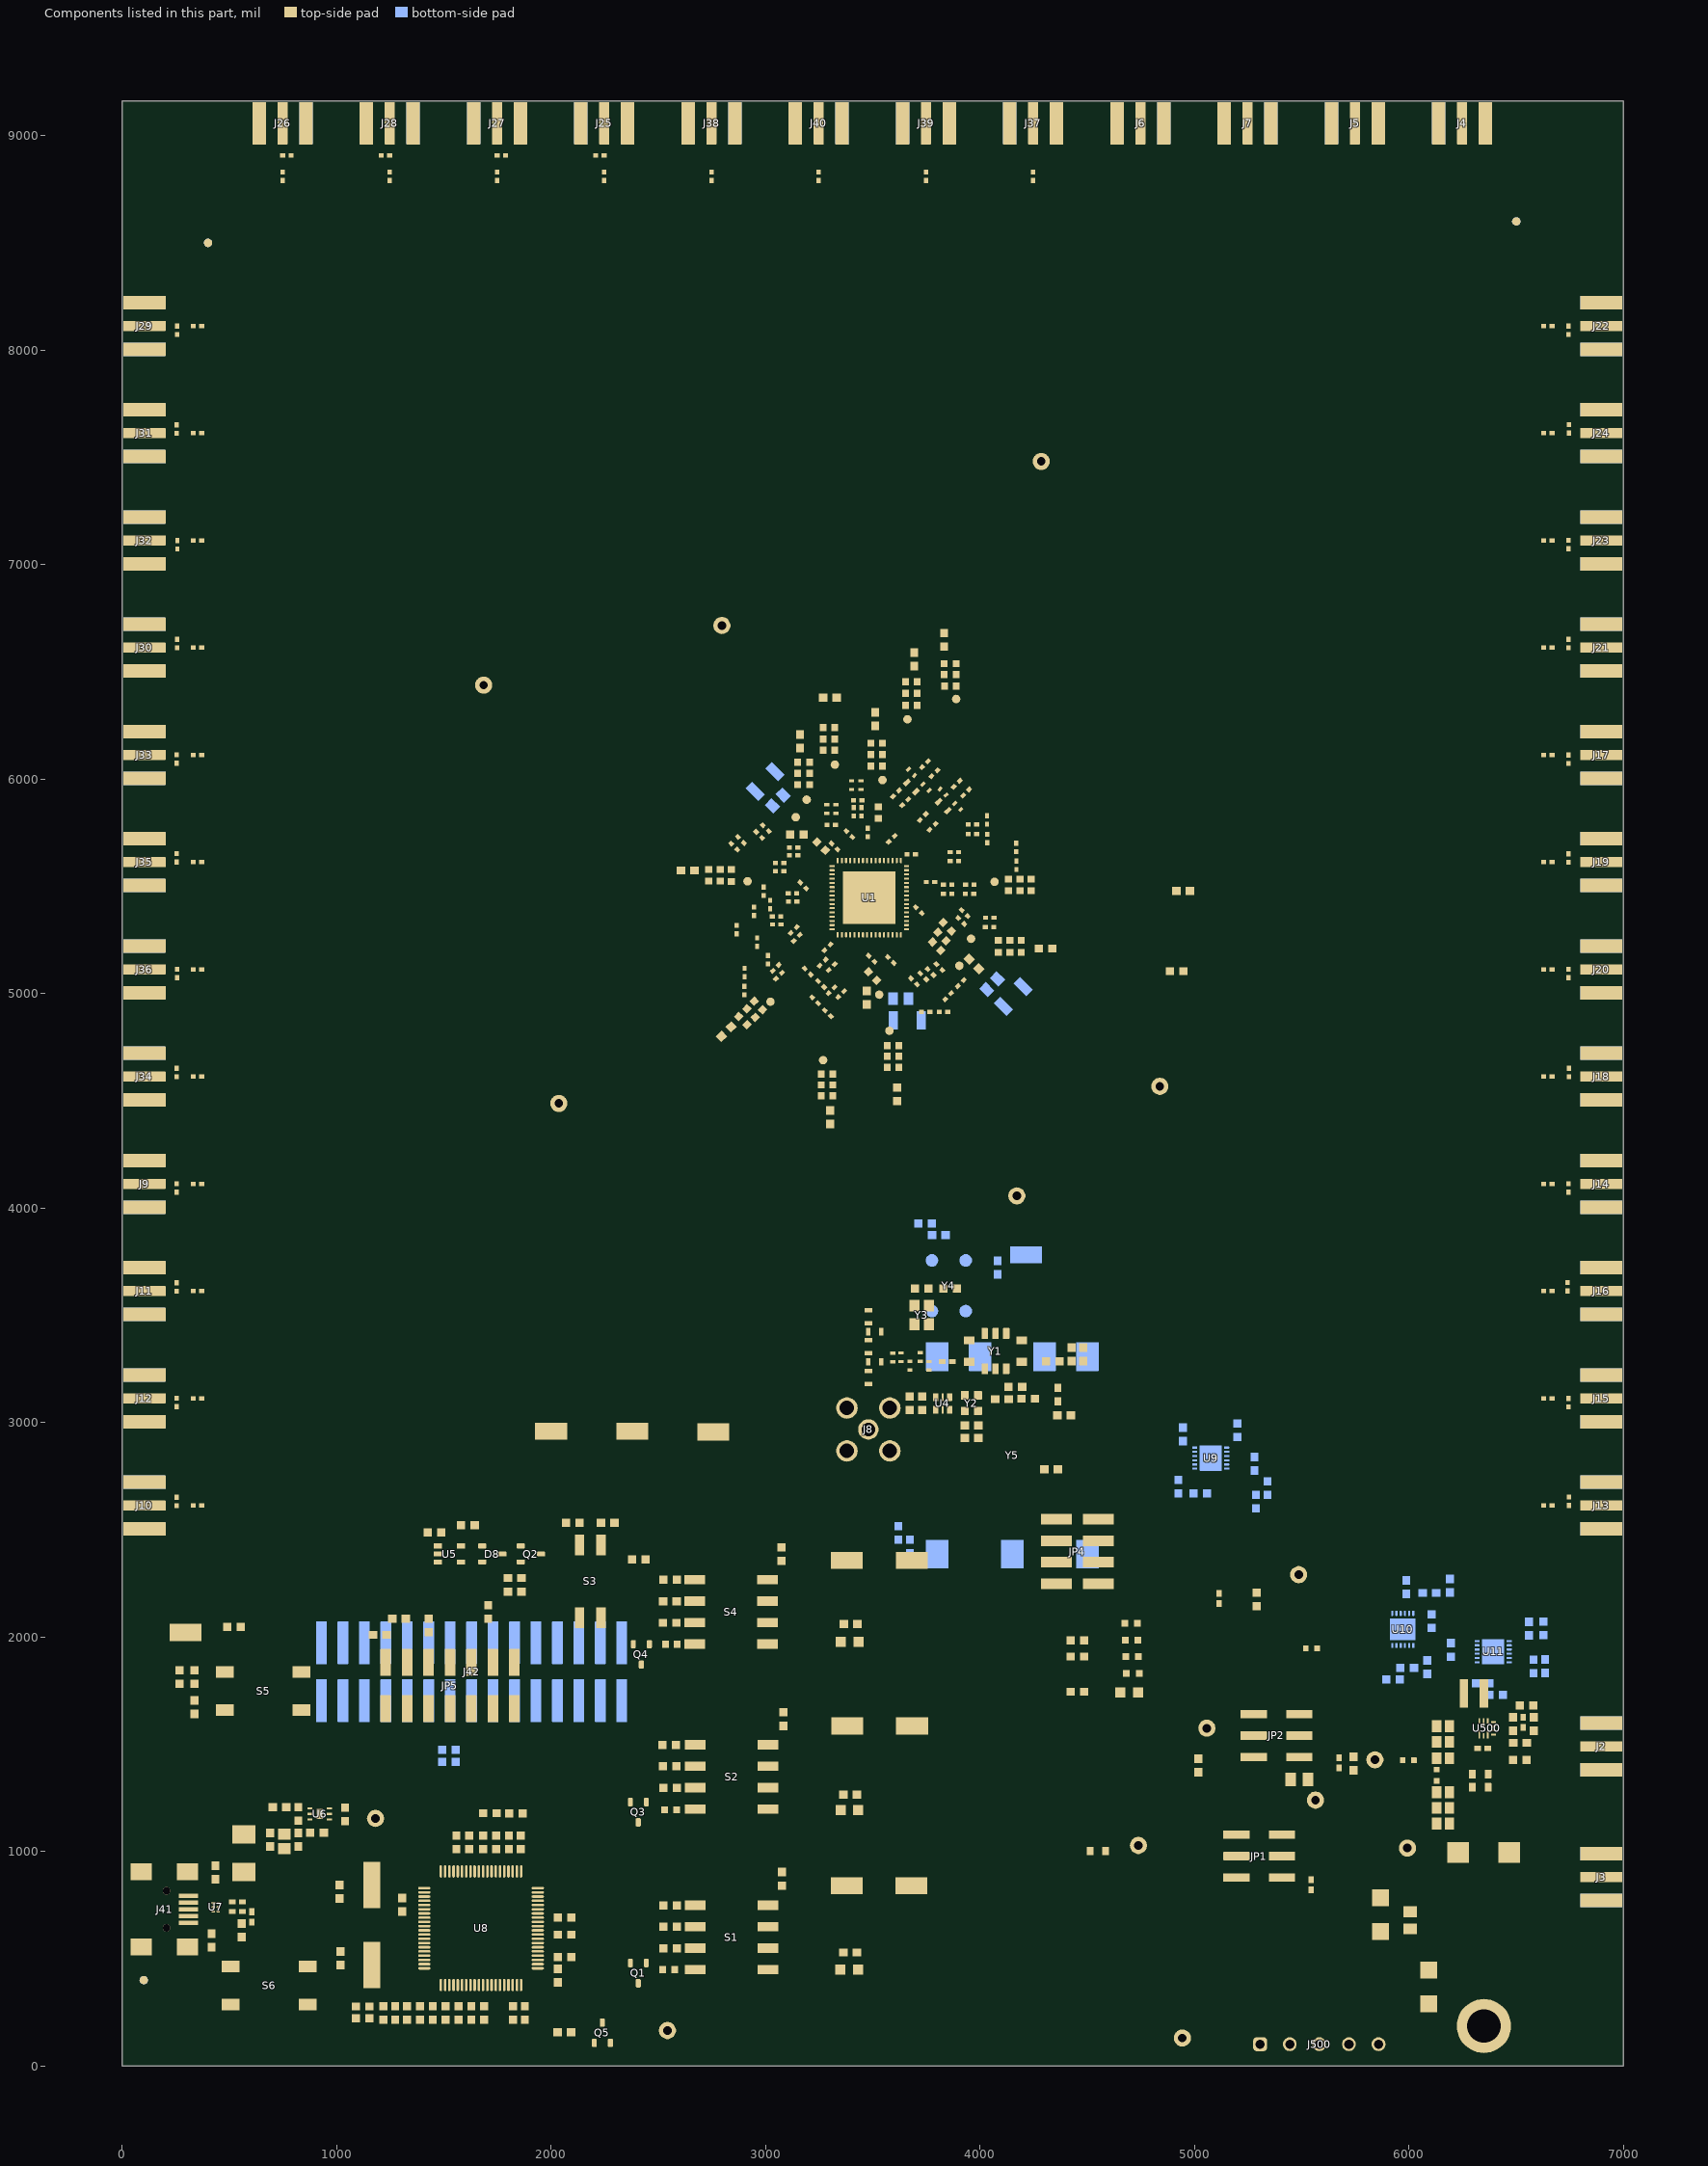
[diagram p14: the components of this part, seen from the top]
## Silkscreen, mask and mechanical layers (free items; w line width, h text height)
Top Overlay:
  region: 3844.77,1188.55 3844.77,1428.55 4766.21,1428.55 4766.21,1188.55
  lines w10: 1189.2,1386.47 1201.2,1374.47 1353.2,1374.47 1365.2,1386.47 ; 1484.2,1390.47 1496.2,1378.47 1859.2,1378.47 1871.2,1390.47 ; 1961.4,1693.4 1976.4,1678.4 ; 1961.4,1853.4 1976.4,1868.4 ; 1976.4,1758.4 1976.4,1678.4 ; 1976.4,1788.4 1976.4,1868.4 ; 1991.4,1693.4 1976.4,1678.4 ; 1991.4,1853.4 1976.4,1868.4 ; 5447.3,2767.7 5447.3,2374.7 6030.9,2374.7 6030.9,1930.9
  text "Default DC  / coupled" at 243.7,3793.4 h72.83
  text "XO_P" at 3074.8,2938.87 h100
  text "LDO3 INPUT" at 5144.6,2538.5 h55
  text "GND" at 4649.2,2495.8 h55
  text "I2C Address" at 2059,2479 h65
  text "VIN3 DIRECT" at 4649.2,2393.47 h55
  text "Power DUT directly: / VIN1 (VDD) = 3.3 V (1 A) / VIN2 (VDDO) = 3.3 V (1 A) / VIN3 (XO_VDD) = 3.3 V (1A) / VIN4 not used." at 5461.6,2391.1 h80
  text "XO VDD" at 4018,2388.3 h55
  text "GPIO2" at 2733.12,2365.21 h70
  text "LDO to XO" at 4650.3,2280.2 h55
  text "VDD" at 3105.27,2248.13 h65
  text "DC/DC to XO" at 4649.2,2188.8 h55
  text "USB2ANY" at 3105.27,2150.6 h65
  text "GND" at 3105.27,2052.15 h65
  text "LED" at 3105.27,1953.13 h65
  text "Power DUT with DCDC: / VIN4 = 10 V to 15 V (1 A) / VIN1, VIN2, VIN3 not used. /  / Power DUT with LDO: / VIN1 = 3.6 V to 5 V (2 A) / VIN2, VIN3, VIN4 not used." at 6071.4,1913.6 h80
  text "DUT" at 2034.46,1786.11 h50 r90
  text "MCU" at 2034.24,1671.11 h50 r90
  text "VIN2 DIRECT" at 5490.8,1668.3 h55
  text "GPIO1" at 2748.52,1594.74 h70
  text "LDO    to VDDO" at 5490.8,1569.9 h55
  text "DC/DC to VDDO" at 5490.8,1483.89 h55
  text "USER NOTE:" at 3838,1473 h100
  text "VDD" at 3105.27,1469.13 h65
  text "SDA" at 1245.4,1388.37 h65 r90
  text "SCL" at 1346.23,1388.37 h65 r90
  text "GND" at 1447.07,1388.37 h65 r90
  text "SCK" at 1547.9,1388.37 h65 r90
  text "MOSI" at 1648.73,1388.37 h65 r90
  text "MISO" at 1749.57,1388.37 h65 r90
  text "SCS" at 1850.4,1388.37 h65 r90
  text "USB2ANY" at 3105.27,1376.6 h65
  text "I2C" at 1235.7,1296.18 h100
  text "SPI" at 1640.7,1296.27 h100
  text "GND" at 3105.27,1278.15 h65
  text "LED" at 3105.27,1179.13 h65
  text "VIN1 DIRECT" at 5403.8,1106.2 h55
  text "LDO to VDD" at 5402.6,1005.4 h55
  text "DC/DC to VDD" at 5401.5,909.1 h55
  text "GPIO0" at 2760.92,845.74 h70
  text "VDD" at 3105.27,724.13 h65
  text "USB2ANY" at 3105.27,626.6 h65
  text "GND" at 3105.27,528.15 h65
  text "LED" at 3105.27,429.13 h65
  text "VIN4" at 5744.7,302 h75 r90
  text "VIN3" at 5610.5,300.3 h75 r90
  text "VIN1" at 5340.5,298.6 h75 r90
  text "VIN2" at 5478.1,298.6 h75 r90
  text "GND" at 5889.1,296.9 h75 r90
  text "PWR" at 4939.39,214.18 h100
  text ".Layer_Name" at 324,-1754 h100
Bottom Overlay:
  text ".Layer_Name" at 577,-1758.49 h50
Top Paste:
  text ".Layer_Name" at 577,-1758.49 h60
Bottom Paste:
  text ".Layer_Name" at 321,-1754.49 h60
Top Solder:
  circle w30: c3194,4708 r1
  circle w30: c3495,4839 r1
  circle w30: c4052,5003 r1
  circle w30: c4078,5447 r1
  circle w30: c3614,6032 r1
  circle w30: c3395,6066 r1
  circle w30: c3111,5924 r1
  circle w30: c3050,5854 r1
  circle w30: c2771,5690 r1
  circle w30: c2827,4962 r1
  circle w30: c3738,6246 r1
  circle w30: c3966,6408 r1
  circle w30: c4103,5394 r1
  circle w30: c4080,5121 r1
  text ".Layer_Name" at 577,-1758.49 h60
Bottom Solder:
  region: 3335,5300 3631,5300 3631,5593 3335,5593
  text ".Layer_Name" at 321,-1754.49 h60
Drill Guide:
  text ".Layer_Name" at 321,-1754.49 h60
  text ".Layer_Name" at 577,-1758.49 h60
M1 Board Outline:
  the board outline again, w5
  text ".Layer_Name" at 577,-1758.49 h60
M3 3D STEP Top:
  text ".Layer_Name" at 321,-1754.49 h60
  text ".Layer_Name" at 577,-1758.49 h60
M4 3D STEP Bottom:
  text ".Layer_Name" at 321,-1754.49 h60
  text ".Layer_Name" at 577,-1758.49 h60
M5 Assembly Top:
  lines w10: -292,-1830.17 6308,-1830.17 ; -292,-1626.83 6310,-1626.83 ; -292,-1423.5 -292,-2033.5 3713,-2033.5 6310,-2033.5 6310,-1423.5 -291.5,-1423.5 -291.5,-2033.5 1284,-2033.5 ; 2173,-2033.5 2173,-1423.5 ; 3440,-1626.83 3440,-1423.5 ; 4280,-1626.83 4280,-1423.5 ; 4902,-2040 4902,-1837.17
  text "COMPONENTS MARKED 'DNP' SHOULD NOT BE POPULATED." at 1403.5,-1188.5 h60
  text "ASSEMBLY VARIANT:" at 1403,-1304 h60
  text ".VariantName" at 2439,-1304 h60
  text "PCB VIEWED FROM TOP SIDE" at -228.5,-1555.67 h60
  text "BOARD #:" at 2248,-1555.67 h60
  text ".PRJ_Number" at 2793.5,-1555.67 h60
  text "REV:" at 3638,-1555.67 h60
  text ".PCB_Rev" at 3929.5,-1555.67 h60
  text "SVN REV:" at 4476,-1555.67 h60
  text ".VersionControl_RevNumber" at 4982,-1555.67 h60
  text "TID #:" at 2248,-1759 h60
  text ".TID" at 2793.5,-1759 h60
  text "PLOT NAME =" at -228.5,-1964.34 h60
  text ".plot_File_Name" at 577,-1964.34 h60
  text "GENERATED    :" at 2250,-1964.34 h60
  text ".Print_Date" at 3119.5,-1964.34 h60
  text ".Print_Time" at 3848.5,-1964.34 h60
  text "TEXAS INSTRUMENTS" at 5113,-1964.34 h60
M6 Assembly Bottom:
  lines w10: -292.5,-1627.33 6309.5,-1627.33 ; -290.5,-1830.67 6309.5,-1830.67 ; 1115.5,-2040.5 1115.5,-1837.67 ; 1737.5,-1627.33 1737.5,-1424 ; 2577.5,-1627.33 2577.5,-1424 ; 3844.5,-2034 3844.5,-1424 ; 4733.5,-2034 6309,-2034 6309,-1424 -292.5,-1424 -292.5,-2034 2304.5,-2034 6309.5,-2034 6309.5,-1424
  text "COMPONENTS MARKED 'DNP' SHOULD NOT BE POPULATED." at 6352,-1188 h60
  text ".VariantName" at 5308,-1304 h60
  text "ASSEMBLY VARIANT:" at 6347,-1304 h60
  text ".VersionControl_RevNumber" at 1035.5,-1556.17 h60
  text "SVN REV:" at 1541.5,-1556.17 h60
  text ".PCB_Rev" at 2088,-1556.17 h60
  text "REV:" at 2379.5,-1556.17 h60
  text ".PRJ_Number" at 3224,-1556.17 h60
  text "BOARD #:" at 3769.5,-1556.17 h60
  text "PCB VIEWED FROM BOTTOM SIDE" at 6246,-1556.17 h60
  text "IGNORE ->" at 2289.85,-1754.49 h60
  text ".TID" at 3224,-1759.5 h60
  text "TID #:" at 3769.5,-1759.5 h60
  text "TEXAS INSTRUMENTS" at 904.5,-1964.84 h60
  text ".Print_Time" at 2169,-1964.84 h60
  text ".Print_Date" at 2898,-1964.84 h60
  text "GENERATED    :" at 3767.5,-1964.84 h60
  text ".plot_File_Name" at 5440.5,-1964.84 h60
  text "PLOT NAME =" at 6246,-1964.84 h60
M7 LPKF Text Top:
  text ".Layer_Name" at 321,-1754.49 h60
M9 Title Sheet:
  drawing of 54 lines, arcs and shapes, not listed
  text "1" at 886.34,12299.39 h70
  text "2" at 4212,12299.39 h70
  text "3" at 7542,12299.39 h70
  text "4" at 10877,12299.39 h70
  text "A" at -635,10521.39 h70
  text "B" at -635,6771.39 h70
  text "B" at 19065,6771.39 h70
  text "C" at -635,3021.39 h70
  text "C" at 19065,3021.39 h70
  text "D" at -635,-728.61 h70
  text "D" at 19065,-728.61 h70
  text "PROJECT TITLE:" at 15971,-813.61 h45
  text ".PRJ_Title" at 16021,-946.94 h70
  text "DESIGNED FOR:" at 15971,-1114.61 h45
  text ".PRJ_Customer" at 16021,-1254.61 h70
  text "FILE NAME:" at 15971,-1414.61 h45
  text ".PCB_File_Name_No_Path" at 16021,-1534.61 h70
  text "Texas Instruments (TI) and/or its licensors do not warrant the accuracy or completeness of this specification" at 11001.5,-1696.45 h45
  text "ENGINEER:" at 15971,-1704.61 h45
  text "LAYOUT BY:" at 17476,-1704.61 h45
  text ".Layer_Name" at 415,-1755 h60
  text "or any information contained therein. TI and/or its licensors do not warrant that this design will meet" at 10956.51,-1809.11 h45
  text ".PRJ_Engineer" at 16021,-1859.6 h70
  text ".PCB_Layout" at 17526.5,-1859.6 h70
  text "the specifications, will be suitable for your application or fit for any particular purpose, or will operate in" at 10956.51,-1921.78 h45
  text "ALTIUM DESIGNER VERSION:" at 17476,-2014.61 h45
  text "an implementation. TI and/or its licensors do not warrant that the design is production worthy. You should" at 10956.51,-2034.44 h45
  text "completely validate and test your design implementation to confirm the system functionality for your application." at 11001.5,-2147.11 h45
  text ".print_Scale" at 16021,-2147.94 h70
  text ".Application_BuildNumber" at 17526.5,-2147.94 h70
  text "1" at 886.34,-2400.61 h70
  text "2" at 4212,-2400.61 h70
  text "3" at 7542,-2400.61 h70
  text "4" at 10877,-2400.61 h70
  text "5" at 14202,-2400.61 h70
  text "6" at 17537,-2400.61 h70
M10 Fab Notes:
  drawing of 203 lines, arcs and shapes, not listed
  text "C" at 16536.76,6898.2 h137.54
  text "o" at 16602.93,6898.2 h137.54
  text "n" at 16669.1,6898.2 h137.54
  text "t" at 16735.27,6898.2 h137.54
  text "r" at 16782.53,6898.2 h137.54
  text "o" at 16829.8,6898.2 h137.54
  text "l" at 16895.97,6898.2 h137.54
  text "l" at 16924.33,6898.2 h137.54
  text "e" at 16952.69,6898.2 h137.54
  text "d" at 17018.86,6898.2 h137.54
  text "I" at 17113.39,6898.2 h137.54
  text "m" at 17141.75,6898.2 h137.54
  text "p" at 17245.73,6898.2 h137.54
  text "e" at 17311.9,6898.2 h137.54
  text "d" at 17378.08,6898.2 h137.54
  text "a" at 17444.25,6898.2 h137.54
  text "n" at 17500.96,6898.2 h137.54
  text "c" at 17567.14,6898.2 h137.54
  text "e" at 17614.4,6898.2 h137.54
  text "L" at 15192.16,6690.23 h137.54
  text "a" at 15248.88,6690.23 h137.54
  text "y" at 15305.6,6690.23 h137.54
  text "e" at 15362.31,6690.23 h137.54
  text "r" at 15428.48,6690.23 h137.54
  text "S" at 15741.36,6690.23 h137.54
  text "i" at 15798.08,6690.23 h137.54
  text "n" at 15826.44,6690.23 h137.54
  text "g" at 15892.61,6690.23 h137.54
  text "l" at 15949.33,6690.23 h137.54
  text "e" at 15977.69,6690.23 h137.54
  text "-" at 16043.86,6690.23 h137.54
  text "E" at 16081.67,6690.23 h137.54
  text "n" at 16138.39,6690.23 h137.54
  text "d" at 16204.56,6690.23 h137.54
  text "e" at 16270.73,6690.23 h137.54
  text "d" at 16336.9,6690.23 h137.54
  text "Ω" at 16726.14,6690.23 h137.54
  text "+" at 17085.96,6690.23 h137.54
  text "/" at 17142.68,6690.23 h137.54
  text "-" at 17199.39,6690.23 h137.54
  text "%" at 17265.57,6690.23 h137.54
  text "R" at 17587.81,6690.23 h137.54
  text "e" at 17653.99,6690.23 h137.54
  text "f" at 17720.16,6690.23 h137.54
  text "e" at 17757.97,6690.23 h137.54
  text "r" at 17824.14,6690.23 h137.54
  text "e" at 17871.41,6690.23 h137.54
  text "n" at 17937.58,6690.23 h137.54
  text "c" at 18003.75,6690.23 h137.54
  text "e" at 18051.01,6690.23 h137.54
  text "L" at 18145.54,6690.23 h137.54
  text "a" at 18202.26,6690.23 h137.54
  text "y" at 18258.98,6690.23 h137.54
  text "e" at 18315.7,6690.23 h137.54
  text "r" at 18381.87,6690.23 h137.54
  text "s" at 18429.13,6690.23 h137.54
  text "L1" at 15303.79,6496.3 h137.54
  text "1" at 15881.4,6496.3 h137.54
  text "1" at 15947.57,6496.3 h137.54
  text "m" at 16013.74,6496.3 h137.54
  text "i" at 16108.27,6496.3 h137.54
  text "l" at 16146.08,6496.3 h137.54
  text "s" at 16183.89,6496.3 h137.54
  text "5" at 16705.2,6496.3 h137.54
  text "0" at 16771.37,6496.3 h137.54
  text "1" at 17150.24,6496.3 h137.54
  text "0" at 17216.41,6496.3 h137.54
  text "L2 (GP1)" at 17992.98,6496.3 h137.54
  text "100" at 16708.41,6293 h137.54
  text "1" at 17149.45,6293 h137.54
  text "0" at 17215.63,6293 h137.54
  text "L1" at 15297.79,6291.3 h137.54
  text "L2 (GP1)" at 17979.19,6280 h137.54
  text "Diff 100 ohms / 8 mil wide, 8 mil space" at 15730,6245 h100
  text "5" at 16698.41,6093 h137.54
  text "0" at 16764.58,6093 h137.54
  text "1" at 17149.45,6093 h137.54
  text "0" at 17215.63,6093 h137.54
  text "5" at 15900.78,6092 h137.54
  text "m" at 15966.95,6092 h137.54
  text "i" at 16061.48,6092 h137.54
  text "l" at 16099.29,6092 h137.54
  text "s" at 16137.11,6092 h137.54
  text "L5 and L7" at 17969.19,6080 h137.54
  text "L6" at 15285,6078 h137.54
  text "5" at 16694.22,5861 h137.54
  text "0" at 16760.39,5861 h137.54
  text "1" at 17145.26,5861 h137.54
  text "0" at 17211.43,5861 h137.54
  text "11" at 15896.59,5860 h137.54
  text "m" at 16022.76,5860 h137.54
  text "i" at 16117.29,5860 h137.54
  text "l" at 16155.1,5860 h137.54
  text "s" at 16192.91,5860 h137.54
  text "L7" at 17965,5848 h137.54
  text "L8" at 15280.81,5846 h137.54
  text "DESIGN INFORMATION" at 16758.02,5364 h60
  text "MIN. TRACK WIDTH:" at 16113.46,5184 h60
  text "5" at 17209.7,5184 h60
  text "MIL" at 17364.46,5184 h60
  text "MIN. CLEARANCE:" at 16113.46,5052 h60
  text "5" at 17149.7,5052 h60
  text "MIL" at 17364.46,5052 h60
  text "MIN. VIA PAD SIZE:" at 16113.46,4920 h60
  text "19.7" at 17130,4920 h60
  text "MIL" at 17364.46,4920 h60
  text "0.05mm (2MIL)" at 16808.46,4778.29 h60
  text "MINIMUM ANNULAR RING" at 15784.23,4774 h60
  text "EXTERNAL" at 17516.46,4774 h60
  text "PER" at 15984.23,4656 h60
  text "IPC-D-275 CLASS 2 LEVEL C" at 16204.23,4656 h60
  text "MIL, HOLES" at 17692.46,4543.71 h60
  text "+/-" at 17300,4543 h60
  text "+/-" at 18154,4543 h60
  text "REGISTRATION TOLERANCES:" at 15784.23,4538 h60
  text "METAL" at 16984,4538 h60
  text "5" at 17560.2,4538 h60
  text "3" at 18393.2,4538 h60
  text "MIL" at 18509.46,4538 h60
  text "+/-" at 18154,4425 h60
  text "HOLE SIZE TOLERANCE (UNLESS OTHERWISE SPECIFIED):" at 15784.23,4420 h60
  text "3" at 18393.2,4420 h60
  text "MIL" at 18509.46,4420 h60
  text "MATERIAL:" at 15709.46,4210.54 h60
  text "FR-4 High Tg" at 16695.9,4070.21 h60
  text "FR-408" at 16130.46,4061.64 h60
  text "OTHER" at 17618.46,4061.64 h60
  text "X" at 16541,4058 h60
  text "62 MIL (1.6mm) +/-10%" at 16450.56,3898.92 h60
  text "THICKNESS:" at 15784.23,3894.64 h60
  text "X" at 16322.4,3894.64 h60
  text "OTHER" at 17735.46,3894.64 h60
  text "TOLERANCE:" at 15784.23,3736.64 h60
  text "X" at 16623.53,3736.64 h60
  text "ANSI IPC-6012 TYPE 3 CLASS 2" at 16810.48,3736.64 h60
  text "OTHER +/-" at 16810.46,3580.64 h60
  text "BOW & TWIST:" at 15784.23,3423.64 h60
  text "X" at 16623.53,3423.64 h60
  text "ANSI IPC-6012 TYPE 3 CLASS 2" at 16810.48,3423.64 h60
  text "OTHER +/-" at 16810.46,3265.13 h60
  text "DRILLING:" at 15709.46,3126.64 h60
  text "REFERENCE:" at 15784.23,3009.64 h60
  text "X" at 16432.46,3009.64 h60
  text "AS SHOWN" at 16619.46,3009.64 h60
  text "X" at 17333.46,3009.64 h60
  text "NC_DRILL FILES" at 17470.46,3009.64 h60
  text "PTH COPPER THICKNESS:" at 15784.23,2851.64 h60
  text "X" at 16914.46,2851.64 h60
  text "20-30 um" at 17051.46,2851.64 h60
  text "OTHER" at 17768.46,2851.64 h60
  text "BOARD FINISH:" at 15709.46,2692.64 h60
  text "SILKSCREEN:" at 15864.68,2574.64 h60
  text "X" at 16813.46,2574.64 h60
  text "TOP" at 16939.46,2574.64 h60
  text "X" at 17323.46,2574.64 h60
  text "BOTTOM" at 17450.46,2574.64 h60
  text "SILKSCREEN COLOR:" at 15864.68,2407.64 h60
  text "X" at 16812.42,2407.64 h60
  text "WHITE" at 16939.46,2407.64 h60
  text "OTHER" at 17450.46,2407.64 h60
  text "X" at 16943.42,2248.44 h60
  text "GREEN" at 17070.46,2248.44 h60
  text "OTHER" at 17688.46,2248.44 h60
  text "SOLDER RESIST COLOR:" at 15864.68,2237.64 h60
  text "X" at 16943.42,2078.44 h60
  text "MATTE" at 17070.46,2078.44 h60
  text "SEMI-GLOSS" at 17688,2077.8 h60
  text "IMMERSION GOLD (ENIG)" at 16770.46,1889.92 h60
  text "ENEPIG" at 18108,1886.64 h60
  text "SURFACE FINISH:" at 15709.46,1885.64 h60
  text "X" at 16583.51,1885.64 h60
  text "IMM. TIN/SILVER OR EQUIV" at 16039,1728.64 h60
  text "OTHER" at 17470.46,1728.64 h60
  text "ARRAY/PANEL:" at 15709.46,1549.64 h60
  text "CUT AND TRIM PER M1 BOARD OUTLINE" at 16770.46,1545.35 h60
  text "N.C. ROUTE" at 16770.46,1393.64 h60
  text "V. SCORE" at 17636.46,1393.64 h60
  text "X" at 16585,1383 h60
  text "CERTIFICATION:" at 15709.46,1256.64 h60
  text "MATERIALS AND WORKMANSHIP FOR ALL PCBS" at 16434.46,1256.64 h60
  text "TO MEET OR EXCEED THE REQUIREMENTS OF:" at 16434.46,1158.64 h60
  text "X" at 16060.96,1022.13 h60
  text "ANSI IPC-A-600F CLASS ->" at 16199.96,1022.13 h60
  text "X" at 17839.02,1022.13 h60
  text "2" at 17957.96,1022.14 h60
  text "1" at 17642.96,1020.64 h60
  text "3" at 18311.96,1020.64 h60
  text "X" at 16875.02,862.64 h60
  text "RoHS" at 17011.96,862.64 h60
  text "OTHER" at 17656.36,862.64 h60
  text "PER ORDER" at 18053.42,862.64 h60
  text "ALL BOARDS MUST MEET OR EXCEED UL94-V0 REQUIREMENTS." at 15737,697 h60
  text "PCB MUST BEAR THE UL94V-0 UL REGISTERED MATERIAL ID NUMBER" at 15737,577 h60
  text "ADDITIONAL REQUIREMENTS:" at 15709.46,403.64 h60
  text "MICROSECTION:" at 15784.23,288.64 h60
  text "YES" at 16689.96,288.64 h60
  text "REQUIRED" at 17551.46,132.49 h60
  text "BARE BOARD ELEC. TEST:" at 15784.23,129.64 h60
  text "NONE" at 17089.96,129.64 h60
  text "X" at 17424.46,129.64 h60
  text "PER ORDER" at 18143.46,129.64 h60
  text ".Layer_Name" at 321,-1754.49 h60
M11 Gerber Information:
  lines w10: -292,-1830.17 6308,-1830.17 ; -292,-1626.83 6310,-1626.83 ; -292,-1423.5 -292,-2033.5 3713,-2033.5 6310,-2033.5 6310,-1423.5 -291.5,-1423.5 -291.5,-2033.5 1284,-2033.5 ; 2173,-2033.5 2173,-1423.5 ; 3440,-1626.83 3440,-1423.5 ; 4280,-1626.83 4280,-1423.5 ; 4902,-2040 4902,-1837.17
  text "ALL ARTWORK VIEWED FROM TOP SIDE" at -228.5,-1555.67 h60
  text "BOARD #:" at 2248,-1555.67 h60
  text ".PRJ_Number" at 2793.5,-1555.67 h60
  text "REV:" at 3638,-1555.67 h60
  text ".PCB_Rev" at 3929.5,-1555.67 h60
  text "SVN REV:" at 4476,-1555.67 h60
  text ".VersionControl_RevNumber" at 4982,-1555.67 h60
  text "LAYER NAME =" at -228.5,-1758.49 h60
  text "TID #:" at 2248,-1759 h60
  text ".TID" at 2793.5,-1759 h60
  text "PLOT NAME =" at -228.5,-1964.34 h60
  text ".plot_File_Name" at 577,-1964.34 h60
  text "GENERATED    :" at 2250,-1964.34 h60
  text ".Print_Date" at 3119.5,-1964.34 h60
  text ".Print_Time" at 3848.5,-1964.34 h60
  text "TEXAS INSTRUMENTS" at 5113,-1964.34 h60
M12 Stackup:
  drawing of 1140 lines, arcs and shapes, not listed
  text "Layer" at 8549.4,8843.26 h60
  text "Name" at 8959.31,8843.26 h60
  text "Material" at 10288.93,8843.26 h60
  text "Thickness" at 11148.69,8843.26 h60
  text "Constant" at 11798.53,8843.26 h60
  text "Board Layer Stack" at 12368.39,8843.26 h60
  text "Board Layer Stack" at 13488.07,8843.26 h60
  text "Top Overlay" at 8959.31,8723.26 h60
  text "Top Solder" at 8959.31,8603.26 h60
  text "Solder Resist" at 10288.93,8603.26 h60
  text "0.40mil" at 11148.69,8603.26 h60
  text "3.5" at 11798.53,8603.26 h60
  text "1" at 8549.4,8483.26 h60
  text "L1-Top Layer (GTL)" at 8959.31,8483.26 h60
  text "1.40mil" at 11148.69,8483.26 h60
  text "Dielectric1" at 8959.31,8363.26 h60
  text "FR-4" at 10288.93,8363.26 h60
  text "7.00mil" at 11148.69,8363.26 h60
  text "4.6" at 11798.53,8363.26 h60
  text "2" at 8549.4,8243.26 h60
  text "L2-GND Plane (GP1)" at 8959.31,8243.26 h60
  text "1.40mil" at 11148.69,8243.26 h60
  text "Dielectric2" at 8959.31,8123.26 h60
  text "FR-4" at 10288.93,8123.26 h60
  text "7.00mil" at 11148.69,8123.26 h60
  text "4.6" at 11798.53,8123.26 h60
  text "3" at 8549.4,8003.26 h60
  text "L3-Mid-Layer 2 (G1)" at 8959.31,8003.26 h60
  text "1.40mil" at 11148.69,8003.26 h60
  text "Dielectric3" at 8959.31,7883.26 h60
  text "FR-4" at 10288.93,7883.26 h60
  text "5.00mil" at 11148.69,7883.26 h60
  text "4.6" at 11798.53,7883.26 h60
  text "4" at 8549.4,7763.26 h60
  text "L4-Mid-Layer 3 (G2)" at 8959.31,7763.26 h60
  text "1.40mil" at 11148.69,7763.26 h60
  text "Dielectric4" at 8959.31,7643.26 h60
  text "FR-4" at 10288.93,7643.26 h60
  text "12.00mil" at 11148.69,7643.26 h60
  text "4.6" at 11798.53,7643.26 h60
  text "5" at 8549.4,7523.26 h60
  text "L5-Mid-Layer 4 (G3)" at 8959.31,7523.26 h60
  text "1.40mil" at 11148.69,7523.26 h60
  text "Dielectric5" at 8959.31,7403.26 h60
  text "FR-4" at 10288.93,7403.26 h60
  text "5.00mil" at 11148.69,7403.26 h60
  text "4.6" at 11798.53,7403.26 h60
  text "6" at 8549.4,7283.26 h60
  text "L6-Mid-Layer 5 (G4)" at 8959.31,7283.26 h60
  text "1.40mil" at 11148.69,7283.26 h60
  text "Dielectric6" at 8959.31,7163.26 h60
  text "FR-4" at 10288.93,7163.26 h60
  text "7.00mil" at 11148.69,7163.26 h60
  text "4.6" at 11798.53,7163.26 h60
  text "7" at 8549.4,7043.26 h60
  text "L7-Mid-Layer 6 (G5)" at 8959.31,7043.26 h60
  text "1.40mil" at 11148.69,7043.26 h60
  text "Dielectric7" at 8959.31,6923.26 h60
  text "FR-4" at 10288.93,6923.26 h60
  text "7.00mil" at 11148.69,6923.26 h60
  text "4.6" at 11798.53,6923.26 h60
  text "8" at 8549.4,6803.26 h60
  text "L8-Bottom Layer (GBL)" at 8959.31,6803.26 h60
  text "1.40mil" at 11148.69,6803.26 h60
  text "Bottom Solder" at 8959.31,6683.26 h60
  text "Solder Resist" at 10288.93,6683.26 h60
  text "0.40mil" at 11148.69,6683.26 h60
  text "3.5" at 11798.53,6683.26 h60
  text "Bottom Overlay" at 8959.31,6563.26 h60
  text ".Layer_Name" at 321,-1754.49 h60
M13 Component Bodies Top:
  text ".Layer_Name" at 321,-1754.49 h60
  text ".Layer_Name" at 577,-1758.49 h60
M14 Component Bodies Bottom:
  text ".Layer_Name" at 321,-1754.49 h60
  text ".Layer_Name" at 577,-1758.49 h60
M15 Courtyards Top:
  text ".Layer_Name" at 321,-1754.49 h60
  text ".Layer_Name" at 577,-1758.49 h60
M16 Courtyards Bottom:
  text ".Layer_Name" at 321,-1754.49 h60
  text ".Layer_Name" at 577,-1758.49 h60
Drill Drawing:
  circle w10: c7275.12,10807.23 r33.33
  lines w10: 7241.79,10323.9 7241.79,10340.57 7258.46,10357.23 7241.79,10373.9 7241.79,10390.57 7258.46,10390.57 7275.12,10373.9 7291.79,10390.57 7308.46,10390.57 7308.46,10373.9 7291.79,10357.23 7308.46,10340.57 7308.46,10323.9 7291.79,10323.9 7275.12,10340.57 7258.46,10323.9 7241.79,10323.9 ; 7241.79,10473.9 7275.12,10490.57 7308.46,10473.9 7291.79,10507.23 7308.46,10540.57 7275.12,10523.9 7241.79,10540.57 7258.46,10507.23 7241.79,10473.9 ; 7241.79,10623.9 7308.46,10623.9 7308.46,10690.57 7241.79,10690.57 7241.79,10623.9 ; 7241.79,10940.57 7258.46,10940.57 7258.46,10923.9 7291.79,10923.9 7291.79,10940.57 7308.46,10940.57 7308.46,10973.9 7291.79,10973.9 7291.79,10990.57 7258.46,10990.57 7258.46,10973.9 7241.79,10973.9 7241.79,10940.57 ; 7241.79,11073.9 7308.46,11073.9 7308.46,11140.57 7241.79,11140.57 7241.79,11073.9 ; 7241.79,11257.23 7275.12,11223.9 7308.46,11257.23 7275.12,11290.57 7241.79,11257.23 ; 7241.79,11373.9 7275.12,11390.57 7308.46,11373.9 7291.79,11407.23 7308.46,11440.57 7275.12,11423.9 7241.79,11440.57 7258.46,11407.23 7241.79,11373.9 ; 7241.79,11740.57 7308.46,11740.57 7275.12,11673.9 7241.79,11740.57 ; 7241.79,11823.9 7241.79,11840.57 7258.46,11857.23 7241.79,11873.9 7241.79,11890.57 7258.46,11890.57 7275.12,11873.9 7291.79,11890.57 7308.46,11890.57 7308.46,11873.9 7291.79,11857.23 7308.46,11840.57 7308.46,11823.9 7291.79,11823.9 7275.12,11840.57 7258.46,11823.9 7241.79,11823.9 ; 7255.12,10337.23 7255.12,10347.23 7265.12,10357.23 7255.12,10367.23 7255.12,10377.23 7265.12,10377.23 7275.12,10367.23 7285.12,10377.23 7295.12,10377.23 7295.12,10367.23 7285.12,10357.23 7295.12,10347.23 7295.12,10337.23 7285.12,10337.23 7275.12,10347.23 7265.12,10337.23 7255.12,10337.23 ; 7255.12,10487.23 7275.12,10497.23 7295.12,10487.23 7285.12,10507.23 7295.12,10527.23 7275.12,10517.23 7255.12,10527.23 7265.12,10507.23 7255.12,10487.23 ; 7255.12,11087.23 7295.12,11087.23 7295.12,11127.23 7255.12,11127.23 7255.12,11087.23
  lines w15: 7182,10128.9 18862.71,10128.9 ; 7182,11928.9 18862.71,11928.9 ; 7732.88,9978.9 7732.88,12078.9 ; 8392.7,9978.9 8392.7,12078.9 ; 9542.36,9978.9 9542.36,12078.9 ; 10048.24,9978.9 10048.24,12078.9 ; 10782.04,9978.9 10782.04,12078.9 ; 13311.26,9978.9 13311.26,12078.9 ; 13901.1,9978.9 13901.1,12078.9 ; 14646.9,9978.9 14646.9,12078.9 ; 15296.73,9978.9 15296.73,12078.9 ; 16150.5,9978.9 16150.5,12078.9 ; 17484.1,9978.9 17484.1,12078.9 ; 7182,9978.9 18862.71,9978.9 18862.71,12078.9 7182,12078.9 7182,9978.9
  text "Symbol" at 7272,11973.9 h72
  text "Count" at 7777.88,11973.9 h72
  text "Hole Size" at 8437.7,11973.9 h72
  text "Plated" at 9587.36,11973.9 h72
  text "Hole Type" at 10093.24,11973.9 h72
  text "Drill Layer Pair" at 10827.04,11973.9 h72
  text "Via/Pad" at 13356.26,11973.9 h72
  text "Pad Shape" at 13946.1,11973.9 h72
  text "Template" at 14691.9,11973.9 h72
  text "Description" at 15341.73,11973.9 h72
  text "Hole Tolerance (+)" at 16195.5,11973.9 h72
  text "Hole Tolerance (-)" at 17529.1,11973.9 h72
  text "1" at 7777.88,11823.9 h60
  text "62.00mil (1.575mm)" at 8437.7,11823.9 h60
  text "PTH" at 9587.36,11823.9 h60
  text "Round" at 10093.24,11823.9 h60
  text "L1-Top Layer (GTL) - L8-Bottom Layer (GBL)" at 10827.04,11823.9 h60
  text "Pad" at 13356.26,11823.9 h60
  text "Rounded" at 13946.1,11823.9 h60
  text "c241h157" at 14691.9,11823.9 h60
  text "1" at 7777.88,11673.9 h60
  text "157.00mil (3.988mm)" at 8437.7,11673.9 h60
  text "PTH" at 9587.36,11673.9 h60
  text "Round" at 10093.24,11673.9 h60
  text "L1-Top Layer (GTL) - L8-Bottom Layer (GBL)" at 10827.04,11673.9 h60
  text "Pad" at 13356.26,11673.9 h60
  text "Rounded" at 13946.1,11673.9 h60
  text "c640h399" at 14691.9,11673.9 h60
  text "2" at 7777.88,11523.9 h60
  text "35.43mil (0.900mm)" at 8437.7,11523.9 h60
  text "NPTH" at 9587.36,11523.9 h60
  text "Round" at 10093.24,11523.9 h60
  text "L1-Top Layer (GTL) - L8-Bottom Layer (GBL)" at 10827.04,11523.9 h60
  text "Pad" at 13356.26,11523.9 h60
  text "Rounded" at 13946.1,11523.9 h60
  text "c90hn90" at 14691.9,11523.9 h60
  text "B" at 7242.91,11513.91 h66.67
  text "4" at 7777.88,11373.9 h60
  text "28.00mil (0.711mm)" at 8437.7,11373.9 h60
  text "PTH" at 9587.36,11373.9 h60
  text "Round" at 10093.24,11373.9 h60
  text "L1-Top Layer (GTL) - L8-Bottom Layer (GBL)" at 10827.04,11373.9 h60
  text "Via" at 13356.26,11373.9 h60
  text "Rounded" at 13946.1,11373.9 h60
  text "v127h71" at 14691.9,11373.9 h60
  text "4" at 7777.88,11223.9 h60
  text "67.00mil (1.702mm)" at 8437.7,11223.9 h60
  text "PTH" at 9587.36,11223.9 h60
  text "Round" at 10093.24,11223.9 h60
  text "L1-Top Layer (GTL) - L8-Bottom Layer (GBL)" at 10827.04,11223.9 h60
  text "Pad" at 13356.26,11223.9 h60
  text "Rounded" at 13946.1,11223.9 h60
  text "c254h170" at 14691.9,11223.9 h60
  text "5" at 7777.88,11073.9 h60
  text "43.00mil (1.092mm)" at 8437.7,11073.9 h60
  text "PTH" at 9587.36,11073.9 h60
  text "Round" at 10093.24,11073.9 h60
  text "L1-Top Layer (GTL) - L8-Bottom Layer (GBL)" at 10827.04,11073.9 h60
  text "Pad" at 13356.26,11073.9 h60
  text "(Mixed)" at 13946.1,11073.9 h60
  text "(Mixed)" at 14691.9,11073.9 h60
  text "5.00mil (0.127mm)" at 16195.5,11073.9 h60
  text "5.00mil (0.127mm)" at 17529.1,11073.9 h60
  text "6" at 7777.88,10923.9 h60
  text "19.69mil (0.500mm)" at 8437.7,10923.9 h60
  text "PTH" at 9587.36,10923.9 h60
  text "Round" at 10093.24,10923.9 h60
  text "L1-Top Layer (GTL) - L8-Bottom Layer (GBL)" at 10827.04,10923.9 h60
  text "Via" at 13356.26,10923.9 h60
  text "Rounded" at 13946.1,10923.9 h60
  text "v100h50m0" at 14691.9,10923.9 h60
  text "10" at 7777.88,10773.9 h60
  text "20.00mil (0.508mm)" at 8437.7,10773.9 h60
  text "PTH" at 9587.36,10773.9 h60
  text "Round" at 10093.24,10773.9 h60
  text "L1-Top Layer (GTL) - L8-Bottom Layer (GBL)" at 10827.04,10773.9 h60
  text "Via" at 13356.26,10773.9 h60
  text "Rounded" at 13946.1,10773.9 h60
  text "v102h51" at 14691.9,10773.9 h60
  text "15" at 7777.88,10623.9 h60
  text "40.00mil (1.016mm)" at 8437.7,10623.9 h60
  text "PTH" at 9587.36,10623.9 h60
  text "Round" at 10093.24,10623.9 h60
  text "L1-Top Layer (GTL) - L8-Bottom Layer (GBL)" at 10827.04,10623.9 h60
  text "Pad" at 13356.26,10623.9 h60
  text "Rounded" at 13946.1,10623.9 h60
  text "c203h102" at 14691.9,10623.9 h60
  text "47" at 7777.88,10473.9 h60
  text "7.87mil (0.200mm)" at 8437.7,10473.9 h60
  text "PTH" at 9587.36,10473.9 h60
  text "Round" at 10093.24,10473.9 h60
  text "L1-Top Layer (GTL) - L8-Bottom Layer (GBL)" at 10827.04,10473.9 h60
  text "Via" at 13356.26,10473.9 h60
  text "Rounded" at 13946.1,10473.9 h60
  text "(Mixed)" at 14691.9,10473.9 h60
  text "773" at 7777.88,10323.9 h60
  text "12.00mil (0.305mm)" at 8437.7,10323.9 h60
  text "PTH" at 9587.36,10323.9 h60
  text "Round" at 10093.24,10323.9 h60
  text "L1-Top Layer (GTL) - L8-Bottom Layer (GBL)" at 10827.04,10323.9 h60
  text "Via" at 13356.26,10323.9 h60
  text "Rounded" at 13946.1,10323.9 h60
  text "(Mixed)" at 14691.9,10323.9 h60
  text "1362" at 7777.88,10173.9 h60
  text "10.00mil (0.254mm)" at 8437.7,10173.9 h60
  text "PTH" at 9587.36,10173.9 h60
  text "Round" at 10093.24,10173.9 h60
  text "L1-Top Layer (GTL) - L8-Bottom Layer (GBL)" at 10827.04,10173.9 h60
  text "Via" at 13356.26,10173.9 h60
  text "Rounded" at 13946.1,10173.9 h60
  text "(Mixed)" at 14691.9,10173.9 h60
  text "C" at 7242.91,10163.91 h66.67
  text "2230 Total" at 7777.88,10023.9 h60
  text ".Layer_Name" at 321,-1754.49 h60
M18 Embedded Assembly:
  text ".Layer_Name" at 577,-1758.49 h60

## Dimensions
7000,9161 to 7000,0 on M2 Board Dimensions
